VERSION 5.8 ;
BUSBITCHARS "[]" ;
DIVIDERCHAR "/" ;
UNITS
    DATABASE MICRONS 1000 ;
END UNITS

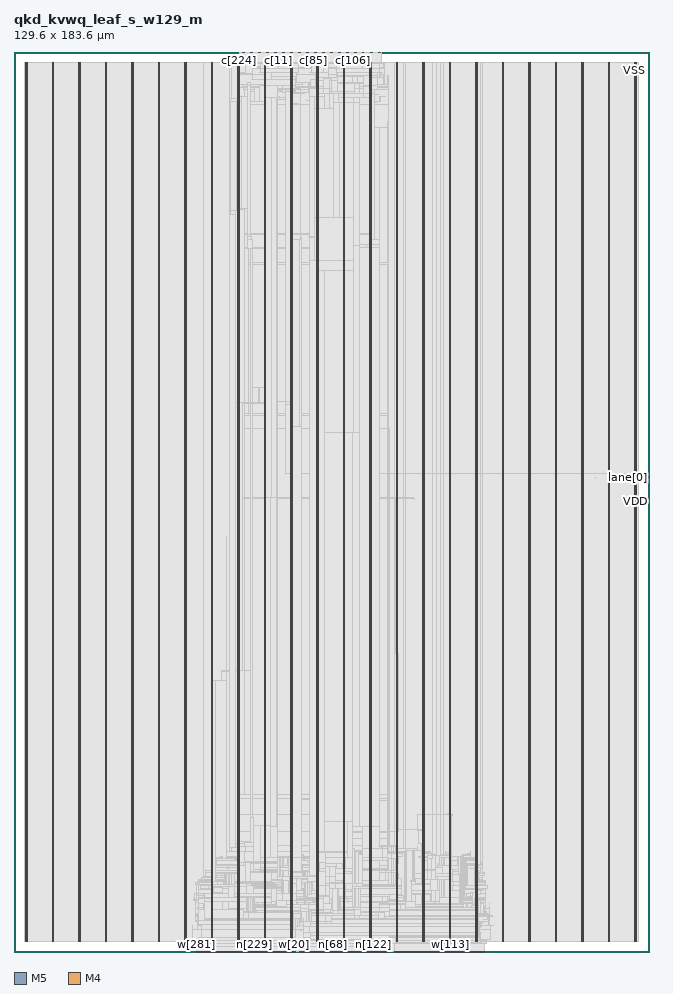
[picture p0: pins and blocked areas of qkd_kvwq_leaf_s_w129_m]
MACRO qkd_kvwq_leaf_s_w129_m
  FOREIGN qkd_kvwq_leaf_s_w129_m 0 0 ;
  CLASS BLOCK ;
  SIZE 129.6 BY 183.6 ;
  PIN c[0]
    DIRECTION INPUT ;
    USE SIGNAL ;
    PORT
      LAYER M5 ;
        RECT  52.848 183.516 52.872 183.6 ;
    END
  END c[0]
  PIN c[100]
    DIRECTION INPUT ;
    USE SIGNAL ;
    PORT
      LAYER M5 ;
        RECT  68.592 183.516 68.616 183.6 ;
    END
  END c[100]
  PIN c[101]
    DIRECTION INPUT ;
    USE SIGNAL ;
    PORT
      LAYER M5 ;
        RECT  68.688 183.516 68.712 183.6 ;
    END
  END c[101]
  PIN c[102]
    DIRECTION INPUT ;
    USE SIGNAL ;
    PORT
      LAYER M5 ;
        RECT  68.784 183.516 68.808 183.6 ;
    END
  END c[102]
  PIN c[103]
    DIRECTION INPUT ;
    USE SIGNAL ;
    PORT
      LAYER M5 ;
        RECT  68.88 183.516 68.904 183.6 ;
    END
  END c[103]
  PIN c[104]
    DIRECTION INPUT ;
    USE SIGNAL ;
    PORT
      LAYER M5 ;
        RECT  68.976 183.516 69 183.6 ;
    END
  END c[104]
  PIN c[105]
    DIRECTION INPUT ;
    USE SIGNAL ;
    PORT
      LAYER M5 ;
        RECT  69.072 183.516 69.096 183.6 ;
    END
  END c[105]
  PIN c[106]
    DIRECTION INPUT ;
    USE SIGNAL ;
    PORT
      LAYER M5 ;
        RECT  69.168 183.516 69.192 183.6 ;
    END
  END c[106]
  PIN c[107]
    DIRECTION INPUT ;
    USE SIGNAL ;
    PORT
      LAYER M5 ;
        RECT  69.264 183.516 69.288 183.6 ;
    END
  END c[107]
  PIN c[108]
    DIRECTION INPUT ;
    USE SIGNAL ;
    PORT
      LAYER M5 ;
        RECT  69.36 183.516 69.384 183.6 ;
    END
  END c[108]
  PIN c[109]
    DIRECTION INPUT ;
    USE SIGNAL ;
    PORT
      LAYER M5 ;
        RECT  69.456 183.516 69.48 183.6 ;
    END
  END c[109]
  PIN c[10]
    DIRECTION INPUT ;
    USE SIGNAL ;
    PORT
      LAYER M5 ;
        RECT  53.808 183.516 53.832 183.6 ;
    END
  END c[10]
  PIN c[110]
    DIRECTION INPUT ;
    USE SIGNAL ;
    PORT
      LAYER M5 ;
        RECT  69.552 183.516 69.576 183.6 ;
    END
  END c[110]
  PIN c[111]
    DIRECTION INPUT ;
    USE SIGNAL ;
    PORT
      LAYER M5 ;
        RECT  69.648 183.516 69.672 183.6 ;
    END
  END c[111]
  PIN c[112]
    DIRECTION INPUT ;
    USE SIGNAL ;
    PORT
      LAYER M5 ;
        RECT  69.744 183.516 69.768 183.6 ;
    END
  END c[112]
  PIN c[113]
    DIRECTION INPUT ;
    USE SIGNAL ;
    PORT
      LAYER M5 ;
        RECT  69.84 183.516 69.864 183.6 ;
    END
  END c[113]
  PIN c[114]
    DIRECTION INPUT ;
    USE SIGNAL ;
    PORT
      LAYER M5 ;
        RECT  69.936 183.516 69.96 183.6 ;
    END
  END c[114]
  PIN c[115]
    DIRECTION INPUT ;
    USE SIGNAL ;
    PORT
      LAYER M5 ;
        RECT  70.032 183.516 70.056 183.6 ;
    END
  END c[115]
  PIN c[116]
    DIRECTION INPUT ;
    USE SIGNAL ;
    PORT
      LAYER M5 ;
        RECT  70.128 183.516 70.152 183.6 ;
    END
  END c[116]
  PIN c[117]
    DIRECTION INPUT ;
    USE SIGNAL ;
    PORT
      LAYER M5 ;
        RECT  70.224 183.516 70.248 183.6 ;
    END
  END c[117]
  PIN c[118]
    DIRECTION INPUT ;
    USE SIGNAL ;
    PORT
      LAYER M5 ;
        RECT  70.32 183.516 70.344 183.6 ;
    END
  END c[118]
  PIN c[119]
    DIRECTION INPUT ;
    USE SIGNAL ;
    PORT
      LAYER M5 ;
        RECT  70.416 183.516 70.44 183.6 ;
    END
  END c[119]
  PIN c[11]
    DIRECTION INPUT ;
    USE SIGNAL ;
    PORT
      LAYER M5 ;
        RECT  53.904 183.516 53.928 183.6 ;
    END
  END c[11]
  PIN c[120]
    DIRECTION INPUT ;
    USE SIGNAL ;
    PORT
      LAYER M5 ;
        RECT  70.512 183.516 70.536 183.6 ;
    END
  END c[120]
  PIN c[121]
    DIRECTION INPUT ;
    USE SIGNAL ;
    PORT
      LAYER M5 ;
        RECT  70.608 183.516 70.632 183.6 ;
    END
  END c[121]
  PIN c[122]
    DIRECTION INPUT ;
    USE SIGNAL ;
    PORT
      LAYER M5 ;
        RECT  70.704 183.516 70.728 183.6 ;
    END
  END c[122]
  PIN c[123]
    DIRECTION INPUT ;
    USE SIGNAL ;
    PORT
      LAYER M5 ;
        RECT  70.8 183.516 70.824 183.6 ;
    END
  END c[123]
  PIN c[124]
    DIRECTION INPUT ;
    USE SIGNAL ;
    PORT
      LAYER M5 ;
        RECT  70.896 183.516 70.92 183.6 ;
    END
  END c[124]
  PIN c[125]
    DIRECTION INPUT ;
    USE SIGNAL ;
    PORT
      LAYER M5 ;
        RECT  70.992 183.516 71.016 183.6 ;
    END
  END c[125]
  PIN c[126]
    DIRECTION INPUT ;
    USE SIGNAL ;
    PORT
      LAYER M5 ;
        RECT  71.088 183.516 71.112 183.6 ;
    END
  END c[126]
  PIN c[127]
    DIRECTION INPUT ;
    USE SIGNAL ;
    PORT
      LAYER M5 ;
        RECT  71.184 183.516 71.208 183.6 ;
    END
  END c[127]
  PIN c[128]
    DIRECTION INPUT ;
    USE SIGNAL ;
    PORT
      LAYER M5 ;
        RECT  65.136 183.516 65.16 183.6 ;
    END
  END c[128]
  PIN c[129]
    DIRECTION INPUT ;
    USE SIGNAL ;
    PORT
      LAYER M5 ;
        RECT  65.232 183.516 65.256 183.6 ;
    END
  END c[129]
  PIN c[12]
    DIRECTION INPUT ;
    USE SIGNAL ;
    PORT
      LAYER M5 ;
        RECT  54 183.516 54.024 183.6 ;
    END
  END c[12]
  PIN c[130]
    DIRECTION INPUT ;
    USE SIGNAL ;
    PORT
      LAYER M5 ;
        RECT  65.328 183.516 65.352 183.6 ;
    END
  END c[130]
  PIN c[131]
    DIRECTION INPUT ;
    USE SIGNAL ;
    PORT
      LAYER M5 ;
        RECT  65.424 183.516 65.448 183.6 ;
    END
  END c[131]
  PIN c[132]
    DIRECTION INPUT ;
    USE SIGNAL ;
    PORT
      LAYER M5 ;
        RECT  65.52 183.516 65.544 183.6 ;
    END
  END c[132]
  PIN c[133]
    DIRECTION INPUT ;
    USE SIGNAL ;
    PORT
      LAYER M5 ;
        RECT  65.616 183.516 65.64 183.6 ;
    END
  END c[133]
  PIN c[134]
    DIRECTION INPUT ;
    USE SIGNAL ;
    PORT
      LAYER M5 ;
        RECT  65.712 183.516 65.736 183.6 ;
    END
  END c[134]
  PIN c[135]
    DIRECTION INPUT ;
    USE SIGNAL ;
    PORT
      LAYER M5 ;
        RECT  65.808 183.516 65.832 183.6 ;
    END
  END c[135]
  PIN c[136]
    DIRECTION INPUT ;
    USE SIGNAL ;
    PORT
      LAYER M5 ;
        RECT  65.904 183.516 65.928 183.6 ;
    END
  END c[136]
  PIN c[137]
    DIRECTION INPUT ;
    USE SIGNAL ;
    PORT
      LAYER M5 ;
        RECT  66 183.516 66.024 183.6 ;
    END
  END c[137]
  PIN c[138]
    DIRECTION INPUT ;
    USE SIGNAL ;
    PORT
      LAYER M5 ;
        RECT  66.096 183.516 66.12 183.6 ;
    END
  END c[138]
  PIN c[139]
    DIRECTION INPUT ;
    USE SIGNAL ;
    PORT
      LAYER M5 ;
        RECT  66.192 183.516 66.216 183.6 ;
    END
  END c[139]
  PIN c[13]
    DIRECTION INPUT ;
    USE SIGNAL ;
    PORT
      LAYER M5 ;
        RECT  54.096 183.516 54.12 183.6 ;
    END
  END c[13]
  PIN c[140]
    DIRECTION INPUT ;
    USE SIGNAL ;
    PORT
      LAYER M5 ;
        RECT  66.288 183.516 66.312 183.6 ;
    END
  END c[140]
  PIN c[141]
    DIRECTION INPUT ;
    USE SIGNAL ;
    PORT
      LAYER M5 ;
        RECT  66.384 183.516 66.408 183.6 ;
    END
  END c[141]
  PIN c[142]
    DIRECTION INPUT ;
    USE SIGNAL ;
    PORT
      LAYER M5 ;
        RECT  66.48 183.516 66.504 183.6 ;
    END
  END c[142]
  PIN c[143]
    DIRECTION INPUT ;
    USE SIGNAL ;
    PORT
      LAYER M5 ;
        RECT  66.576 183.516 66.6 183.6 ;
    END
  END c[143]
  PIN c[144]
    DIRECTION INPUT ;
    USE SIGNAL ;
    PORT
      LAYER M5 ;
        RECT  66.672 183.516 66.696 183.6 ;
    END
  END c[144]
  PIN c[145]
    DIRECTION INPUT ;
    USE SIGNAL ;
    PORT
      LAYER M5 ;
        RECT  66.768 183.516 66.792 183.6 ;
    END
  END c[145]
  PIN c[146]
    DIRECTION INPUT ;
    USE SIGNAL ;
    PORT
      LAYER M5 ;
        RECT  66.864 183.516 66.888 183.6 ;
    END
  END c[146]
  PIN c[147]
    DIRECTION INPUT ;
    USE SIGNAL ;
    PORT
      LAYER M5 ;
        RECT  66.96 183.516 66.984 183.6 ;
    END
  END c[147]
  PIN c[148]
    DIRECTION INPUT ;
    USE SIGNAL ;
    PORT
      LAYER M5 ;
        RECT  67.056 183.516 67.08 183.6 ;
    END
  END c[148]
  PIN c[149]
    DIRECTION INPUT ;
    USE SIGNAL ;
    PORT
      LAYER M5 ;
        RECT  67.152 183.516 67.176 183.6 ;
    END
  END c[149]
  PIN c[14]
    DIRECTION INPUT ;
    USE SIGNAL ;
    PORT
      LAYER M5 ;
        RECT  54.192 183.516 54.216 183.6 ;
    END
  END c[14]
  PIN c[150]
    DIRECTION INPUT ;
    USE SIGNAL ;
    PORT
      LAYER M5 ;
        RECT  67.248 183.516 67.272 183.6 ;
    END
  END c[150]
  PIN c[151]
    DIRECTION INPUT ;
    USE SIGNAL ;
    PORT
      LAYER M5 ;
        RECT  67.344 183.516 67.368 183.6 ;
    END
  END c[151]
  PIN c[152]
    DIRECTION INPUT ;
    USE SIGNAL ;
    PORT
      LAYER M5 ;
        RECT  67.44 183.516 67.464 183.6 ;
    END
  END c[152]
  PIN c[153]
    DIRECTION INPUT ;
    USE SIGNAL ;
    PORT
      LAYER M5 ;
        RECT  67.536 183.516 67.56 183.6 ;
    END
  END c[153]
  PIN c[154]
    DIRECTION INPUT ;
    USE SIGNAL ;
    PORT
      LAYER M5 ;
        RECT  67.632 183.516 67.656 183.6 ;
    END
  END c[154]
  PIN c[155]
    DIRECTION INPUT ;
    USE SIGNAL ;
    PORT
      LAYER M5 ;
        RECT  67.728 183.516 67.752 183.6 ;
    END
  END c[155]
  PIN c[156]
    DIRECTION INPUT ;
    USE SIGNAL ;
    PORT
      LAYER M5 ;
        RECT  67.824 183.516 67.848 183.6 ;
    END
  END c[156]
  PIN c[157]
    DIRECTION INPUT ;
    USE SIGNAL ;
    PORT
      LAYER M5 ;
        RECT  67.92 183.516 67.944 183.6 ;
    END
  END c[157]
  PIN c[158]
    DIRECTION INPUT ;
    USE SIGNAL ;
    PORT
      LAYER M5 ;
        RECT  68.016 183.516 68.04 183.6 ;
    END
  END c[158]
  PIN c[159]
    DIRECTION INPUT ;
    USE SIGNAL ;
    PORT
      LAYER M5 ;
        RECT  68.112 183.516 68.136 183.6 ;
    END
  END c[159]
  PIN c[15]
    DIRECTION INPUT ;
    USE SIGNAL ;
    PORT
      LAYER M5 ;
        RECT  54.288 183.516 54.312 183.6 ;
    END
  END c[15]
  PIN c[160]
    DIRECTION INPUT ;
    USE SIGNAL ;
    PORT
      LAYER M5 ;
        RECT  62.064 183.516 62.088 183.6 ;
    END
  END c[160]
  PIN c[161]
    DIRECTION INPUT ;
    USE SIGNAL ;
    PORT
      LAYER M5 ;
        RECT  62.16 183.516 62.184 183.6 ;
    END
  END c[161]
  PIN c[162]
    DIRECTION INPUT ;
    USE SIGNAL ;
    PORT
      LAYER M5 ;
        RECT  62.256 183.516 62.28 183.6 ;
    END
  END c[162]
  PIN c[163]
    DIRECTION INPUT ;
    USE SIGNAL ;
    PORT
      LAYER M5 ;
        RECT  62.352 183.516 62.376 183.6 ;
    END
  END c[163]
  PIN c[164]
    DIRECTION INPUT ;
    USE SIGNAL ;
    PORT
      LAYER M5 ;
        RECT  62.448 183.516 62.472 183.6 ;
    END
  END c[164]
  PIN c[165]
    DIRECTION INPUT ;
    USE SIGNAL ;
    PORT
      LAYER M5 ;
        RECT  62.544 183.516 62.568 183.6 ;
    END
  END c[165]
  PIN c[166]
    DIRECTION INPUT ;
    USE SIGNAL ;
    PORT
      LAYER M5 ;
        RECT  62.64 183.516 62.664 183.6 ;
    END
  END c[166]
  PIN c[167]
    DIRECTION INPUT ;
    USE SIGNAL ;
    PORT
      LAYER M5 ;
        RECT  62.736 183.516 62.76 183.6 ;
    END
  END c[167]
  PIN c[168]
    DIRECTION INPUT ;
    USE SIGNAL ;
    PORT
      LAYER M5 ;
        RECT  62.832 183.516 62.856 183.6 ;
    END
  END c[168]
  PIN c[169]
    DIRECTION INPUT ;
    USE SIGNAL ;
    PORT
      LAYER M5 ;
        RECT  62.928 183.516 62.952 183.6 ;
    END
  END c[169]
  PIN c[16]
    DIRECTION INPUT ;
    USE SIGNAL ;
    PORT
      LAYER M5 ;
        RECT  54.384 183.516 54.408 183.6 ;
    END
  END c[16]
  PIN c[170]
    DIRECTION INPUT ;
    USE SIGNAL ;
    PORT
      LAYER M5 ;
        RECT  63.024 183.516 63.048 183.6 ;
    END
  END c[170]
  PIN c[171]
    DIRECTION INPUT ;
    USE SIGNAL ;
    PORT
      LAYER M5 ;
        RECT  63.12 183.516 63.144 183.6 ;
    END
  END c[171]
  PIN c[172]
    DIRECTION INPUT ;
    USE SIGNAL ;
    PORT
      LAYER M5 ;
        RECT  63.216 183.516 63.24 183.6 ;
    END
  END c[172]
  PIN c[173]
    DIRECTION INPUT ;
    USE SIGNAL ;
    PORT
      LAYER M5 ;
        RECT  63.312 183.516 63.336 183.6 ;
    END
  END c[173]
  PIN c[174]
    DIRECTION INPUT ;
    USE SIGNAL ;
    PORT
      LAYER M5 ;
        RECT  63.408 183.516 63.432 183.6 ;
    END
  END c[174]
  PIN c[175]
    DIRECTION INPUT ;
    USE SIGNAL ;
    PORT
      LAYER M5 ;
        RECT  63.504 183.516 63.528 183.6 ;
    END
  END c[175]
  PIN c[176]
    DIRECTION INPUT ;
    USE SIGNAL ;
    PORT
      LAYER M5 ;
        RECT  63.6 183.516 63.624 183.6 ;
    END
  END c[176]
  PIN c[177]
    DIRECTION INPUT ;
    USE SIGNAL ;
    PORT
      LAYER M5 ;
        RECT  63.696 183.516 63.72 183.6 ;
    END
  END c[177]
  PIN c[178]
    DIRECTION INPUT ;
    USE SIGNAL ;
    PORT
      LAYER M5 ;
        RECT  63.792 183.516 63.816 183.6 ;
    END
  END c[178]
  PIN c[179]
    DIRECTION INPUT ;
    USE SIGNAL ;
    PORT
      LAYER M5 ;
        RECT  63.888 183.516 63.912 183.6 ;
    END
  END c[179]
  PIN c[17]
    DIRECTION INPUT ;
    USE SIGNAL ;
    PORT
      LAYER M5 ;
        RECT  54.48 183.516 54.504 183.6 ;
    END
  END c[17]
  PIN c[180]
    DIRECTION INPUT ;
    USE SIGNAL ;
    PORT
      LAYER M5 ;
        RECT  63.984 183.516 64.008 183.6 ;
    END
  END c[180]
  PIN c[181]
    DIRECTION INPUT ;
    USE SIGNAL ;
    PORT
      LAYER M5 ;
        RECT  64.08 183.516 64.104 183.6 ;
    END
  END c[181]
  PIN c[182]
    DIRECTION INPUT ;
    USE SIGNAL ;
    PORT
      LAYER M5 ;
        RECT  64.176 183.516 64.2 183.6 ;
    END
  END c[182]
  PIN c[183]
    DIRECTION INPUT ;
    USE SIGNAL ;
    PORT
      LAYER M5 ;
        RECT  64.272 183.516 64.296 183.6 ;
    END
  END c[183]
  PIN c[184]
    DIRECTION INPUT ;
    USE SIGNAL ;
    PORT
      LAYER M5 ;
        RECT  64.368 183.516 64.392 183.6 ;
    END
  END c[184]
  PIN c[185]
    DIRECTION INPUT ;
    USE SIGNAL ;
    PORT
      LAYER M5 ;
        RECT  64.464 183.516 64.488 183.6 ;
    END
  END c[185]
  PIN c[186]
    DIRECTION INPUT ;
    USE SIGNAL ;
    PORT
      LAYER M5 ;
        RECT  64.56 183.516 64.584 183.6 ;
    END
  END c[186]
  PIN c[187]
    DIRECTION INPUT ;
    USE SIGNAL ;
    PORT
      LAYER M5 ;
        RECT  64.656 183.516 64.68 183.6 ;
    END
  END c[187]
  PIN c[188]
    DIRECTION INPUT ;
    USE SIGNAL ;
    PORT
      LAYER M5 ;
        RECT  64.752 183.516 64.776 183.6 ;
    END
  END c[188]
  PIN c[189]
    DIRECTION INPUT ;
    USE SIGNAL ;
    PORT
      LAYER M5 ;
        RECT  64.848 183.516 64.872 183.6 ;
    END
  END c[189]
  PIN c[18]
    DIRECTION INPUT ;
    USE SIGNAL ;
    PORT
      LAYER M5 ;
        RECT  54.576 183.516 54.6 183.6 ;
    END
  END c[18]
  PIN c[190]
    DIRECTION INPUT ;
    USE SIGNAL ;
    PORT
      LAYER M5 ;
        RECT  64.944 183.516 64.968 183.6 ;
    END
  END c[190]
  PIN c[191]
    DIRECTION INPUT ;
    USE SIGNAL ;
    PORT
      LAYER M5 ;
        RECT  65.04 183.516 65.064 183.6 ;
    END
  END c[191]
  PIN c[192]
    DIRECTION INPUT ;
    USE SIGNAL ;
    PORT
      LAYER M5 ;
        RECT  72.048 183.516 72.072 183.6 ;
    END
  END c[192]
  PIN c[193]
    DIRECTION INPUT ;
    USE SIGNAL ;
    PORT
      LAYER M5 ;
        RECT  72.144 183.516 72.168 183.6 ;
    END
  END c[193]
  PIN c[194]
    DIRECTION INPUT ;
    USE SIGNAL ;
    PORT
      LAYER M5 ;
        RECT  72.24 183.516 72.264 183.6 ;
    END
  END c[194]
  PIN c[195]
    DIRECTION INPUT ;
    USE SIGNAL ;
    PORT
      LAYER M5 ;
        RECT  72.336 183.516 72.36 183.6 ;
    END
  END c[195]
  PIN c[196]
    DIRECTION INPUT ;
    USE SIGNAL ;
    PORT
      LAYER M5 ;
        RECT  72.432 183.516 72.456 183.6 ;
    END
  END c[196]
  PIN c[197]
    DIRECTION INPUT ;
    USE SIGNAL ;
    PORT
      LAYER M5 ;
        RECT  72.528 183.516 72.552 183.6 ;
    END
  END c[197]
  PIN c[198]
    DIRECTION INPUT ;
    USE SIGNAL ;
    PORT
      LAYER M5 ;
        RECT  72.624 183.516 72.648 183.6 ;
    END
  END c[198]
  PIN c[199]
    DIRECTION INPUT ;
    USE SIGNAL ;
    PORT
      LAYER M5 ;
        RECT  72.72 183.516 72.744 183.6 ;
    END
  END c[199]
  PIN c[19]
    DIRECTION INPUT ;
    USE SIGNAL ;
    PORT
      LAYER M5 ;
        RECT  54.672 183.516 54.696 183.6 ;
    END
  END c[19]
  PIN c[1]
    DIRECTION INPUT ;
    USE SIGNAL ;
    PORT
      LAYER M5 ;
        RECT  52.944 183.516 52.968 183.6 ;
    END
  END c[1]
  PIN c[200]
    DIRECTION INPUT ;
    USE SIGNAL ;
    PORT
      LAYER M5 ;
        RECT  72.816 183.516 72.84 183.6 ;
    END
  END c[200]
  PIN c[201]
    DIRECTION INPUT ;
    USE SIGNAL ;
    PORT
      LAYER M5 ;
        RECT  72.912 183.516 72.936 183.6 ;
    END
  END c[201]
  PIN c[202]
    DIRECTION INPUT ;
    USE SIGNAL ;
    PORT
      LAYER M5 ;
        RECT  73.008 183.516 73.032 183.6 ;
    END
  END c[202]
  PIN c[203]
    DIRECTION INPUT ;
    USE SIGNAL ;
    PORT
      LAYER M5 ;
        RECT  73.104 183.516 73.128 183.6 ;
    END
  END c[203]
  PIN c[204]
    DIRECTION INPUT ;
    USE SIGNAL ;
    PORT
      LAYER M5 ;
        RECT  73.2 183.516 73.224 183.6 ;
    END
  END c[204]
  PIN c[205]
    DIRECTION INPUT ;
    USE SIGNAL ;
    PORT
      LAYER M5 ;
        RECT  73.296 183.516 73.32 183.6 ;
    END
  END c[205]
  PIN c[206]
    DIRECTION INPUT ;
    USE SIGNAL ;
    PORT
      LAYER M5 ;
        RECT  73.392 183.516 73.416 183.6 ;
    END
  END c[206]
  PIN c[207]
    DIRECTION INPUT ;
    USE SIGNAL ;
    PORT
      LAYER M5 ;
        RECT  73.488 183.516 73.512 183.6 ;
    END
  END c[207]
  PIN c[208]
    DIRECTION INPUT ;
    USE SIGNAL ;
    PORT
      LAYER M5 ;
        RECT  73.584 183.516 73.608 183.6 ;
    END
  END c[208]
  PIN c[209]
    DIRECTION INPUT ;
    USE SIGNAL ;
    PORT
      LAYER M5 ;
        RECT  73.68 183.516 73.704 183.6 ;
    END
  END c[209]
  PIN c[20]
    DIRECTION INPUT ;
    USE SIGNAL ;
    PORT
      LAYER M5 ;
        RECT  54.768 183.516 54.792 183.6 ;
    END
  END c[20]
  PIN c[210]
    DIRECTION INPUT ;
    USE SIGNAL ;
    PORT
      LAYER M5 ;
        RECT  73.776 183.516 73.8 183.6 ;
    END
  END c[210]
  PIN c[211]
    DIRECTION INPUT ;
    USE SIGNAL ;
    PORT
      LAYER M5 ;
        RECT  73.872 183.516 73.896 183.6 ;
    END
  END c[211]
  PIN c[212]
    DIRECTION INPUT ;
    USE SIGNAL ;
    PORT
      LAYER M5 ;
        RECT  73.968 183.516 73.992 183.6 ;
    END
  END c[212]
  PIN c[213]
    DIRECTION INPUT ;
    USE SIGNAL ;
    PORT
      LAYER M5 ;
        RECT  74.064 183.516 74.088 183.6 ;
    END
  END c[213]
  PIN c[214]
    DIRECTION INPUT ;
    USE SIGNAL ;
    PORT
      LAYER M5 ;
        RECT  74.16 183.516 74.184 183.6 ;
    END
  END c[214]
  PIN c[215]
    DIRECTION INPUT ;
    USE SIGNAL ;
    PORT
      LAYER M5 ;
        RECT  74.256 183.516 74.28 183.6 ;
    END
  END c[215]
  PIN c[216]
    DIRECTION INPUT ;
    USE SIGNAL ;
    PORT
      LAYER M5 ;
        RECT  74.352 183.516 74.376 183.6 ;
    END
  END c[216]
  PIN c[217]
    DIRECTION INPUT ;
    USE SIGNAL ;
    PORT
      LAYER M5 ;
        RECT  74.448 183.516 74.472 183.6 ;
    END
  END c[217]
  PIN c[218]
    DIRECTION INPUT ;
    USE SIGNAL ;
    PORT
      LAYER M5 ;
        RECT  74.544 183.516 74.568 183.6 ;
    END
  END c[218]
  PIN c[219]
    DIRECTION INPUT ;
    USE SIGNAL ;
    PORT
      LAYER M5 ;
        RECT  74.64 183.516 74.664 183.6 ;
    END
  END c[219]
  PIN c[21]
    DIRECTION INPUT ;
    USE SIGNAL ;
    PORT
      LAYER M5 ;
        RECT  54.864 183.516 54.888 183.6 ;
    END
  END c[21]
  PIN c[220]
    DIRECTION INPUT ;
    USE SIGNAL ;
    PORT
      LAYER M5 ;
        RECT  74.736 183.516 74.76 183.6 ;
    END
  END c[220]
  PIN c[221]
    DIRECTION INPUT ;
    USE SIGNAL ;
    PORT
      LAYER M5 ;
        RECT  74.832 183.516 74.856 183.6 ;
    END
  END c[221]
  PIN c[222]
    DIRECTION INPUT ;
    USE SIGNAL ;
    PORT
      LAYER M5 ;
        RECT  74.928 183.516 74.952 183.6 ;
    END
  END c[222]
  PIN c[223]
    DIRECTION INPUT ;
    USE SIGNAL ;
    PORT
      LAYER M5 ;
        RECT  75.024 183.516 75.048 183.6 ;
    END
  END c[223]
  PIN c[224]
    DIRECTION INPUT ;
    USE SIGNAL ;
    PORT
      LAYER M5 ;
        RECT  45.936 183.516 45.96 183.6 ;
    END
  END c[224]
  PIN c[225]
    DIRECTION INPUT ;
    USE SIGNAL ;
    PORT
      LAYER M5 ;
        RECT  46.032 183.516 46.056 183.6 ;
    END
  END c[225]
  PIN c[226]
    DIRECTION INPUT ;
    USE SIGNAL ;
    PORT
      LAYER M5 ;
        RECT  46.128 183.516 46.152 183.6 ;
    END
  END c[226]
  PIN c[227]
    DIRECTION INPUT ;
    USE SIGNAL ;
    PORT
      LAYER M5 ;
        RECT  46.224 183.516 46.248 183.6 ;
    END
  END c[227]
  PIN c[228]
    DIRECTION INPUT ;
    USE SIGNAL ;
    PORT
      LAYER M5 ;
        RECT  46.32 183.516 46.344 183.6 ;
    END
  END c[228]
  PIN c[229]
    DIRECTION INPUT ;
    USE SIGNAL ;
    PORT
      LAYER M5 ;
        RECT  46.416 183.516 46.44 183.6 ;
    END
  END c[229]
  PIN c[22]
    DIRECTION INPUT ;
    USE SIGNAL ;
    PORT
      LAYER M5 ;
        RECT  54.96 183.516 54.984 183.6 ;
    END
  END c[22]
  PIN c[230]
    DIRECTION INPUT ;
    USE SIGNAL ;
    PORT
      LAYER M5 ;
        RECT  46.512 183.516 46.536 183.6 ;
    END
  END c[230]
  PIN c[231]
    DIRECTION INPUT ;
    USE SIGNAL ;
    PORT
      LAYER M5 ;
        RECT  46.608 183.516 46.632 183.6 ;
    END
  END c[231]
  PIN c[232]
    DIRECTION INPUT ;
    USE SIGNAL ;
    PORT
      LAYER M5 ;
        RECT  46.704 183.516 46.728 183.6 ;
    END
  END c[232]
  PIN c[233]
    DIRECTION INPUT ;
    USE SIGNAL ;
    PORT
      LAYER M5 ;
        RECT  46.8 183.516 46.824 183.6 ;
    END
  END c[233]
  PIN c[234]
    DIRECTION INPUT ;
    USE SIGNAL ;
    PORT
      LAYER M5 ;
        RECT  46.896 183.516 46.92 183.6 ;
    END
  END c[234]
  PIN c[235]
    DIRECTION INPUT ;
    USE SIGNAL ;
    PORT
      LAYER M5 ;
        RECT  46.992 183.516 47.016 183.6 ;
    END
  END c[235]
  PIN c[236]
    DIRECTION INPUT ;
    USE SIGNAL ;
    PORT
      LAYER M5 ;
        RECT  47.088 183.516 47.112 183.6 ;
    END
  END c[236]
  PIN c[237]
    DIRECTION INPUT ;
    USE SIGNAL ;
    PORT
      LAYER M5 ;
        RECT  47.184 183.516 47.208 183.6 ;
    END
  END c[237]
  PIN c[238]
    DIRECTION INPUT ;
    USE SIGNAL ;
    PORT
      LAYER M5 ;
        RECT  47.28 183.516 47.304 183.6 ;
    END
  END c[238]
  PIN c[239]
    DIRECTION INPUT ;
    USE SIGNAL ;
    PORT
      LAYER M5 ;
        RECT  47.376 183.516 47.4 183.6 ;
    END
  END c[239]
  PIN c[23]
    DIRECTION INPUT ;
    USE SIGNAL ;
    PORT
      LAYER M5 ;
        RECT  55.056 183.516 55.08 183.6 ;
    END
  END c[23]
  PIN c[240]
    DIRECTION INPUT ;
    USE SIGNAL ;
    PORT
      LAYER M5 ;
        RECT  47.472 183.516 47.496 183.6 ;
    END
  END c[240]
  PIN c[241]
    DIRECTION INPUT ;
    USE SIGNAL ;
    PORT
      LAYER M5 ;
        RECT  47.568 183.516 47.592 183.6 ;
    END
  END c[241]
  PIN c[242]
    DIRECTION INPUT ;
    USE SIGNAL ;
    PORT
      LAYER M5 ;
        RECT  47.664 183.516 47.688 183.6 ;
    END
  END c[242]
  PIN c[243]
    DIRECTION INPUT ;
    USE SIGNAL ;
    PORT
      LAYER M5 ;
        RECT  47.76 183.516 47.784 183.6 ;
    END
  END c[243]
  PIN c[244]
    DIRECTION INPUT ;
    USE SIGNAL ;
    PORT
      LAYER M5 ;
        RECT  47.856 183.516 47.88 183.6 ;
    END
  END c[244]
  PIN c[245]
    DIRECTION INPUT ;
    USE SIGNAL ;
    PORT
      LAYER M5 ;
        RECT  47.952 183.516 47.976 183.6 ;
    END
  END c[245]
  PIN c[246]
    DIRECTION INPUT ;
    USE SIGNAL ;
    PORT
      LAYER M5 ;
        RECT  48.048 183.516 48.072 183.6 ;
    END
  END c[246]
  PIN c[247]
    DIRECTION INPUT ;
    USE SIGNAL ;
    PORT
      LAYER M5 ;
        RECT  48.144 183.516 48.168 183.6 ;
    END
  END c[247]
  PIN c[248]
    DIRECTION INPUT ;
    USE SIGNAL ;
    PORT
      LAYER M5 ;
        RECT  48.24 183.516 48.264 183.6 ;
    END
  END c[248]
  PIN c[249]
    DIRECTION INPUT ;
    USE SIGNAL ;
    PORT
      LAYER M5 ;
        RECT  48.336 183.516 48.36 183.6 ;
    END
  END c[249]
  PIN c[24]
    DIRECTION INPUT ;
    USE SIGNAL ;
    PORT
      LAYER M5 ;
        RECT  55.152 183.516 55.176 183.6 ;
    END
  END c[24]
  PIN c[250]
    DIRECTION INPUT ;
    USE SIGNAL ;
    PORT
      LAYER M5 ;
        RECT  48.432 183.516 48.456 183.6 ;
    END
  END c[250]
  PIN c[251]
    DIRECTION INPUT ;
    USE SIGNAL ;
    PORT
      LAYER M5 ;
        RECT  48.528 183.516 48.552 183.6 ;
    END
  END c[251]
  PIN c[252]
    DIRECTION INPUT ;
    USE SIGNAL ;
    PORT
      LAYER M5 ;
        RECT  48.624 183.516 48.648 183.6 ;
    END
  END c[252]
  PIN c[253]
    DIRECTION INPUT ;
    USE SIGNAL ;
    PORT
      LAYER M5 ;
        RECT  48.72 183.516 48.744 183.6 ;
    END
  END c[253]
  PIN c[254]
    DIRECTION INPUT ;
    USE SIGNAL ;
    PORT
      LAYER M5 ;
        RECT  48.816 183.516 48.84 183.6 ;
    END
  END c[254]
  PIN c[255]
    DIRECTION INPUT ;
    USE SIGNAL ;
    PORT
      LAYER M5 ;
        RECT  48.912 183.516 48.936 183.6 ;
    END
  END c[255]
  PIN c[256]
    DIRECTION INPUT ;
    USE SIGNAL ;
    PORT
      LAYER M5 ;
        RECT  49.008 183.516 49.032 183.6 ;
    END
  END c[256]
  PIN c[257]
    DIRECTION INPUT ;
    USE SIGNAL ;
    PORT
      LAYER M5 ;
        RECT  49.104 183.516 49.128 183.6 ;
    END
  END c[257]
  PIN c[258]
    DIRECTION INPUT ;
    USE SIGNAL ;
    PORT
      LAYER M5 ;
        RECT  49.2 183.516 49.224 183.6 ;
    END
  END c[258]
  PIN c[259]
    DIRECTION INPUT ;
    USE SIGNAL ;
    PORT
      LAYER M5 ;
        RECT  49.296 183.516 49.32 183.6 ;
    END
  END c[259]
  PIN c[25]
    DIRECTION INPUT ;
    USE SIGNAL ;
    PORT
      LAYER M5 ;
        RECT  55.248 183.516 55.272 183.6 ;
    END
  END c[25]
  PIN c[260]
    DIRECTION INPUT ;
    USE SIGNAL ;
    PORT
      LAYER M5 ;
        RECT  49.392 183.516 49.416 183.6 ;
    END
  END c[260]
  PIN c[261]
    DIRECTION INPUT ;
    USE SIGNAL ;
    PORT
      LAYER M5 ;
        RECT  49.488 183.516 49.512 183.6 ;
    END
  END c[261]
  PIN c[262]
    DIRECTION INPUT ;
    USE SIGNAL ;
    PORT
      LAYER M5 ;
        RECT  49.584 183.516 49.608 183.6 ;
    END
  END c[262]
  PIN c[263]
    DIRECTION INPUT ;
    USE SIGNAL ;
    PORT
      LAYER M5 ;
        RECT  49.68 183.516 49.704 183.6 ;
    END
  END c[263]
  PIN c[264]
    DIRECTION INPUT ;
    USE SIGNAL ;
    PORT
      LAYER M5 ;
        RECT  49.776 183.516 49.8 183.6 ;
    END
  END c[264]
  PIN c[265]
    DIRECTION INPUT ;
    USE SIGNAL ;
    PORT
      LAYER M5 ;
        RECT  49.872 183.516 49.896 183.6 ;
    END
  END c[265]
  PIN c[266]
    DIRECTION INPUT ;
    USE SIGNAL ;
    PORT
      LAYER M5 ;
        RECT  49.968 183.516 49.992 183.6 ;
    END
  END c[266]
  PIN c[267]
    DIRECTION INPUT ;
    USE SIGNAL ;
    PORT
      LAYER M5 ;
        RECT  50.064 183.516 50.088 183.6 ;
    END
  END c[267]
  PIN c[268]
    DIRECTION INPUT ;
    USE SIGNAL ;
    PORT
      LAYER M5 ;
        RECT  50.16 183.516 50.184 183.6 ;
    END
  END c[268]
  PIN c[269]
    DIRECTION INPUT ;
    USE SIGNAL ;
    PORT
      LAYER M5 ;
        RECT  50.256 183.516 50.28 183.6 ;
    END
  END c[269]
  PIN c[26]
    DIRECTION INPUT ;
    USE SIGNAL ;
    PORT
      LAYER M5 ;
        RECT  55.344 183.516 55.368 183.6 ;
    END
  END c[26]
  PIN c[270]
    DIRECTION INPUT ;
    USE SIGNAL ;
    PORT
      LAYER M5 ;
        RECT  50.352 183.516 50.376 183.6 ;
    END
  END c[270]
  PIN c[271]
    DIRECTION INPUT ;
    USE SIGNAL ;
    PORT
      LAYER M5 ;
        RECT  50.448 183.516 50.472 183.6 ;
    END
  END c[271]
  PIN c[272]
    DIRECTION INPUT ;
    USE SIGNAL ;
    PORT
      LAYER M5 ;
        RECT  50.544 183.516 50.568 183.6 ;
    END
  END c[272]
  PIN c[273]
    DIRECTION INPUT ;
    USE SIGNAL ;
    PORT
      LAYER M5 ;
        RECT  50.64 183.516 50.664 183.6 ;
    END
  END c[273]
  PIN c[274]
    DIRECTION INPUT ;
    USE SIGNAL ;
    PORT
      LAYER M5 ;
        RECT  50.736 183.516 50.76 183.6 ;
    END
  END c[274]
  PIN c[275]
    DIRECTION INPUT ;
    USE SIGNAL ;
    PORT
      LAYER M5 ;
        RECT  50.832 183.516 50.856 183.6 ;
    END
  END c[275]
  PIN c[276]
    DIRECTION INPUT ;
    USE SIGNAL ;
    PORT
      LAYER M5 ;
        RECT  50.928 183.516 50.952 183.6 ;
    END
  END c[276]
  PIN c[277]
    DIRECTION INPUT ;
    USE SIGNAL ;
    PORT
      LAYER M5 ;
        RECT  51.024 183.516 51.048 183.6 ;
    END
  END c[277]
  PIN c[278]
    DIRECTION INPUT ;
    USE SIGNAL ;
    PORT
      LAYER M5 ;
        RECT  51.12 183.516 51.144 183.6 ;
    END
  END c[278]
  PIN c[279]
    DIRECTION INPUT ;
    USE SIGNAL ;
    PORT
      LAYER M5 ;
        RECT  51.216 183.516 51.24 183.6 ;
    END
  END c[279]
  PIN c[27]
    DIRECTION INPUT ;
    USE SIGNAL ;
    PORT
      LAYER M5 ;
        RECT  55.44 183.516 55.464 183.6 ;
    END
  END c[27]
  PIN c[280]
    DIRECTION INPUT ;
    USE SIGNAL ;
    PORT
      LAYER M5 ;
        RECT  51.312 183.516 51.336 183.6 ;
    END
  END c[280]
  PIN c[281]
    DIRECTION INPUT ;
    USE SIGNAL ;
    PORT
      LAYER M5 ;
        RECT  51.408 183.516 51.432 183.6 ;
    END
  END c[281]
  PIN c[282]
    DIRECTION INPUT ;
    USE SIGNAL ;
    PORT
      LAYER M5 ;
        RECT  51.504 183.516 51.528 183.6 ;
    END
  END c[282]
  PIN c[283]
    DIRECTION INPUT ;
    USE SIGNAL ;
    PORT
      LAYER M5 ;
        RECT  51.6 183.516 51.624 183.6 ;
    END
  END c[283]
  PIN c[284]
    DIRECTION INPUT ;
    USE SIGNAL ;
    PORT
      LAYER M5 ;
        RECT  51.696 183.516 51.72 183.6 ;
    END
  END c[284]
  PIN c[285]
    DIRECTION INPUT ;
    USE SIGNAL ;
    PORT
      LAYER M5 ;
        RECT  51.792 183.516 51.816 183.6 ;
    END
  END c[285]
  PIN c[286]
    DIRECTION INPUT ;
    USE SIGNAL ;
    PORT
      LAYER M5 ;
        RECT  51.888 183.516 51.912 183.6 ;
    END
  END c[286]
  PIN c[287]
    DIRECTION INPUT ;
    USE SIGNAL ;
    PORT
      LAYER M5 ;
        RECT  51.984 183.516 52.008 183.6 ;
    END
  END c[287]
  PIN c[288]
    DIRECTION INPUT ;
    USE SIGNAL ;
    PORT
      LAYER M5 ;
        RECT  52.08 183.516 52.104 183.6 ;
    END
  END c[288]
  PIN c[289]
    DIRECTION INPUT ;
    USE SIGNAL ;
    PORT
      LAYER M5 ;
        RECT  52.176 183.516 52.2 183.6 ;
    END
  END c[289]
  PIN c[28]
    DIRECTION INPUT ;
    USE SIGNAL ;
    PORT
      LAYER M5 ;
        RECT  55.536 183.516 55.56 183.6 ;
    END
  END c[28]
  PIN c[290]
    DIRECTION INPUT ;
    USE SIGNAL ;
    PORT
      LAYER M5 ;
        RECT  52.272 183.516 52.296 183.6 ;
    END
  END c[290]
  PIN c[291]
    DIRECTION INPUT ;
    USE SIGNAL ;
    PORT
      LAYER M5 ;
        RECT  52.368 183.516 52.392 183.6 ;
    END
  END c[291]
  PIN c[292]
    DIRECTION INPUT ;
    USE SIGNAL ;
    PORT
      LAYER M5 ;
        RECT  52.464 183.516 52.488 183.6 ;
    END
  END c[292]
  PIN c[29]
    DIRECTION INPUT ;
    USE SIGNAL ;
    PORT
      LAYER M5 ;
        RECT  55.632 183.516 55.656 183.6 ;
    END
  END c[29]
  PIN c[2]
    DIRECTION INPUT ;
    USE SIGNAL ;
    PORT
      LAYER M5 ;
        RECT  53.04 183.516 53.064 183.6 ;
    END
  END c[2]
  PIN c[30]
    DIRECTION INPUT ;
    USE SIGNAL ;
    PORT
      LAYER M5 ;
        RECT  55.728 183.516 55.752 183.6 ;
    END
  END c[30]
  PIN c[31]
    DIRECTION INPUT ;
    USE SIGNAL ;
    PORT
      LAYER M5 ;
        RECT  55.824 183.516 55.848 183.6 ;
    END
  END c[31]
  PIN c[32]
    DIRECTION INPUT ;
    USE SIGNAL ;
    PORT
      LAYER M5 ;
        RECT  55.92 183.516 55.944 183.6 ;
    END
  END c[32]
  PIN c[33]
    DIRECTION INPUT ;
    USE SIGNAL ;
    PORT
      LAYER M5 ;
        RECT  56.016 183.516 56.04 183.6 ;
    END
  END c[33]
  PIN c[34]
    DIRECTION INPUT ;
    USE SIGNAL ;
    PORT
      LAYER M5 ;
        RECT  56.112 183.516 56.136 183.6 ;
    END
  END c[34]
  PIN c[35]
    DIRECTION INPUT ;
    USE SIGNAL ;
    PORT
      LAYER M5 ;
        RECT  56.208 183.516 56.232 183.6 ;
    END
  END c[35]
  PIN c[36]
    DIRECTION INPUT ;
    USE SIGNAL ;
    PORT
      LAYER M5 ;
        RECT  56.304 183.516 56.328 183.6 ;
    END
  END c[36]
  PIN c[37]
    DIRECTION INPUT ;
    USE SIGNAL ;
    PORT
      LAYER M5 ;
        RECT  56.4 183.516 56.424 183.6 ;
    END
  END c[37]
  PIN c[38]
    DIRECTION INPUT ;
    USE SIGNAL ;
    PORT
      LAYER M5 ;
        RECT  56.496 183.516 56.52 183.6 ;
    END
  END c[38]
  PIN c[39]
    DIRECTION INPUT ;
    USE SIGNAL ;
    PORT
      LAYER M5 ;
        RECT  56.592 183.516 56.616 183.6 ;
    END
  END c[39]
  PIN c[3]
    DIRECTION INPUT ;
    USE SIGNAL ;
    PORT
      LAYER M5 ;
        RECT  53.136 183.516 53.16 183.6 ;
    END
  END c[3]
  PIN c[40]
    DIRECTION INPUT ;
    USE SIGNAL ;
    PORT
      LAYER M5 ;
        RECT  56.688 183.516 56.712 183.6 ;
    END
  END c[40]
  PIN c[41]
    DIRECTION INPUT ;
    USE SIGNAL ;
    PORT
      LAYER M5 ;
        RECT  56.784 183.516 56.808 183.6 ;
    END
  END c[41]
  PIN c[42]
    DIRECTION INPUT ;
    USE SIGNAL ;
    PORT
      LAYER M5 ;
        RECT  56.88 183.516 56.904 183.6 ;
    END
  END c[42]
  PIN c[43]
    DIRECTION INPUT ;
    USE SIGNAL ;
    PORT
      LAYER M5 ;
        RECT  56.976 183.516 57 183.6 ;
    END
  END c[43]
  PIN c[44]
    DIRECTION INPUT ;
    USE SIGNAL ;
    PORT
      LAYER M5 ;
        RECT  57.072 183.516 57.096 183.6 ;
    END
  END c[44]
  PIN c[45]
    DIRECTION INPUT ;
    USE SIGNAL ;
    PORT
      LAYER M5 ;
        RECT  57.168 183.516 57.192 183.6 ;
    END
  END c[45]
  PIN c[46]
    DIRECTION INPUT ;
    USE SIGNAL ;
    PORT
      LAYER M5 ;
        RECT  57.264 183.516 57.288 183.6 ;
    END
  END c[46]
  PIN c[47]
    DIRECTION INPUT ;
    USE SIGNAL ;
    PORT
      LAYER M5 ;
        RECT  57.36 183.516 57.384 183.6 ;
    END
  END c[47]
  PIN c[48]
    DIRECTION INPUT ;
    USE SIGNAL ;
    PORT
      LAYER M5 ;
        RECT  57.456 183.516 57.48 183.6 ;
    END
  END c[48]
  PIN c[49]
    DIRECTION INPUT ;
    USE SIGNAL ;
    PORT
      LAYER M5 ;
        RECT  57.552 183.516 57.576 183.6 ;
    END
  END c[49]
  PIN c[4]
    DIRECTION INPUT ;
    USE SIGNAL ;
    PORT
      LAYER M5 ;
        RECT  53.232 183.516 53.256 183.6 ;
    END
  END c[4]
  PIN c[50]
    DIRECTION INPUT ;
    USE SIGNAL ;
    PORT
      LAYER M5 ;
        RECT  57.648 183.516 57.672 183.6 ;
    END
  END c[50]
  PIN c[51]
    DIRECTION INPUT ;
    USE SIGNAL ;
    PORT
      LAYER M5 ;
        RECT  57.744 183.516 57.768 183.6 ;
    END
  END c[51]
  PIN c[52]
    DIRECTION INPUT ;
    USE SIGNAL ;
    PORT
      LAYER M5 ;
        RECT  57.84 183.516 57.864 183.6 ;
    END
  END c[52]
  PIN c[53]
    DIRECTION INPUT ;
    USE SIGNAL ;
    PORT
      LAYER M5 ;
        RECT  57.936 183.516 57.96 183.6 ;
    END
  END c[53]
  PIN c[54]
    DIRECTION INPUT ;
    USE SIGNAL ;
    PORT
      LAYER M5 ;
        RECT  58.032 183.516 58.056 183.6 ;
    END
  END c[54]
  PIN c[55]
    DIRECTION INPUT ;
    USE SIGNAL ;
    PORT
      LAYER M5 ;
        RECT  58.128 183.516 58.152 183.6 ;
    END
  END c[55]
  PIN c[56]
    DIRECTION INPUT ;
    USE SIGNAL ;
    PORT
      LAYER M5 ;
        RECT  58.224 183.516 58.248 183.6 ;
    END
  END c[56]
  PIN c[57]
    DIRECTION INPUT ;
    USE SIGNAL ;
    PORT
      LAYER M5 ;
        RECT  58.32 183.516 58.344 183.6 ;
    END
  END c[57]
  PIN c[58]
    DIRECTION INPUT ;
    USE SIGNAL ;
    PORT
      LAYER M5 ;
        RECT  58.416 183.516 58.44 183.6 ;
    END
  END c[58]
  PIN c[59]
    DIRECTION INPUT ;
    USE SIGNAL ;
    PORT
      LAYER M5 ;
        RECT  58.512 183.516 58.536 183.6 ;
    END
  END c[59]
  PIN c[5]
    DIRECTION INPUT ;
    USE SIGNAL ;
    PORT
      LAYER M5 ;
        RECT  53.328 183.516 53.352 183.6 ;
    END
  END c[5]
  PIN c[60]
    DIRECTION INPUT ;
    USE SIGNAL ;
    PORT
      LAYER M5 ;
        RECT  58.608 183.516 58.632 183.6 ;
    END
  END c[60]
  PIN c[61]
    DIRECTION INPUT ;
    USE SIGNAL ;
    PORT
      LAYER M5 ;
        RECT  58.704 183.516 58.728 183.6 ;
    END
  END c[61]
  PIN c[62]
    DIRECTION INPUT ;
    USE SIGNAL ;
    PORT
      LAYER M5 ;
        RECT  58.8 183.516 58.824 183.6 ;
    END
  END c[62]
  PIN c[63]
    DIRECTION INPUT ;
    USE SIGNAL ;
    PORT
      LAYER M5 ;
        RECT  58.896 183.516 58.92 183.6 ;
    END
  END c[63]
  PIN c[64]
    DIRECTION INPUT ;
    USE SIGNAL ;
    PORT
      LAYER M5 ;
        RECT  58.992 183.516 59.016 183.6 ;
    END
  END c[64]
  PIN c[65]
    DIRECTION INPUT ;
    USE SIGNAL ;
    PORT
      LAYER M5 ;
        RECT  59.088 183.516 59.112 183.6 ;
    END
  END c[65]
  PIN c[66]
    DIRECTION INPUT ;
    USE SIGNAL ;
    PORT
      LAYER M5 ;
        RECT  59.184 183.516 59.208 183.6 ;
    END
  END c[66]
  PIN c[67]
    DIRECTION INPUT ;
    USE SIGNAL ;
    PORT
      LAYER M5 ;
        RECT  59.28 183.516 59.304 183.6 ;
    END
  END c[67]
  PIN c[68]
    DIRECTION INPUT ;
    USE SIGNAL ;
    PORT
      LAYER M5 ;
        RECT  59.376 183.516 59.4 183.6 ;
    END
  END c[68]
  PIN c[69]
    DIRECTION INPUT ;
    USE SIGNAL ;
    PORT
      LAYER M5 ;
        RECT  59.472 183.516 59.496 183.6 ;
    END
  END c[69]
  PIN c[6]
    DIRECTION INPUT ;
    USE SIGNAL ;
    PORT
      LAYER M5 ;
        RECT  53.424 183.516 53.448 183.6 ;
    END
  END c[6]
  PIN c[70]
    DIRECTION INPUT ;
    USE SIGNAL ;
    PORT
      LAYER M5 ;
        RECT  59.568 183.516 59.592 183.6 ;
    END
  END c[70]
  PIN c[71]
    DIRECTION INPUT ;
    USE SIGNAL ;
    PORT
      LAYER M5 ;
        RECT  59.664 183.516 59.688 183.6 ;
    END
  END c[71]
  PIN c[72]
    DIRECTION INPUT ;
    USE SIGNAL ;
    PORT
      LAYER M5 ;
        RECT  59.76 183.516 59.784 183.6 ;
    END
  END c[72]
  PIN c[73]
    DIRECTION INPUT ;
    USE SIGNAL ;
    PORT
      LAYER M5 ;
        RECT  59.856 183.516 59.88 183.6 ;
    END
  END c[73]
  PIN c[74]
    DIRECTION INPUT ;
    USE SIGNAL ;
    PORT
      LAYER M5 ;
        RECT  59.952 183.516 59.976 183.6 ;
    END
  END c[74]
  PIN c[75]
    DIRECTION INPUT ;
    USE SIGNAL ;
    PORT
      LAYER M5 ;
        RECT  60.048 183.516 60.072 183.6 ;
    END
  END c[75]
  PIN c[76]
    DIRECTION INPUT ;
    USE SIGNAL ;
    PORT
      LAYER M5 ;
        RECT  60.144 183.516 60.168 183.6 ;
    END
  END c[76]
  PIN c[77]
    DIRECTION INPUT ;
    USE SIGNAL ;
    PORT
      LAYER M5 ;
        RECT  60.24 183.516 60.264 183.6 ;
    END
  END c[77]
  PIN c[78]
    DIRECTION INPUT ;
    USE SIGNAL ;
    PORT
      LAYER M5 ;
        RECT  60.336 183.516 60.36 183.6 ;
    END
  END c[78]
  PIN c[79]
    DIRECTION INPUT ;
    USE SIGNAL ;
    PORT
      LAYER M5 ;
        RECT  60.432 183.516 60.456 183.6 ;
    END
  END c[79]
  PIN c[7]
    DIRECTION INPUT ;
    USE SIGNAL ;
    PORT
      LAYER M5 ;
        RECT  53.52 183.516 53.544 183.6 ;
    END
  END c[7]
  PIN c[80]
    DIRECTION INPUT ;
    USE SIGNAL ;
    PORT
      LAYER M5 ;
        RECT  60.528 183.516 60.552 183.6 ;
    END
  END c[80]
  PIN c[81]
    DIRECTION INPUT ;
    USE SIGNAL ;
    PORT
      LAYER M5 ;
        RECT  60.624 183.516 60.648 183.6 ;
    END
  END c[81]
  PIN c[82]
    DIRECTION INPUT ;
    USE SIGNAL ;
    PORT
      LAYER M5 ;
        RECT  60.72 183.516 60.744 183.6 ;
    END
  END c[82]
  PIN c[83]
    DIRECTION INPUT ;
    USE SIGNAL ;
    PORT
      LAYER M5 ;
        RECT  60.816 183.516 60.84 183.6 ;
    END
  END c[83]
  PIN c[84]
    DIRECTION INPUT ;
    USE SIGNAL ;
    PORT
      LAYER M5 ;
        RECT  60.912 183.516 60.936 183.6 ;
    END
  END c[84]
  PIN c[85]
    DIRECTION INPUT ;
    USE SIGNAL ;
    PORT
      LAYER M5 ;
        RECT  61.008 183.516 61.032 183.6 ;
    END
  END c[85]
  PIN c[86]
    DIRECTION INPUT ;
    USE SIGNAL ;
    PORT
      LAYER M5 ;
        RECT  61.104 183.516 61.128 183.6 ;
    END
  END c[86]
  PIN c[87]
    DIRECTION INPUT ;
    USE SIGNAL ;
    PORT
      LAYER M5 ;
        RECT  61.2 183.516 61.224 183.6 ;
    END
  END c[87]
  PIN c[88]
    DIRECTION INPUT ;
    USE SIGNAL ;
    PORT
      LAYER M5 ;
        RECT  61.296 183.516 61.32 183.6 ;
    END
  END c[88]
  PIN c[89]
    DIRECTION INPUT ;
    USE SIGNAL ;
    PORT
      LAYER M5 ;
        RECT  61.392 183.516 61.416 183.6 ;
    END
  END c[89]
  PIN c[8]
    DIRECTION INPUT ;
    USE SIGNAL ;
    PORT
      LAYER M5 ;
        RECT  53.616 183.516 53.64 183.6 ;
    END
  END c[8]
  PIN c[90]
    DIRECTION INPUT ;
    USE SIGNAL ;
    PORT
      LAYER M5 ;
        RECT  61.488 183.516 61.512 183.6 ;
    END
  END c[90]
  PIN c[91]
    DIRECTION INPUT ;
    USE SIGNAL ;
    PORT
      LAYER M5 ;
        RECT  61.584 183.516 61.608 183.6 ;
    END
  END c[91]
  PIN c[92]
    DIRECTION INPUT ;
    USE SIGNAL ;
    PORT
      LAYER M5 ;
        RECT  61.68 183.516 61.704 183.6 ;
    END
  END c[92]
  PIN c[93]
    DIRECTION INPUT ;
    USE SIGNAL ;
    PORT
      LAYER M5 ;
        RECT  61.776 183.516 61.8 183.6 ;
    END
  END c[93]
  PIN c[94]
    DIRECTION INPUT ;
    USE SIGNAL ;
    PORT
      LAYER M5 ;
        RECT  61.872 183.516 61.896 183.6 ;
    END
  END c[94]
  PIN c[95]
    DIRECTION INPUT ;
    USE SIGNAL ;
    PORT
      LAYER M5 ;
        RECT  61.968 183.516 61.992 183.6 ;
    END
  END c[95]
  PIN c[96]
    DIRECTION INPUT ;
    USE SIGNAL ;
    PORT
      LAYER M5 ;
        RECT  68.208 183.516 68.232 183.6 ;
    END
  END c[96]
  PIN c[97]
    DIRECTION INPUT ;
    USE SIGNAL ;
    PORT
      LAYER M5 ;
        RECT  68.304 183.516 68.328 183.6 ;
    END
  END c[97]
  PIN c[98]
    DIRECTION INPUT ;
    USE SIGNAL ;
    PORT
      LAYER M5 ;
        RECT  68.4 183.516 68.424 183.6 ;
    END
  END c[98]
  PIN c[99]
    DIRECTION INPUT ;
    USE SIGNAL ;
    PORT
      LAYER M5 ;
        RECT  68.496 183.516 68.52 183.6 ;
    END
  END c[99]
  PIN c[9]
    DIRECTION INPUT ;
    USE SIGNAL ;
    PORT
      LAYER M5 ;
        RECT  53.712 183.516 53.736 183.6 ;
    END
  END c[9]
  PIN ck
    DIRECTION INPUT ;
    USE SIGNAL ;
    PORT
      LAYER M5 ;
        RECT  52.56 183.516 52.584 183.6 ;
    END
  END ck
  PIN dn[0]
    DIRECTION INPUT ;
    USE SIGNAL ;
    PORT
      LAYER M5 ;
        RECT  42.192 0 42.216 0.084 ;
    END
  END dn[0]
  PIN dn[1]
    DIRECTION INPUT ;
    USE SIGNAL ;
    PORT
      LAYER M5 ;
        RECT  42.288 0 42.312 0.084 ;
    END
  END dn[1]
  PIN dp[0]
    DIRECTION OUTPUT ;
    USE SIGNAL ;
    PORT
      LAYER M5 ;
        RECT  52.656 183.516 52.68 183.6 ;
    END
  END dp[0]
  PIN dp[1]
    DIRECTION OUTPUT ;
    USE SIGNAL ;
    PORT
      LAYER M5 ;
        RECT  52.752 183.516 52.776 183.6 ;
    END
  END dp[1]
  PIN lane[0]
    DIRECTION INPUT ;
    USE SIGNAL ;
    PORT
      LAYER M4 ;
        RECT  129.516 96.72 129.6 96.744 ;
    END
  END lane[0]
  PIN lane[1]
    DIRECTION INPUT ;
    USE SIGNAL ;
    PORT
      LAYER M4 ;
        RECT  129.516 96.816 129.6 96.84 ;
    END
  END lane[1]
  PIN lane[2]
    DIRECTION INPUT ;
    USE SIGNAL ;
    PORT
      LAYER M4 ;
        RECT  129.516 96.912 129.6 96.936 ;
    END
  END lane[2]
  PIN n[0]
    DIRECTION OUTPUT ;
    USE SIGNAL ;
    PORT
      LAYER M5 ;
        RECT  42.384 0 42.408 0.084 ;
    END
  END n[0]
  PIN n[100]
    DIRECTION OUTPUT ;
    USE SIGNAL ;
    PORT
      LAYER M5 ;
        RECT  71.184 0 71.208 0.084 ;
    END
  END n[100]
  PIN n[101]
    DIRECTION OUTPUT ;
    USE SIGNAL ;
    PORT
      LAYER M5 ;
        RECT  71.28 0 71.304 0.084 ;
    END
  END n[101]
  PIN n[102]
    DIRECTION OUTPUT ;
    USE SIGNAL ;
    PORT
      LAYER M5 ;
        RECT  71.376 0 71.4 0.084 ;
    END
  END n[102]
  PIN n[103]
    DIRECTION OUTPUT ;
    USE SIGNAL ;
    PORT
      LAYER M5 ;
        RECT  71.472 0 71.496 0.084 ;
    END
  END n[103]
  PIN n[104]
    DIRECTION OUTPUT ;
    USE SIGNAL ;
    PORT
      LAYER M5 ;
        RECT  71.568 0 71.592 0.084 ;
    END
  END n[104]
  PIN n[105]
    DIRECTION OUTPUT ;
    USE SIGNAL ;
    PORT
      LAYER M5 ;
        RECT  71.664 0 71.688 0.084 ;
    END
  END n[105]
  PIN n[106]
    DIRECTION OUTPUT ;
    USE SIGNAL ;
    PORT
      LAYER M5 ;
        RECT  71.76 0 71.784 0.084 ;
    END
  END n[106]
  PIN n[107]
    DIRECTION OUTPUT ;
    USE SIGNAL ;
    PORT
      LAYER M5 ;
        RECT  71.856 0 71.88 0.084 ;
    END
  END n[107]
  PIN n[108]
    DIRECTION OUTPUT ;
    USE SIGNAL ;
    PORT
      LAYER M5 ;
        RECT  71.952 0 71.976 0.084 ;
    END
  END n[108]
  PIN n[109]
    DIRECTION OUTPUT ;
    USE SIGNAL ;
    PORT
      LAYER M5 ;
        RECT  72.048 0 72.072 0.084 ;
    END
  END n[109]
  PIN n[10]
    DIRECTION OUTPUT ;
    USE SIGNAL ;
    PORT
      LAYER M5 ;
        RECT  43.344 0 43.368 0.084 ;
    END
  END n[10]
  PIN n[110]
    DIRECTION OUTPUT ;
    USE SIGNAL ;
    PORT
      LAYER M5 ;
        RECT  72.144 0 72.168 0.084 ;
    END
  END n[110]
  PIN n[111]
    DIRECTION OUTPUT ;
    USE SIGNAL ;
    PORT
      LAYER M5 ;
        RECT  72.24 0 72.264 0.084 ;
    END
  END n[111]
  PIN n[112]
    DIRECTION OUTPUT ;
    USE SIGNAL ;
    PORT
      LAYER M5 ;
        RECT  72.336 0 72.36 0.084 ;
    END
  END n[112]
  PIN n[113]
    DIRECTION OUTPUT ;
    USE SIGNAL ;
    PORT
      LAYER M5 ;
        RECT  72.432 0 72.456 0.084 ;
    END
  END n[113]
  PIN n[114]
    DIRECTION OUTPUT ;
    USE SIGNAL ;
    PORT
      LAYER M5 ;
        RECT  72.528 0 72.552 0.084 ;
    END
  END n[114]
  PIN n[115]
    DIRECTION OUTPUT ;
    USE SIGNAL ;
    PORT
      LAYER M5 ;
        RECT  72.624 0 72.648 0.084 ;
    END
  END n[115]
  PIN n[116]
    DIRECTION OUTPUT ;
    USE SIGNAL ;
    PORT
      LAYER M5 ;
        RECT  72.72 0 72.744 0.084 ;
    END
  END n[116]
  PIN n[117]
    DIRECTION OUTPUT ;
    USE SIGNAL ;
    PORT
      LAYER M5 ;
        RECT  72.816 0 72.84 0.084 ;
    END
  END n[117]
  PIN n[118]
    DIRECTION OUTPUT ;
    USE SIGNAL ;
    PORT
      LAYER M5 ;
        RECT  72.912 0 72.936 0.084 ;
    END
  END n[118]
  PIN n[119]
    DIRECTION OUTPUT ;
    USE SIGNAL ;
    PORT
      LAYER M5 ;
        RECT  73.008 0 73.032 0.084 ;
    END
  END n[119]
  PIN n[11]
    DIRECTION OUTPUT ;
    USE SIGNAL ;
    PORT
      LAYER M5 ;
        RECT  43.44 0 43.464 0.084 ;
    END
  END n[11]
  PIN n[120]
    DIRECTION OUTPUT ;
    USE SIGNAL ;
    PORT
      LAYER M5 ;
        RECT  73.104 0 73.128 0.084 ;
    END
  END n[120]
  PIN n[121]
    DIRECTION OUTPUT ;
    USE SIGNAL ;
    PORT
      LAYER M5 ;
        RECT  73.2 0 73.224 0.084 ;
    END
  END n[121]
  PIN n[122]
    DIRECTION OUTPUT ;
    USE SIGNAL ;
    PORT
      LAYER M5 ;
        RECT  73.296 0 73.32 0.084 ;
    END
  END n[122]
  PIN n[123]
    DIRECTION OUTPUT ;
    USE SIGNAL ;
    PORT
      LAYER M5 ;
        RECT  73.392 0 73.416 0.084 ;
    END
  END n[123]
  PIN n[124]
    DIRECTION OUTPUT ;
    USE SIGNAL ;
    PORT
      LAYER M5 ;
        RECT  73.488 0 73.512 0.084 ;
    END
  END n[124]
  PIN n[125]
    DIRECTION OUTPUT ;
    USE SIGNAL ;
    PORT
      LAYER M5 ;
        RECT  73.584 0 73.608 0.084 ;
    END
  END n[125]
  PIN n[126]
    DIRECTION OUTPUT ;
    USE SIGNAL ;
    PORT
      LAYER M5 ;
        RECT  73.68 0 73.704 0.084 ;
    END
  END n[126]
  PIN n[127]
    DIRECTION OUTPUT ;
    USE SIGNAL ;
    PORT
      LAYER M5 ;
        RECT  73.776 0 73.8 0.084 ;
    END
  END n[127]
  PIN n[128]
    DIRECTION OUTPUT ;
    USE SIGNAL ;
    PORT
      LAYER M5 ;
        RECT  73.872 0 73.896 0.084 ;
    END
  END n[128]
  PIN n[129]
    DIRECTION OUTPUT ;
    USE SIGNAL ;
    PORT
      LAYER M5 ;
        RECT  73.968 0 73.992 0.084 ;
    END
  END n[129]
  PIN n[12]
    DIRECTION OUTPUT ;
    USE SIGNAL ;
    PORT
      LAYER M5 ;
        RECT  43.536 0 43.56 0.084 ;
    END
  END n[12]
  PIN n[130]
    DIRECTION OUTPUT ;
    USE SIGNAL ;
    PORT
      LAYER M5 ;
        RECT  74.064 0 74.088 0.084 ;
    END
  END n[130]
  PIN n[131]
    DIRECTION OUTPUT ;
    USE SIGNAL ;
    PORT
      LAYER M5 ;
        RECT  74.16 0 74.184 0.084 ;
    END
  END n[131]
  PIN n[132]
    DIRECTION OUTPUT ;
    USE SIGNAL ;
    PORT
      LAYER M5 ;
        RECT  74.256 0 74.28 0.084 ;
    END
  END n[132]
  PIN n[133]
    DIRECTION OUTPUT ;
    USE SIGNAL ;
    PORT
      LAYER M5 ;
        RECT  74.352 0 74.376 0.084 ;
    END
  END n[133]
  PIN n[134]
    DIRECTION OUTPUT ;
    USE SIGNAL ;
    PORT
      LAYER M5 ;
        RECT  74.448 0 74.472 0.084 ;
    END
  END n[134]
  PIN n[135]
    DIRECTION OUTPUT ;
    USE SIGNAL ;
    PORT
      LAYER M5 ;
        RECT  74.544 0 74.568 0.084 ;
    END
  END n[135]
  PIN n[136]
    DIRECTION OUTPUT ;
    USE SIGNAL ;
    PORT
      LAYER M5 ;
        RECT  74.64 0 74.664 0.084 ;
    END
  END n[136]
  PIN n[137]
    DIRECTION OUTPUT ;
    USE SIGNAL ;
    PORT
      LAYER M5 ;
        RECT  74.736 0 74.76 0.084 ;
    END
  END n[137]
  PIN n[138]
    DIRECTION OUTPUT ;
    USE SIGNAL ;
    PORT
      LAYER M5 ;
        RECT  74.832 0 74.856 0.084 ;
    END
  END n[138]
  PIN n[139]
    DIRECTION OUTPUT ;
    USE SIGNAL ;
    PORT
      LAYER M5 ;
        RECT  74.928 0 74.952 0.084 ;
    END
  END n[139]
  PIN n[13]
    DIRECTION OUTPUT ;
    USE SIGNAL ;
    PORT
      LAYER M5 ;
        RECT  43.632 0 43.656 0.084 ;
    END
  END n[13]
  PIN n[140]
    DIRECTION OUTPUT ;
    USE SIGNAL ;
    PORT
      LAYER M5 ;
        RECT  75.024 0 75.048 0.084 ;
    END
  END n[140]
  PIN n[141]
    DIRECTION OUTPUT ;
    USE SIGNAL ;
    PORT
      LAYER M5 ;
        RECT  75.12 0 75.144 0.084 ;
    END
  END n[141]
  PIN n[142]
    DIRECTION OUTPUT ;
    USE SIGNAL ;
    PORT
      LAYER M5 ;
        RECT  75.216 0 75.24 0.084 ;
    END
  END n[142]
  PIN n[143]
    DIRECTION OUTPUT ;
    USE SIGNAL ;
    PORT
      LAYER M5 ;
        RECT  75.312 0 75.336 0.084 ;
    END
  END n[143]
  PIN n[144]
    DIRECTION OUTPUT ;
    USE SIGNAL ;
    PORT
      LAYER M5 ;
        RECT  75.408 0 75.432 0.084 ;
    END
  END n[144]
  PIN n[145]
    DIRECTION OUTPUT ;
    USE SIGNAL ;
    PORT
      LAYER M5 ;
        RECT  75.504 0 75.528 0.084 ;
    END
  END n[145]
  PIN n[146]
    DIRECTION OUTPUT ;
    USE SIGNAL ;
    PORT
      LAYER M5 ;
        RECT  75.6 0 75.624 0.084 ;
    END
  END n[146]
  PIN n[147]
    DIRECTION OUTPUT ;
    USE SIGNAL ;
    PORT
      LAYER M5 ;
        RECT  75.696 0 75.72 0.084 ;
    END
  END n[147]
  PIN n[148]
    DIRECTION OUTPUT ;
    USE SIGNAL ;
    PORT
      LAYER M5 ;
        RECT  75.792 0 75.816 0.084 ;
    END
  END n[148]
  PIN n[149]
    DIRECTION OUTPUT ;
    USE SIGNAL ;
    PORT
      LAYER M5 ;
        RECT  75.888 0 75.912 0.084 ;
    END
  END n[149]
  PIN n[14]
    DIRECTION OUTPUT ;
    USE SIGNAL ;
    PORT
      LAYER M5 ;
        RECT  43.728 0 43.752 0.084 ;
    END
  END n[14]
  PIN n[150]
    DIRECTION OUTPUT ;
    USE SIGNAL ;
    PORT
      LAYER M5 ;
        RECT  75.984 0 76.008 0.084 ;
    END
  END n[150]
  PIN n[151]
    DIRECTION OUTPUT ;
    USE SIGNAL ;
    PORT
      LAYER M5 ;
        RECT  76.08 0 76.104 0.084 ;
    END
  END n[151]
  PIN n[152]
    DIRECTION OUTPUT ;
    USE SIGNAL ;
    PORT
      LAYER M5 ;
        RECT  76.176 0 76.2 0.084 ;
    END
  END n[152]
  PIN n[153]
    DIRECTION OUTPUT ;
    USE SIGNAL ;
    PORT
      LAYER M5 ;
        RECT  76.272 0 76.296 0.084 ;
    END
  END n[153]
  PIN n[154]
    DIRECTION OUTPUT ;
    USE SIGNAL ;
    PORT
      LAYER M5 ;
        RECT  76.368 0 76.392 0.084 ;
    END
  END n[154]
  PIN n[155]
    DIRECTION OUTPUT ;
    USE SIGNAL ;
    PORT
      LAYER M5 ;
        RECT  76.464 0 76.488 0.084 ;
    END
  END n[155]
  PIN n[156]
    DIRECTION OUTPUT ;
    USE SIGNAL ;
    PORT
      LAYER M5 ;
        RECT  76.56 0 76.584 0.084 ;
    END
  END n[156]
  PIN n[157]
    DIRECTION OUTPUT ;
    USE SIGNAL ;
    PORT
      LAYER M5 ;
        RECT  76.656 0 76.68 0.084 ;
    END
  END n[157]
  PIN n[158]
    DIRECTION OUTPUT ;
    USE SIGNAL ;
    PORT
      LAYER M5 ;
        RECT  67.536 0 67.56 0.084 ;
    END
  END n[158]
  PIN n[159]
    DIRECTION OUTPUT ;
    USE SIGNAL ;
    PORT
      LAYER M5 ;
        RECT  67.632 0 67.656 0.084 ;
    END
  END n[159]
  PIN n[15]
    DIRECTION OUTPUT ;
    USE SIGNAL ;
    PORT
      LAYER M5 ;
        RECT  43.824 0 43.848 0.084 ;
    END
  END n[15]
  PIN n[160]
    DIRECTION OUTPUT ;
    USE SIGNAL ;
    PORT
      LAYER M5 ;
        RECT  67.728 0 67.752 0.084 ;
    END
  END n[160]
  PIN n[161]
    DIRECTION OUTPUT ;
    USE SIGNAL ;
    PORT
      LAYER M5 ;
        RECT  67.824 0 67.848 0.084 ;
    END
  END n[161]
  PIN n[162]
    DIRECTION OUTPUT ;
    USE SIGNAL ;
    PORT
      LAYER M5 ;
        RECT  67.92 0 67.944 0.084 ;
    END
  END n[162]
  PIN n[163]
    DIRECTION OUTPUT ;
    USE SIGNAL ;
    PORT
      LAYER M5 ;
        RECT  68.016 0 68.04 0.084 ;
    END
  END n[163]
  PIN n[164]
    DIRECTION OUTPUT ;
    USE SIGNAL ;
    PORT
      LAYER M5 ;
        RECT  68.112 0 68.136 0.084 ;
    END
  END n[164]
  PIN n[165]
    DIRECTION OUTPUT ;
    USE SIGNAL ;
    PORT
      LAYER M5 ;
        RECT  68.208 0 68.232 0.084 ;
    END
  END n[165]
  PIN n[166]
    DIRECTION OUTPUT ;
    USE SIGNAL ;
    PORT
      LAYER M5 ;
        RECT  68.304 0 68.328 0.084 ;
    END
  END n[166]
  PIN n[167]
    DIRECTION OUTPUT ;
    USE SIGNAL ;
    PORT
      LAYER M5 ;
        RECT  68.4 0 68.424 0.084 ;
    END
  END n[167]
  PIN n[168]
    DIRECTION OUTPUT ;
    USE SIGNAL ;
    PORT
      LAYER M5 ;
        RECT  68.496 0 68.52 0.084 ;
    END
  END n[168]
  PIN n[169]
    DIRECTION OUTPUT ;
    USE SIGNAL ;
    PORT
      LAYER M5 ;
        RECT  68.592 0 68.616 0.084 ;
    END
  END n[169]
  PIN n[16]
    DIRECTION OUTPUT ;
    USE SIGNAL ;
    PORT
      LAYER M5 ;
        RECT  43.92 0 43.944 0.084 ;
    END
  END n[16]
  PIN n[170]
    DIRECTION OUTPUT ;
    USE SIGNAL ;
    PORT
      LAYER M5 ;
        RECT  68.688 0 68.712 0.084 ;
    END
  END n[170]
  PIN n[171]
    DIRECTION OUTPUT ;
    USE SIGNAL ;
    PORT
      LAYER M5 ;
        RECT  68.784 0 68.808 0.084 ;
    END
  END n[171]
  PIN n[172]
    DIRECTION OUTPUT ;
    USE SIGNAL ;
    PORT
      LAYER M5 ;
        RECT  68.88 0 68.904 0.084 ;
    END
  END n[172]
  PIN n[173]
    DIRECTION OUTPUT ;
    USE SIGNAL ;
    PORT
      LAYER M5 ;
        RECT  68.976 0 69 0.084 ;
    END
  END n[173]
  PIN n[174]
    DIRECTION OUTPUT ;
    USE SIGNAL ;
    PORT
      LAYER M5 ;
        RECT  69.072 0 69.096 0.084 ;
    END
  END n[174]
  PIN n[175]
    DIRECTION OUTPUT ;
    USE SIGNAL ;
    PORT
      LAYER M5 ;
        RECT  69.168 0 69.192 0.084 ;
    END
  END n[175]
  PIN n[176]
    DIRECTION OUTPUT ;
    USE SIGNAL ;
    PORT
      LAYER M5 ;
        RECT  69.264 0 69.288 0.084 ;
    END
  END n[176]
  PIN n[177]
    DIRECTION OUTPUT ;
    USE SIGNAL ;
    PORT
      LAYER M5 ;
        RECT  69.36 0 69.384 0.084 ;
    END
  END n[177]
  PIN n[178]
    DIRECTION OUTPUT ;
    USE SIGNAL ;
    PORT
      LAYER M5 ;
        RECT  69.456 0 69.48 0.084 ;
    END
  END n[178]
  PIN n[179]
    DIRECTION OUTPUT ;
    USE SIGNAL ;
    PORT
      LAYER M5 ;
        RECT  69.552 0 69.576 0.084 ;
    END
  END n[179]
  PIN n[17]
    DIRECTION OUTPUT ;
    USE SIGNAL ;
    PORT
      LAYER M5 ;
        RECT  44.016 0 44.04 0.084 ;
    END
  END n[17]
  PIN n[180]
    DIRECTION OUTPUT ;
    USE SIGNAL ;
    PORT
      LAYER M5 ;
        RECT  69.648 0 69.672 0.084 ;
    END
  END n[180]
  PIN n[181]
    DIRECTION OUTPUT ;
    USE SIGNAL ;
    PORT
      LAYER M5 ;
        RECT  69.744 0 69.768 0.084 ;
    END
  END n[181]
  PIN n[182]
    DIRECTION OUTPUT ;
    USE SIGNAL ;
    PORT
      LAYER M5 ;
        RECT  69.84 0 69.864 0.084 ;
    END
  END n[182]
  PIN n[183]
    DIRECTION OUTPUT ;
    USE SIGNAL ;
    PORT
      LAYER M5 ;
        RECT  69.936 0 69.96 0.084 ;
    END
  END n[183]
  PIN n[184]
    DIRECTION OUTPUT ;
    USE SIGNAL ;
    PORT
      LAYER M5 ;
        RECT  70.032 0 70.056 0.084 ;
    END
  END n[184]
  PIN n[185]
    DIRECTION OUTPUT ;
    USE SIGNAL ;
    PORT
      LAYER M5 ;
        RECT  70.128 0 70.152 0.084 ;
    END
  END n[185]
  PIN n[186]
    DIRECTION OUTPUT ;
    USE SIGNAL ;
    PORT
      LAYER M5 ;
        RECT  70.224 0 70.248 0.084 ;
    END
  END n[186]
  PIN n[187]
    DIRECTION OUTPUT ;
    USE SIGNAL ;
    PORT
      LAYER M5 ;
        RECT  70.32 0 70.344 0.084 ;
    END
  END n[187]
  PIN n[188]
    DIRECTION OUTPUT ;
    USE SIGNAL ;
    PORT
      LAYER M5 ;
        RECT  70.416 0 70.44 0.084 ;
    END
  END n[188]
  PIN n[189]
    DIRECTION OUTPUT ;
    USE SIGNAL ;
    PORT
      LAYER M5 ;
        RECT  70.512 0 70.536 0.084 ;
    END
  END n[189]
  PIN n[18]
    DIRECTION OUTPUT ;
    USE SIGNAL ;
    PORT
      LAYER M5 ;
        RECT  44.112 0 44.136 0.084 ;
    END
  END n[18]
  PIN n[190]
    DIRECTION OUTPUT ;
    USE SIGNAL ;
    PORT
      LAYER M5 ;
        RECT  61.392 0 61.416 0.084 ;
    END
  END n[190]
  PIN n[191]
    DIRECTION OUTPUT ;
    USE SIGNAL ;
    PORT
      LAYER M5 ;
        RECT  61.488 0 61.512 0.084 ;
    END
  END n[191]
  PIN n[192]
    DIRECTION OUTPUT ;
    USE SIGNAL ;
    PORT
      LAYER M5 ;
        RECT  61.584 0 61.608 0.084 ;
    END
  END n[192]
  PIN n[193]
    DIRECTION OUTPUT ;
    USE SIGNAL ;
    PORT
      LAYER M5 ;
        RECT  61.68 0 61.704 0.084 ;
    END
  END n[193]
  PIN n[194]
    DIRECTION OUTPUT ;
    USE SIGNAL ;
    PORT
      LAYER M5 ;
        RECT  61.776 0 61.8 0.084 ;
    END
  END n[194]
  PIN n[195]
    DIRECTION OUTPUT ;
    USE SIGNAL ;
    PORT
      LAYER M5 ;
        RECT  61.872 0 61.896 0.084 ;
    END
  END n[195]
  PIN n[196]
    DIRECTION OUTPUT ;
    USE SIGNAL ;
    PORT
      LAYER M5 ;
        RECT  61.968 0 61.992 0.084 ;
    END
  END n[196]
  PIN n[197]
    DIRECTION OUTPUT ;
    USE SIGNAL ;
    PORT
      LAYER M5 ;
        RECT  62.064 0 62.088 0.084 ;
    END
  END n[197]
  PIN n[198]
    DIRECTION OUTPUT ;
    USE SIGNAL ;
    PORT
      LAYER M5 ;
        RECT  62.16 0 62.184 0.084 ;
    END
  END n[198]
  PIN n[199]
    DIRECTION OUTPUT ;
    USE SIGNAL ;
    PORT
      LAYER M5 ;
        RECT  62.256 0 62.28 0.084 ;
    END
  END n[199]
  PIN n[19]
    DIRECTION OUTPUT ;
    USE SIGNAL ;
    PORT
      LAYER M5 ;
        RECT  44.208 0 44.232 0.084 ;
    END
  END n[19]
  PIN n[1]
    DIRECTION OUTPUT ;
    USE SIGNAL ;
    PORT
      LAYER M5 ;
        RECT  42.48 0 42.504 0.084 ;
    END
  END n[1]
  PIN n[200]
    DIRECTION OUTPUT ;
    USE SIGNAL ;
    PORT
      LAYER M5 ;
        RECT  62.352 0 62.376 0.084 ;
    END
  END n[200]
  PIN n[201]
    DIRECTION OUTPUT ;
    USE SIGNAL ;
    PORT
      LAYER M5 ;
        RECT  62.448 0 62.472 0.084 ;
    END
  END n[201]
  PIN n[202]
    DIRECTION OUTPUT ;
    USE SIGNAL ;
    PORT
      LAYER M5 ;
        RECT  62.544 0 62.568 0.084 ;
    END
  END n[202]
  PIN n[203]
    DIRECTION OUTPUT ;
    USE SIGNAL ;
    PORT
      LAYER M5 ;
        RECT  62.64 0 62.664 0.084 ;
    END
  END n[203]
  PIN n[204]
    DIRECTION OUTPUT ;
    USE SIGNAL ;
    PORT
      LAYER M5 ;
        RECT  62.736 0 62.76 0.084 ;
    END
  END n[204]
  PIN n[205]
    DIRECTION OUTPUT ;
    USE SIGNAL ;
    PORT
      LAYER M5 ;
        RECT  62.832 0 62.856 0.084 ;
    END
  END n[205]
  PIN n[206]
    DIRECTION OUTPUT ;
    USE SIGNAL ;
    PORT
      LAYER M5 ;
        RECT  62.928 0 62.952 0.084 ;
    END
  END n[206]
  PIN n[207]
    DIRECTION OUTPUT ;
    USE SIGNAL ;
    PORT
      LAYER M5 ;
        RECT  63.024 0 63.048 0.084 ;
    END
  END n[207]
  PIN n[208]
    DIRECTION OUTPUT ;
    USE SIGNAL ;
    PORT
      LAYER M5 ;
        RECT  63.12 0 63.144 0.084 ;
    END
  END n[208]
  PIN n[209]
    DIRECTION OUTPUT ;
    USE SIGNAL ;
    PORT
      LAYER M5 ;
        RECT  63.216 0 63.24 0.084 ;
    END
  END n[209]
  PIN n[20]
    DIRECTION OUTPUT ;
    USE SIGNAL ;
    PORT
      LAYER M5 ;
        RECT  44.304 0 44.328 0.084 ;
    END
  END n[20]
  PIN n[210]
    DIRECTION OUTPUT ;
    USE SIGNAL ;
    PORT
      LAYER M5 ;
        RECT  63.312 0 63.336 0.084 ;
    END
  END n[210]
  PIN n[211]
    DIRECTION OUTPUT ;
    USE SIGNAL ;
    PORT
      LAYER M5 ;
        RECT  63.408 0 63.432 0.084 ;
    END
  END n[211]
  PIN n[212]
    DIRECTION OUTPUT ;
    USE SIGNAL ;
    PORT
      LAYER M5 ;
        RECT  63.504 0 63.528 0.084 ;
    END
  END n[212]
  PIN n[213]
    DIRECTION OUTPUT ;
    USE SIGNAL ;
    PORT
      LAYER M5 ;
        RECT  63.6 0 63.624 0.084 ;
    END
  END n[213]
  PIN n[214]
    DIRECTION OUTPUT ;
    USE SIGNAL ;
    PORT
      LAYER M5 ;
        RECT  63.696 0 63.72 0.084 ;
    END
  END n[214]
  PIN n[215]
    DIRECTION OUTPUT ;
    USE SIGNAL ;
    PORT
      LAYER M5 ;
        RECT  63.792 0 63.816 0.084 ;
    END
  END n[215]
  PIN n[216]
    DIRECTION OUTPUT ;
    USE SIGNAL ;
    PORT
      LAYER M5 ;
        RECT  63.888 0 63.912 0.084 ;
    END
  END n[216]
  PIN n[217]
    DIRECTION OUTPUT ;
    USE SIGNAL ;
    PORT
      LAYER M5 ;
        RECT  63.984 0 64.008 0.084 ;
    END
  END n[217]
  PIN n[218]
    DIRECTION OUTPUT ;
    USE SIGNAL ;
    PORT
      LAYER M5 ;
        RECT  64.08 0 64.104 0.084 ;
    END
  END n[218]
  PIN n[219]
    DIRECTION OUTPUT ;
    USE SIGNAL ;
    PORT
      LAYER M5 ;
        RECT  64.176 0 64.2 0.084 ;
    END
  END n[219]
  PIN n[21]
    DIRECTION OUTPUT ;
    USE SIGNAL ;
    PORT
      LAYER M5 ;
        RECT  44.4 0 44.424 0.084 ;
    END
  END n[21]
  PIN n[220]
    DIRECTION OUTPUT ;
    USE SIGNAL ;
    PORT
      LAYER M5 ;
        RECT  64.272 0 64.296 0.084 ;
    END
  END n[220]
  PIN n[221]
    DIRECTION OUTPUT ;
    USE SIGNAL ;
    PORT
      LAYER M5 ;
        RECT  64.368 0 64.392 0.084 ;
    END
  END n[221]
  PIN n[222]
    DIRECTION OUTPUT ;
    USE SIGNAL ;
    PORT
      LAYER M5 ;
        RECT  48.336 0 48.36 0.084 ;
    END
  END n[222]
  PIN n[223]
    DIRECTION OUTPUT ;
    USE SIGNAL ;
    PORT
      LAYER M5 ;
        RECT  48.432 0 48.456 0.084 ;
    END
  END n[223]
  PIN n[224]
    DIRECTION OUTPUT ;
    USE SIGNAL ;
    PORT
      LAYER M5 ;
        RECT  48.528 0 48.552 0.084 ;
    END
  END n[224]
  PIN n[225]
    DIRECTION OUTPUT ;
    USE SIGNAL ;
    PORT
      LAYER M5 ;
        RECT  48.624 0 48.648 0.084 ;
    END
  END n[225]
  PIN n[226]
    DIRECTION OUTPUT ;
    USE SIGNAL ;
    PORT
      LAYER M5 ;
        RECT  48.72 0 48.744 0.084 ;
    END
  END n[226]
  PIN n[227]
    DIRECTION OUTPUT ;
    USE SIGNAL ;
    PORT
      LAYER M5 ;
        RECT  48.816 0 48.84 0.084 ;
    END
  END n[227]
  PIN n[228]
    DIRECTION OUTPUT ;
    USE SIGNAL ;
    PORT
      LAYER M5 ;
        RECT  48.912 0 48.936 0.084 ;
    END
  END n[228]
  PIN n[229]
    DIRECTION OUTPUT ;
    USE SIGNAL ;
    PORT
      LAYER M5 ;
        RECT  49.008 0 49.032 0.084 ;
    END
  END n[229]
  PIN n[22]
    DIRECTION OUTPUT ;
    USE SIGNAL ;
    PORT
      LAYER M5 ;
        RECT  44.496 0 44.52 0.084 ;
    END
  END n[22]
  PIN n[230]
    DIRECTION OUTPUT ;
    USE SIGNAL ;
    PORT
      LAYER M5 ;
        RECT  49.104 0 49.128 0.084 ;
    END
  END n[230]
  PIN n[231]
    DIRECTION OUTPUT ;
    USE SIGNAL ;
    PORT
      LAYER M5 ;
        RECT  49.2 0 49.224 0.084 ;
    END
  END n[231]
  PIN n[232]
    DIRECTION OUTPUT ;
    USE SIGNAL ;
    PORT
      LAYER M5 ;
        RECT  49.296 0 49.32 0.084 ;
    END
  END n[232]
  PIN n[233]
    DIRECTION OUTPUT ;
    USE SIGNAL ;
    PORT
      LAYER M5 ;
        RECT  49.392 0 49.416 0.084 ;
    END
  END n[233]
  PIN n[234]
    DIRECTION OUTPUT ;
    USE SIGNAL ;
    PORT
      LAYER M5 ;
        RECT  49.488 0 49.512 0.084 ;
    END
  END n[234]
  PIN n[235]
    DIRECTION OUTPUT ;
    USE SIGNAL ;
    PORT
      LAYER M5 ;
        RECT  49.584 0 49.608 0.084 ;
    END
  END n[235]
  PIN n[236]
    DIRECTION OUTPUT ;
    USE SIGNAL ;
    PORT
      LAYER M5 ;
        RECT  49.68 0 49.704 0.084 ;
    END
  END n[236]
  PIN n[237]
    DIRECTION OUTPUT ;
    USE SIGNAL ;
    PORT
      LAYER M5 ;
        RECT  49.776 0 49.8 0.084 ;
    END
  END n[237]
  PIN n[238]
    DIRECTION OUTPUT ;
    USE SIGNAL ;
    PORT
      LAYER M5 ;
        RECT  49.872 0 49.896 0.084 ;
    END
  END n[238]
  PIN n[239]
    DIRECTION OUTPUT ;
    USE SIGNAL ;
    PORT
      LAYER M5 ;
        RECT  49.968 0 49.992 0.084 ;
    END
  END n[239]
  PIN n[23]
    DIRECTION OUTPUT ;
    USE SIGNAL ;
    PORT
      LAYER M5 ;
        RECT  44.592 0 44.616 0.084 ;
    END
  END n[23]
  PIN n[240]
    DIRECTION OUTPUT ;
    USE SIGNAL ;
    PORT
      LAYER M5 ;
        RECT  50.064 0 50.088 0.084 ;
    END
  END n[240]
  PIN n[241]
    DIRECTION OUTPUT ;
    USE SIGNAL ;
    PORT
      LAYER M5 ;
        RECT  50.16 0 50.184 0.084 ;
    END
  END n[241]
  PIN n[242]
    DIRECTION OUTPUT ;
    USE SIGNAL ;
    PORT
      LAYER M5 ;
        RECT  50.256 0 50.28 0.084 ;
    END
  END n[242]
  PIN n[243]
    DIRECTION OUTPUT ;
    USE SIGNAL ;
    PORT
      LAYER M5 ;
        RECT  50.352 0 50.376 0.084 ;
    END
  END n[243]
  PIN n[244]
    DIRECTION OUTPUT ;
    USE SIGNAL ;
    PORT
      LAYER M5 ;
        RECT  50.448 0 50.472 0.084 ;
    END
  END n[244]
  PIN n[245]
    DIRECTION OUTPUT ;
    USE SIGNAL ;
    PORT
      LAYER M5 ;
        RECT  50.544 0 50.568 0.084 ;
    END
  END n[245]
  PIN n[246]
    DIRECTION OUTPUT ;
    USE SIGNAL ;
    PORT
      LAYER M5 ;
        RECT  50.64 0 50.664 0.084 ;
    END
  END n[246]
  PIN n[247]
    DIRECTION OUTPUT ;
    USE SIGNAL ;
    PORT
      LAYER M5 ;
        RECT  50.736 0 50.76 0.084 ;
    END
  END n[247]
  PIN n[248]
    DIRECTION OUTPUT ;
    USE SIGNAL ;
    PORT
      LAYER M5 ;
        RECT  50.832 0 50.856 0.084 ;
    END
  END n[248]
  PIN n[249]
    DIRECTION OUTPUT ;
    USE SIGNAL ;
    PORT
      LAYER M5 ;
        RECT  50.928 0 50.952 0.084 ;
    END
  END n[249]
  PIN n[24]
    DIRECTION OUTPUT ;
    USE SIGNAL ;
    PORT
      LAYER M5 ;
        RECT  44.688 0 44.712 0.084 ;
    END
  END n[24]
  PIN n[250]
    DIRECTION OUTPUT ;
    USE SIGNAL ;
    PORT
      LAYER M5 ;
        RECT  51.024 0 51.048 0.084 ;
    END
  END n[250]
  PIN n[251]
    DIRECTION OUTPUT ;
    USE SIGNAL ;
    PORT
      LAYER M5 ;
        RECT  51.12 0 51.144 0.084 ;
    END
  END n[251]
  PIN n[252]
    DIRECTION OUTPUT ;
    USE SIGNAL ;
    PORT
      LAYER M5 ;
        RECT  51.216 0 51.24 0.084 ;
    END
  END n[252]
  PIN n[253]
    DIRECTION OUTPUT ;
    USE SIGNAL ;
    PORT
      LAYER M5 ;
        RECT  51.312 0 51.336 0.084 ;
    END
  END n[253]
  PIN n[254]
    DIRECTION OUTPUT ;
    USE SIGNAL ;
    PORT
      LAYER M5 ;
        RECT  51.408 0 51.432 0.084 ;
    END
  END n[254]
  PIN n[255]
    DIRECTION OUTPUT ;
    USE SIGNAL ;
    PORT
      LAYER M5 ;
        RECT  51.504 0 51.528 0.084 ;
    END
  END n[255]
  PIN n[256]
    DIRECTION OUTPUT ;
    USE SIGNAL ;
    PORT
      LAYER M5 ;
        RECT  51.6 0 51.624 0.084 ;
    END
  END n[256]
  PIN n[257]
    DIRECTION OUTPUT ;
    USE SIGNAL ;
    PORT
      LAYER M5 ;
        RECT  51.696 0 51.72 0.084 ;
    END
  END n[257]
  PIN n[258]
    DIRECTION OUTPUT ;
    USE SIGNAL ;
    PORT
      LAYER M5 ;
        RECT  51.792 0 51.816 0.084 ;
    END
  END n[258]
  PIN n[259]
    DIRECTION OUTPUT ;
    USE SIGNAL ;
    PORT
      LAYER M5 ;
        RECT  51.888 0 51.912 0.084 ;
    END
  END n[259]
  PIN n[25]
    DIRECTION OUTPUT ;
    USE SIGNAL ;
    PORT
      LAYER M5 ;
        RECT  44.784 0 44.808 0.084 ;
    END
  END n[25]
  PIN n[260]
    DIRECTION OUTPUT ;
    USE SIGNAL ;
    PORT
      LAYER M5 ;
        RECT  51.984 0 52.008 0.084 ;
    END
  END n[260]
  PIN n[261]
    DIRECTION OUTPUT ;
    USE SIGNAL ;
    PORT
      LAYER M5 ;
        RECT  52.08 0 52.104 0.084 ;
    END
  END n[261]
  PIN n[262]
    DIRECTION OUTPUT ;
    USE SIGNAL ;
    PORT
      LAYER M5 ;
        RECT  52.176 0 52.2 0.084 ;
    END
  END n[262]
  PIN n[263]
    DIRECTION OUTPUT ;
    USE SIGNAL ;
    PORT
      LAYER M5 ;
        RECT  52.272 0 52.296 0.084 ;
    END
  END n[263]
  PIN n[264]
    DIRECTION OUTPUT ;
    USE SIGNAL ;
    PORT
      LAYER M5 ;
        RECT  52.368 0 52.392 0.084 ;
    END
  END n[264]
  PIN n[265]
    DIRECTION OUTPUT ;
    USE SIGNAL ;
    PORT
      LAYER M5 ;
        RECT  52.464 0 52.488 0.084 ;
    END
  END n[265]
  PIN n[266]
    DIRECTION OUTPUT ;
    USE SIGNAL ;
    PORT
      LAYER M5 ;
        RECT  52.56 0 52.584 0.084 ;
    END
  END n[266]
  PIN n[267]
    DIRECTION OUTPUT ;
    USE SIGNAL ;
    PORT
      LAYER M5 ;
        RECT  52.656 0 52.68 0.084 ;
    END
  END n[267]
  PIN n[268]
    DIRECTION OUTPUT ;
    USE SIGNAL ;
    PORT
      LAYER M5 ;
        RECT  52.752 0 52.776 0.084 ;
    END
  END n[268]
  PIN n[269]
    DIRECTION OUTPUT ;
    USE SIGNAL ;
    PORT
      LAYER M5 ;
        RECT  52.848 0 52.872 0.084 ;
    END
  END n[269]
  PIN n[26]
    DIRECTION OUTPUT ;
    USE SIGNAL ;
    PORT
      LAYER M5 ;
        RECT  44.88 0 44.904 0.084 ;
    END
  END n[26]
  PIN n[270]
    DIRECTION OUTPUT ;
    USE SIGNAL ;
    PORT
      LAYER M5 ;
        RECT  52.944 0 52.968 0.084 ;
    END
  END n[270]
  PIN n[271]
    DIRECTION OUTPUT ;
    USE SIGNAL ;
    PORT
      LAYER M5 ;
        RECT  53.04 0 53.064 0.084 ;
    END
  END n[271]
  PIN n[272]
    DIRECTION OUTPUT ;
    USE SIGNAL ;
    PORT
      LAYER M5 ;
        RECT  53.136 0 53.16 0.084 ;
    END
  END n[272]
  PIN n[273]
    DIRECTION OUTPUT ;
    USE SIGNAL ;
    PORT
      LAYER M5 ;
        RECT  53.232 0 53.256 0.084 ;
    END
  END n[273]
  PIN n[274]
    DIRECTION OUTPUT ;
    USE SIGNAL ;
    PORT
      LAYER M5 ;
        RECT  53.328 0 53.352 0.084 ;
    END
  END n[274]
  PIN n[275]
    DIRECTION OUTPUT ;
    USE SIGNAL ;
    PORT
      LAYER M5 ;
        RECT  53.424 0 53.448 0.084 ;
    END
  END n[275]
  PIN n[276]
    DIRECTION OUTPUT ;
    USE SIGNAL ;
    PORT
      LAYER M5 ;
        RECT  53.52 0 53.544 0.084 ;
    END
  END n[276]
  PIN n[277]
    DIRECTION OUTPUT ;
    USE SIGNAL ;
    PORT
      LAYER M5 ;
        RECT  53.616 0 53.64 0.084 ;
    END
  END n[277]
  PIN n[278]
    DIRECTION OUTPUT ;
    USE SIGNAL ;
    PORT
      LAYER M5 ;
        RECT  53.712 0 53.736 0.084 ;
    END
  END n[278]
  PIN n[279]
    DIRECTION OUTPUT ;
    USE SIGNAL ;
    PORT
      LAYER M5 ;
        RECT  53.808 0 53.832 0.084 ;
    END
  END n[279]
  PIN n[27]
    DIRECTION OUTPUT ;
    USE SIGNAL ;
    PORT
      LAYER M5 ;
        RECT  44.976 0 45 0.084 ;
    END
  END n[27]
  PIN n[280]
    DIRECTION OUTPUT ;
    USE SIGNAL ;
    PORT
      LAYER M5 ;
        RECT  53.904 0 53.928 0.084 ;
    END
  END n[280]
  PIN n[281]
    DIRECTION OUTPUT ;
    USE SIGNAL ;
    PORT
      LAYER M5 ;
        RECT  54 0 54.024 0.084 ;
    END
  END n[281]
  PIN n[282]
    DIRECTION OUTPUT ;
    USE SIGNAL ;
    PORT
      LAYER M5 ;
        RECT  54.096 0 54.12 0.084 ;
    END
  END n[282]
  PIN n[283]
    DIRECTION OUTPUT ;
    USE SIGNAL ;
    PORT
      LAYER M5 ;
        RECT  54.192 0 54.216 0.084 ;
    END
  END n[283]
  PIN n[284]
    DIRECTION OUTPUT ;
    USE SIGNAL ;
    PORT
      LAYER M5 ;
        RECT  54.288 0 54.312 0.084 ;
    END
  END n[284]
  PIN n[285]
    DIRECTION OUTPUT ;
    USE SIGNAL ;
    PORT
      LAYER M5 ;
        RECT  54.384 0 54.408 0.084 ;
    END
  END n[285]
  PIN n[286]
    DIRECTION OUTPUT ;
    USE SIGNAL ;
    PORT
      LAYER M5 ;
        RECT  54.48 0 54.504 0.084 ;
    END
  END n[286]
  PIN n[287]
    DIRECTION OUTPUT ;
    USE SIGNAL ;
    PORT
      LAYER M5 ;
        RECT  54.576 0 54.6 0.084 ;
    END
  END n[287]
  PIN n[288]
    DIRECTION OUTPUT ;
    USE SIGNAL ;
    PORT
      LAYER M5 ;
        RECT  54.672 0 54.696 0.084 ;
    END
  END n[288]
  PIN n[289]
    DIRECTION OUTPUT ;
    USE SIGNAL ;
    PORT
      LAYER M5 ;
        RECT  54.768 0 54.792 0.084 ;
    END
  END n[289]
  PIN n[28]
    DIRECTION OUTPUT ;
    USE SIGNAL ;
    PORT
      LAYER M5 ;
        RECT  45.072 0 45.096 0.084 ;
    END
  END n[28]
  PIN n[290]
    DIRECTION OUTPUT ;
    USE SIGNAL ;
    PORT
      LAYER M5 ;
        RECT  54.864 0 54.888 0.084 ;
    END
  END n[290]
  PIN n[291]
    DIRECTION OUTPUT ;
    USE SIGNAL ;
    PORT
      LAYER M5 ;
        RECT  54.96 0 54.984 0.084 ;
    END
  END n[291]
  PIN n[292]
    DIRECTION OUTPUT ;
    USE SIGNAL ;
    PORT
      LAYER M5 ;
        RECT  55.056 0 55.08 0.084 ;
    END
  END n[292]
  PIN n[29]
    DIRECTION OUTPUT ;
    USE SIGNAL ;
    PORT
      LAYER M5 ;
        RECT  45.168 0 45.192 0.084 ;
    END
  END n[29]
  PIN n[2]
    DIRECTION OUTPUT ;
    USE SIGNAL ;
    PORT
      LAYER M5 ;
        RECT  42.576 0 42.6 0.084 ;
    END
  END n[2]
  PIN n[30]
    DIRECTION OUTPUT ;
    USE SIGNAL ;
    PORT
      LAYER M5 ;
        RECT  58.32 0 58.344 0.084 ;
    END
  END n[30]
  PIN n[31]
    DIRECTION OUTPUT ;
    USE SIGNAL ;
    PORT
      LAYER M5 ;
        RECT  58.416 0 58.44 0.084 ;
    END
  END n[31]
  PIN n[32]
    DIRECTION OUTPUT ;
    USE SIGNAL ;
    PORT
      LAYER M5 ;
        RECT  58.512 0 58.536 0.084 ;
    END
  END n[32]
  PIN n[33]
    DIRECTION OUTPUT ;
    USE SIGNAL ;
    PORT
      LAYER M5 ;
        RECT  58.608 0 58.632 0.084 ;
    END
  END n[33]
  PIN n[34]
    DIRECTION OUTPUT ;
    USE SIGNAL ;
    PORT
      LAYER M5 ;
        RECT  58.704 0 58.728 0.084 ;
    END
  END n[34]
  PIN n[35]
    DIRECTION OUTPUT ;
    USE SIGNAL ;
    PORT
      LAYER M5 ;
        RECT  58.8 0 58.824 0.084 ;
    END
  END n[35]
  PIN n[36]
    DIRECTION OUTPUT ;
    USE SIGNAL ;
    PORT
      LAYER M5 ;
        RECT  58.896 0 58.92 0.084 ;
    END
  END n[36]
  PIN n[37]
    DIRECTION OUTPUT ;
    USE SIGNAL ;
    PORT
      LAYER M5 ;
        RECT  58.992 0 59.016 0.084 ;
    END
  END n[37]
  PIN n[38]
    DIRECTION OUTPUT ;
    USE SIGNAL ;
    PORT
      LAYER M5 ;
        RECT  59.088 0 59.112 0.084 ;
    END
  END n[38]
  PIN n[39]
    DIRECTION OUTPUT ;
    USE SIGNAL ;
    PORT
      LAYER M5 ;
        RECT  59.184 0 59.208 0.084 ;
    END
  END n[39]
  PIN n[3]
    DIRECTION OUTPUT ;
    USE SIGNAL ;
    PORT
      LAYER M5 ;
        RECT  42.672 0 42.696 0.084 ;
    END
  END n[3]
  PIN n[40]
    DIRECTION OUTPUT ;
    USE SIGNAL ;
    PORT
      LAYER M5 ;
        RECT  59.28 0 59.304 0.084 ;
    END
  END n[40]
  PIN n[41]
    DIRECTION OUTPUT ;
    USE SIGNAL ;
    PORT
      LAYER M5 ;
        RECT  59.376 0 59.4 0.084 ;
    END
  END n[41]
  PIN n[42]
    DIRECTION OUTPUT ;
    USE SIGNAL ;
    PORT
      LAYER M5 ;
        RECT  59.472 0 59.496 0.084 ;
    END
  END n[42]
  PIN n[43]
    DIRECTION OUTPUT ;
    USE SIGNAL ;
    PORT
      LAYER M5 ;
        RECT  59.568 0 59.592 0.084 ;
    END
  END n[43]
  PIN n[44]
    DIRECTION OUTPUT ;
    USE SIGNAL ;
    PORT
      LAYER M5 ;
        RECT  59.664 0 59.688 0.084 ;
    END
  END n[44]
  PIN n[45]
    DIRECTION OUTPUT ;
    USE SIGNAL ;
    PORT
      LAYER M5 ;
        RECT  59.76 0 59.784 0.084 ;
    END
  END n[45]
  PIN n[46]
    DIRECTION OUTPUT ;
    USE SIGNAL ;
    PORT
      LAYER M5 ;
        RECT  59.856 0 59.88 0.084 ;
    END
  END n[46]
  PIN n[47]
    DIRECTION OUTPUT ;
    USE SIGNAL ;
    PORT
      LAYER M5 ;
        RECT  59.952 0 59.976 0.084 ;
    END
  END n[47]
  PIN n[48]
    DIRECTION OUTPUT ;
    USE SIGNAL ;
    PORT
      LAYER M5 ;
        RECT  60.048 0 60.072 0.084 ;
    END
  END n[48]
  PIN n[49]
    DIRECTION OUTPUT ;
    USE SIGNAL ;
    PORT
      LAYER M5 ;
        RECT  60.144 0 60.168 0.084 ;
    END
  END n[49]
  PIN n[4]
    DIRECTION OUTPUT ;
    USE SIGNAL ;
    PORT
      LAYER M5 ;
        RECT  42.768 0 42.792 0.084 ;
    END
  END n[4]
  PIN n[50]
    DIRECTION OUTPUT ;
    USE SIGNAL ;
    PORT
      LAYER M5 ;
        RECT  60.24 0 60.264 0.084 ;
    END
  END n[50]
  PIN n[51]
    DIRECTION OUTPUT ;
    USE SIGNAL ;
    PORT
      LAYER M5 ;
        RECT  60.336 0 60.36 0.084 ;
    END
  END n[51]
  PIN n[52]
    DIRECTION OUTPUT ;
    USE SIGNAL ;
    PORT
      LAYER M5 ;
        RECT  60.432 0 60.456 0.084 ;
    END
  END n[52]
  PIN n[53]
    DIRECTION OUTPUT ;
    USE SIGNAL ;
    PORT
      LAYER M5 ;
        RECT  60.528 0 60.552 0.084 ;
    END
  END n[53]
  PIN n[54]
    DIRECTION OUTPUT ;
    USE SIGNAL ;
    PORT
      LAYER M5 ;
        RECT  60.624 0 60.648 0.084 ;
    END
  END n[54]
  PIN n[55]
    DIRECTION OUTPUT ;
    USE SIGNAL ;
    PORT
      LAYER M5 ;
        RECT  60.72 0 60.744 0.084 ;
    END
  END n[55]
  PIN n[56]
    DIRECTION OUTPUT ;
    USE SIGNAL ;
    PORT
      LAYER M5 ;
        RECT  60.816 0 60.84 0.084 ;
    END
  END n[56]
  PIN n[57]
    DIRECTION OUTPUT ;
    USE SIGNAL ;
    PORT
      LAYER M5 ;
        RECT  60.912 0 60.936 0.084 ;
    END
  END n[57]
  PIN n[58]
    DIRECTION OUTPUT ;
    USE SIGNAL ;
    PORT
      LAYER M5 ;
        RECT  61.008 0 61.032 0.084 ;
    END
  END n[58]
  PIN n[59]
    DIRECTION OUTPUT ;
    USE SIGNAL ;
    PORT
      LAYER M5 ;
        RECT  61.104 0 61.128 0.084 ;
    END
  END n[59]
  PIN n[5]
    DIRECTION OUTPUT ;
    USE SIGNAL ;
    PORT
      LAYER M5 ;
        RECT  42.864 0 42.888 0.084 ;
    END
  END n[5]
  PIN n[60]
    DIRECTION OUTPUT ;
    USE SIGNAL ;
    PORT
      LAYER M5 ;
        RECT  61.2 0 61.224 0.084 ;
    END
  END n[60]
  PIN n[61]
    DIRECTION OUTPUT ;
    USE SIGNAL ;
    PORT
      LAYER M5 ;
        RECT  61.296 0 61.32 0.084 ;
    END
  END n[61]
  PIN n[62]
    DIRECTION OUTPUT ;
    USE SIGNAL ;
    PORT
      LAYER M5 ;
        RECT  64.464 0 64.488 0.084 ;
    END
  END n[62]
  PIN n[63]
    DIRECTION OUTPUT ;
    USE SIGNAL ;
    PORT
      LAYER M5 ;
        RECT  64.56 0 64.584 0.084 ;
    END
  END n[63]
  PIN n[64]
    DIRECTION OUTPUT ;
    USE SIGNAL ;
    PORT
      LAYER M5 ;
        RECT  64.656 0 64.68 0.084 ;
    END
  END n[64]
  PIN n[65]
    DIRECTION OUTPUT ;
    USE SIGNAL ;
    PORT
      LAYER M5 ;
        RECT  64.752 0 64.776 0.084 ;
    END
  END n[65]
  PIN n[66]
    DIRECTION OUTPUT ;
    USE SIGNAL ;
    PORT
      LAYER M5 ;
        RECT  64.848 0 64.872 0.084 ;
    END
  END n[66]
  PIN n[67]
    DIRECTION OUTPUT ;
    USE SIGNAL ;
    PORT
      LAYER M5 ;
        RECT  64.944 0 64.968 0.084 ;
    END
  END n[67]
  PIN n[68]
    DIRECTION OUTPUT ;
    USE SIGNAL ;
    PORT
      LAYER M5 ;
        RECT  65.04 0 65.064 0.084 ;
    END
  END n[68]
  PIN n[69]
    DIRECTION OUTPUT ;
    USE SIGNAL ;
    PORT
      LAYER M5 ;
        RECT  65.136 0 65.16 0.084 ;
    END
  END n[69]
  PIN n[6]
    DIRECTION OUTPUT ;
    USE SIGNAL ;
    PORT
      LAYER M5 ;
        RECT  42.96 0 42.984 0.084 ;
    END
  END n[6]
  PIN n[70]
    DIRECTION OUTPUT ;
    USE SIGNAL ;
    PORT
      LAYER M5 ;
        RECT  65.232 0 65.256 0.084 ;
    END
  END n[70]
  PIN n[71]
    DIRECTION OUTPUT ;
    USE SIGNAL ;
    PORT
      LAYER M5 ;
        RECT  65.328 0 65.352 0.084 ;
    END
  END n[71]
  PIN n[72]
    DIRECTION OUTPUT ;
    USE SIGNAL ;
    PORT
      LAYER M5 ;
        RECT  65.424 0 65.448 0.084 ;
    END
  END n[72]
  PIN n[73]
    DIRECTION OUTPUT ;
    USE SIGNAL ;
    PORT
      LAYER M5 ;
        RECT  65.52 0 65.544 0.084 ;
    END
  END n[73]
  PIN n[74]
    DIRECTION OUTPUT ;
    USE SIGNAL ;
    PORT
      LAYER M5 ;
        RECT  65.616 0 65.64 0.084 ;
    END
  END n[74]
  PIN n[75]
    DIRECTION OUTPUT ;
    USE SIGNAL ;
    PORT
      LAYER M5 ;
        RECT  65.712 0 65.736 0.084 ;
    END
  END n[75]
  PIN n[76]
    DIRECTION OUTPUT ;
    USE SIGNAL ;
    PORT
      LAYER M5 ;
        RECT  65.808 0 65.832 0.084 ;
    END
  END n[76]
  PIN n[77]
    DIRECTION OUTPUT ;
    USE SIGNAL ;
    PORT
      LAYER M5 ;
        RECT  65.904 0 65.928 0.084 ;
    END
  END n[77]
  PIN n[78]
    DIRECTION OUTPUT ;
    USE SIGNAL ;
    PORT
      LAYER M5 ;
        RECT  66 0 66.024 0.084 ;
    END
  END n[78]
  PIN n[79]
    DIRECTION OUTPUT ;
    USE SIGNAL ;
    PORT
      LAYER M5 ;
        RECT  66.096 0 66.12 0.084 ;
    END
  END n[79]
  PIN n[7]
    DIRECTION OUTPUT ;
    USE SIGNAL ;
    PORT
      LAYER M5 ;
        RECT  43.056 0 43.08 0.084 ;
    END
  END n[7]
  PIN n[80]
    DIRECTION OUTPUT ;
    USE SIGNAL ;
    PORT
      LAYER M5 ;
        RECT  66.192 0 66.216 0.084 ;
    END
  END n[80]
  PIN n[81]
    DIRECTION OUTPUT ;
    USE SIGNAL ;
    PORT
      LAYER M5 ;
        RECT  66.288 0 66.312 0.084 ;
    END
  END n[81]
  PIN n[82]
    DIRECTION OUTPUT ;
    USE SIGNAL ;
    PORT
      LAYER M5 ;
        RECT  66.384 0 66.408 0.084 ;
    END
  END n[82]
  PIN n[83]
    DIRECTION OUTPUT ;
    USE SIGNAL ;
    PORT
      LAYER M5 ;
        RECT  66.48 0 66.504 0.084 ;
    END
  END n[83]
  PIN n[84]
    DIRECTION OUTPUT ;
    USE SIGNAL ;
    PORT
      LAYER M5 ;
        RECT  66.576 0 66.6 0.084 ;
    END
  END n[84]
  PIN n[85]
    DIRECTION OUTPUT ;
    USE SIGNAL ;
    PORT
      LAYER M5 ;
        RECT  66.672 0 66.696 0.084 ;
    END
  END n[85]
  PIN n[86]
    DIRECTION OUTPUT ;
    USE SIGNAL ;
    PORT
      LAYER M5 ;
        RECT  66.768 0 66.792 0.084 ;
    END
  END n[86]
  PIN n[87]
    DIRECTION OUTPUT ;
    USE SIGNAL ;
    PORT
      LAYER M5 ;
        RECT  66.864 0 66.888 0.084 ;
    END
  END n[87]
  PIN n[88]
    DIRECTION OUTPUT ;
    USE SIGNAL ;
    PORT
      LAYER M5 ;
        RECT  66.96 0 66.984 0.084 ;
    END
  END n[88]
  PIN n[89]
    DIRECTION OUTPUT ;
    USE SIGNAL ;
    PORT
      LAYER M5 ;
        RECT  67.056 0 67.08 0.084 ;
    END
  END n[89]
  PIN n[8]
    DIRECTION OUTPUT ;
    USE SIGNAL ;
    PORT
      LAYER M5 ;
        RECT  43.152 0 43.176 0.084 ;
    END
  END n[8]
  PIN n[90]
    DIRECTION OUTPUT ;
    USE SIGNAL ;
    PORT
      LAYER M5 ;
        RECT  67.152 0 67.176 0.084 ;
    END
  END n[90]
  PIN n[91]
    DIRECTION OUTPUT ;
    USE SIGNAL ;
    PORT
      LAYER M5 ;
        RECT  67.248 0 67.272 0.084 ;
    END
  END n[91]
  PIN n[92]
    DIRECTION OUTPUT ;
    USE SIGNAL ;
    PORT
      LAYER M5 ;
        RECT  67.344 0 67.368 0.084 ;
    END
  END n[92]
  PIN n[93]
    DIRECTION OUTPUT ;
    USE SIGNAL ;
    PORT
      LAYER M5 ;
        RECT  67.44 0 67.464 0.084 ;
    END
  END n[93]
  PIN n[94]
    DIRECTION OUTPUT ;
    USE SIGNAL ;
    PORT
      LAYER M5 ;
        RECT  70.608 0 70.632 0.084 ;
    END
  END n[94]
  PIN n[95]
    DIRECTION OUTPUT ;
    USE SIGNAL ;
    PORT
      LAYER M5 ;
        RECT  70.704 0 70.728 0.084 ;
    END
  END n[95]
  PIN n[96]
    DIRECTION OUTPUT ;
    USE SIGNAL ;
    PORT
      LAYER M5 ;
        RECT  70.8 0 70.824 0.084 ;
    END
  END n[96]
  PIN n[97]
    DIRECTION OUTPUT ;
    USE SIGNAL ;
    PORT
      LAYER M5 ;
        RECT  70.896 0 70.92 0.084 ;
    END
  END n[97]
  PIN n[98]
    DIRECTION OUTPUT ;
    USE SIGNAL ;
    PORT
      LAYER M5 ;
        RECT  70.992 0 71.016 0.084 ;
    END
  END n[98]
  PIN n[99]
    DIRECTION OUTPUT ;
    USE SIGNAL ;
    PORT
      LAYER M5 ;
        RECT  71.088 0 71.112 0.084 ;
    END
  END n[99]
  PIN n[9]
    DIRECTION OUTPUT ;
    USE SIGNAL ;
    PORT
      LAYER M5 ;
        RECT  43.248 0 43.272 0.084 ;
    END
  END n[9]
  PIN rst_n
    DIRECTION INPUT ;
    USE SIGNAL ;
    PORT
      LAYER M4 ;
        RECT  129.516 97.008 129.6 97.032 ;
    END
  END rst_n
  PIN w[0]
    DIRECTION OUTPUT ;
    USE SIGNAL ;
    PORT
      LAYER M5 ;
        RECT  55.152 0 55.176 0.084 ;
    END
  END w[0]
  PIN w[100]
    DIRECTION OUTPUT ;
    USE SIGNAL ;
    PORT
      LAYER M5 ;
        RECT  87.792 0 87.816 0.084 ;
    END
  END w[100]
  PIN w[101]
    DIRECTION OUTPUT ;
    USE SIGNAL ;
    PORT
      LAYER M5 ;
        RECT  87.888 0 87.912 0.084 ;
    END
  END w[101]
  PIN w[102]
    DIRECTION OUTPUT ;
    USE SIGNAL ;
    PORT
      LAYER M5 ;
        RECT  87.984 0 88.008 0.084 ;
    END
  END w[102]
  PIN w[103]
    DIRECTION OUTPUT ;
    USE SIGNAL ;
    PORT
      LAYER M5 ;
        RECT  88.08 0 88.104 0.084 ;
    END
  END w[103]
  PIN w[104]
    DIRECTION OUTPUT ;
    USE SIGNAL ;
    PORT
      LAYER M5 ;
        RECT  88.176 0 88.2 0.084 ;
    END
  END w[104]
  PIN w[105]
    DIRECTION OUTPUT ;
    USE SIGNAL ;
    PORT
      LAYER M5 ;
        RECT  88.272 0 88.296 0.084 ;
    END
  END w[105]
  PIN w[106]
    DIRECTION OUTPUT ;
    USE SIGNAL ;
    PORT
      LAYER M5 ;
        RECT  88.368 0 88.392 0.084 ;
    END
  END w[106]
  PIN w[107]
    DIRECTION OUTPUT ;
    USE SIGNAL ;
    PORT
      LAYER M5 ;
        RECT  88.464 0 88.488 0.084 ;
    END
  END w[107]
  PIN w[108]
    DIRECTION OUTPUT ;
    USE SIGNAL ;
    PORT
      LAYER M5 ;
        RECT  88.56 0 88.584 0.084 ;
    END
  END w[108]
  PIN w[109]
    DIRECTION OUTPUT ;
    USE SIGNAL ;
    PORT
      LAYER M5 ;
        RECT  88.656 0 88.68 0.084 ;
    END
  END w[109]
  PIN w[10]
    DIRECTION OUTPUT ;
    USE SIGNAL ;
    PORT
      LAYER M5 ;
        RECT  56.112 0 56.136 0.084 ;
    END
  END w[10]
  PIN w[110]
    DIRECTION OUTPUT ;
    USE SIGNAL ;
    PORT
      LAYER M5 ;
        RECT  88.752 0 88.776 0.084 ;
    END
  END w[110]
  PIN w[111]
    DIRECTION OUTPUT ;
    USE SIGNAL ;
    PORT
      LAYER M5 ;
        RECT  88.848 0 88.872 0.084 ;
    END
  END w[111]
  PIN w[112]
    DIRECTION OUTPUT ;
    USE SIGNAL ;
    PORT
      LAYER M5 ;
        RECT  88.944 0 88.968 0.084 ;
    END
  END w[112]
  PIN w[113]
    DIRECTION OUTPUT ;
    USE SIGNAL ;
    PORT
      LAYER M5 ;
        RECT  89.04 0 89.064 0.084 ;
    END
  END w[113]
  PIN w[114]
    DIRECTION OUTPUT ;
    USE SIGNAL ;
    PORT
      LAYER M5 ;
        RECT  89.136 0 89.16 0.084 ;
    END
  END w[114]
  PIN w[115]
    DIRECTION OUTPUT ;
    USE SIGNAL ;
    PORT
      LAYER M5 ;
        RECT  89.232 0 89.256 0.084 ;
    END
  END w[115]
  PIN w[116]
    DIRECTION OUTPUT ;
    USE SIGNAL ;
    PORT
      LAYER M5 ;
        RECT  89.328 0 89.352 0.084 ;
    END
  END w[116]
  PIN w[117]
    DIRECTION OUTPUT ;
    USE SIGNAL ;
    PORT
      LAYER M5 ;
        RECT  89.424 0 89.448 0.084 ;
    END
  END w[117]
  PIN w[118]
    DIRECTION OUTPUT ;
    USE SIGNAL ;
    PORT
      LAYER M5 ;
        RECT  89.52 0 89.544 0.084 ;
    END
  END w[118]
  PIN w[119]
    DIRECTION OUTPUT ;
    USE SIGNAL ;
    PORT
      LAYER M5 ;
        RECT  89.616 0 89.64 0.084 ;
    END
  END w[119]
  PIN w[11]
    DIRECTION OUTPUT ;
    USE SIGNAL ;
    PORT
      LAYER M5 ;
        RECT  56.208 0 56.232 0.084 ;
    END
  END w[11]
  PIN w[120]
    DIRECTION OUTPUT ;
    USE SIGNAL ;
    PORT
      LAYER M5 ;
        RECT  89.712 0 89.736 0.084 ;
    END
  END w[120]
  PIN w[121]
    DIRECTION OUTPUT ;
    USE SIGNAL ;
    PORT
      LAYER M5 ;
        RECT  80.592 0 80.616 0.084 ;
    END
  END w[121]
  PIN w[122]
    DIRECTION OUTPUT ;
    USE SIGNAL ;
    PORT
      LAYER M5 ;
        RECT  80.688 0 80.712 0.084 ;
    END
  END w[122]
  PIN w[123]
    DIRECTION OUTPUT ;
    USE SIGNAL ;
    PORT
      LAYER M5 ;
        RECT  80.784 0 80.808 0.084 ;
    END
  END w[123]
  PIN w[124]
    DIRECTION OUTPUT ;
    USE SIGNAL ;
    PORT
      LAYER M5 ;
        RECT  80.88 0 80.904 0.084 ;
    END
  END w[124]
  PIN w[125]
    DIRECTION OUTPUT ;
    USE SIGNAL ;
    PORT
      LAYER M5 ;
        RECT  80.976 0 81 0.084 ;
    END
  END w[125]
  PIN w[126]
    DIRECTION OUTPUT ;
    USE SIGNAL ;
    PORT
      LAYER M5 ;
        RECT  81.072 0 81.096 0.084 ;
    END
  END w[126]
  PIN w[127]
    DIRECTION OUTPUT ;
    USE SIGNAL ;
    PORT
      LAYER M5 ;
        RECT  81.168 0 81.192 0.084 ;
    END
  END w[127]
  PIN w[128]
    DIRECTION OUTPUT ;
    USE SIGNAL ;
    PORT
      LAYER M5 ;
        RECT  81.264 0 81.288 0.084 ;
    END
  END w[128]
  PIN w[129]
    DIRECTION OUTPUT ;
    USE SIGNAL ;
    PORT
      LAYER M5 ;
        RECT  81.36 0 81.384 0.084 ;
    END
  END w[129]
  PIN w[12]
    DIRECTION OUTPUT ;
    USE SIGNAL ;
    PORT
      LAYER M5 ;
        RECT  56.304 0 56.328 0.084 ;
    END
  END w[12]
  PIN w[130]
    DIRECTION OUTPUT ;
    USE SIGNAL ;
    PORT
      LAYER M5 ;
        RECT  81.456 0 81.48 0.084 ;
    END
  END w[130]
  PIN w[131]
    DIRECTION OUTPUT ;
    USE SIGNAL ;
    PORT
      LAYER M5 ;
        RECT  81.552 0 81.576 0.084 ;
    END
  END w[131]
  PIN w[132]
    DIRECTION OUTPUT ;
    USE SIGNAL ;
    PORT
      LAYER M5 ;
        RECT  81.648 0 81.672 0.084 ;
    END
  END w[132]
  PIN w[133]
    DIRECTION OUTPUT ;
    USE SIGNAL ;
    PORT
      LAYER M5 ;
        RECT  81.744 0 81.768 0.084 ;
    END
  END w[133]
  PIN w[134]
    DIRECTION OUTPUT ;
    USE SIGNAL ;
    PORT
      LAYER M5 ;
        RECT  81.84 0 81.864 0.084 ;
    END
  END w[134]
  PIN w[135]
    DIRECTION OUTPUT ;
    USE SIGNAL ;
    PORT
      LAYER M5 ;
        RECT  81.936 0 81.96 0.084 ;
    END
  END w[135]
  PIN w[136]
    DIRECTION OUTPUT ;
    USE SIGNAL ;
    PORT
      LAYER M5 ;
        RECT  82.032 0 82.056 0.084 ;
    END
  END w[136]
  PIN w[137]
    DIRECTION OUTPUT ;
    USE SIGNAL ;
    PORT
      LAYER M5 ;
        RECT  82.128 0 82.152 0.084 ;
    END
  END w[137]
  PIN w[138]
    DIRECTION OUTPUT ;
    USE SIGNAL ;
    PORT
      LAYER M5 ;
        RECT  82.224 0 82.248 0.084 ;
    END
  END w[138]
  PIN w[139]
    DIRECTION OUTPUT ;
    USE SIGNAL ;
    PORT
      LAYER M5 ;
        RECT  82.32 0 82.344 0.084 ;
    END
  END w[139]
  PIN w[13]
    DIRECTION OUTPUT ;
    USE SIGNAL ;
    PORT
      LAYER M5 ;
        RECT  56.4 0 56.424 0.084 ;
    END
  END w[13]
  PIN w[140]
    DIRECTION OUTPUT ;
    USE SIGNAL ;
    PORT
      LAYER M5 ;
        RECT  82.416 0 82.44 0.084 ;
    END
  END w[140]
  PIN w[141]
    DIRECTION OUTPUT ;
    USE SIGNAL ;
    PORT
      LAYER M5 ;
        RECT  82.512 0 82.536 0.084 ;
    END
  END w[141]
  PIN w[142]
    DIRECTION OUTPUT ;
    USE SIGNAL ;
    PORT
      LAYER M5 ;
        RECT  82.608 0 82.632 0.084 ;
    END
  END w[142]
  PIN w[143]
    DIRECTION OUTPUT ;
    USE SIGNAL ;
    PORT
      LAYER M5 ;
        RECT  82.704 0 82.728 0.084 ;
    END
  END w[143]
  PIN w[144]
    DIRECTION OUTPUT ;
    USE SIGNAL ;
    PORT
      LAYER M5 ;
        RECT  82.8 0 82.824 0.084 ;
    END
  END w[144]
  PIN w[145]
    DIRECTION OUTPUT ;
    USE SIGNAL ;
    PORT
      LAYER M5 ;
        RECT  82.896 0 82.92 0.084 ;
    END
  END w[145]
  PIN w[146]
    DIRECTION OUTPUT ;
    USE SIGNAL ;
    PORT
      LAYER M5 ;
        RECT  82.992 0 83.016 0.084 ;
    END
  END w[146]
  PIN w[147]
    DIRECTION OUTPUT ;
    USE SIGNAL ;
    PORT
      LAYER M5 ;
        RECT  83.088 0 83.112 0.084 ;
    END
  END w[147]
  PIN w[148]
    DIRECTION OUTPUT ;
    USE SIGNAL ;
    PORT
      LAYER M5 ;
        RECT  83.184 0 83.208 0.084 ;
    END
  END w[148]
  PIN w[149]
    DIRECTION OUTPUT ;
    USE SIGNAL ;
    PORT
      LAYER M5 ;
        RECT  83.28 0 83.304 0.084 ;
    END
  END w[149]
  PIN w[14]
    DIRECTION OUTPUT ;
    USE SIGNAL ;
    PORT
      LAYER M5 ;
        RECT  56.496 0 56.52 0.084 ;
    END
  END w[14]
  PIN w[150]
    DIRECTION OUTPUT ;
    USE SIGNAL ;
    PORT
      LAYER M5 ;
        RECT  83.376 0 83.4 0.084 ;
    END
  END w[150]
  PIN w[151]
    DIRECTION OUTPUT ;
    USE SIGNAL ;
    PORT
      LAYER M5 ;
        RECT  83.472 0 83.496 0.084 ;
    END
  END w[151]
  PIN w[152]
    DIRECTION OUTPUT ;
    USE SIGNAL ;
    PORT
      LAYER M5 ;
        RECT  83.568 0 83.592 0.084 ;
    END
  END w[152]
  PIN w[153]
    DIRECTION OUTPUT ;
    USE SIGNAL ;
    PORT
      LAYER M5 ;
        RECT  89.808 0 89.832 0.084 ;
    END
  END w[153]
  PIN w[154]
    DIRECTION OUTPUT ;
    USE SIGNAL ;
    PORT
      LAYER M5 ;
        RECT  89.904 0 89.928 0.084 ;
    END
  END w[154]
  PIN w[155]
    DIRECTION OUTPUT ;
    USE SIGNAL ;
    PORT
      LAYER M5 ;
        RECT  90 0 90.024 0.084 ;
    END
  END w[155]
  PIN w[156]
    DIRECTION OUTPUT ;
    USE SIGNAL ;
    PORT
      LAYER M5 ;
        RECT  90.096 0 90.12 0.084 ;
    END
  END w[156]
  PIN w[157]
    DIRECTION OUTPUT ;
    USE SIGNAL ;
    PORT
      LAYER M5 ;
        RECT  90.192 0 90.216 0.084 ;
    END
  END w[157]
  PIN w[158]
    DIRECTION OUTPUT ;
    USE SIGNAL ;
    PORT
      LAYER M5 ;
        RECT  90.288 0 90.312 0.084 ;
    END
  END w[158]
  PIN w[159]
    DIRECTION OUTPUT ;
    USE SIGNAL ;
    PORT
      LAYER M5 ;
        RECT  90.384 0 90.408 0.084 ;
    END
  END w[159]
  PIN w[15]
    DIRECTION OUTPUT ;
    USE SIGNAL ;
    PORT
      LAYER M5 ;
        RECT  56.592 0 56.616 0.084 ;
    END
  END w[15]
  PIN w[160]
    DIRECTION OUTPUT ;
    USE SIGNAL ;
    PORT
      LAYER M5 ;
        RECT  90.48 0 90.504 0.084 ;
    END
  END w[160]
  PIN w[161]
    DIRECTION OUTPUT ;
    USE SIGNAL ;
    PORT
      LAYER M5 ;
        RECT  90.576 0 90.6 0.084 ;
    END
  END w[161]
  PIN w[162]
    DIRECTION OUTPUT ;
    USE SIGNAL ;
    PORT
      LAYER M5 ;
        RECT  90.672 0 90.696 0.084 ;
    END
  END w[162]
  PIN w[163]
    DIRECTION OUTPUT ;
    USE SIGNAL ;
    PORT
      LAYER M5 ;
        RECT  90.768 0 90.792 0.084 ;
    END
  END w[163]
  PIN w[164]
    DIRECTION OUTPUT ;
    USE SIGNAL ;
    PORT
      LAYER M5 ;
        RECT  90.864 0 90.888 0.084 ;
    END
  END w[164]
  PIN w[165]
    DIRECTION OUTPUT ;
    USE SIGNAL ;
    PORT
      LAYER M5 ;
        RECT  90.96 0 90.984 0.084 ;
    END
  END w[165]
  PIN w[166]
    DIRECTION OUTPUT ;
    USE SIGNAL ;
    PORT
      LAYER M5 ;
        RECT  91.056 0 91.08 0.084 ;
    END
  END w[166]
  PIN w[167]
    DIRECTION OUTPUT ;
    USE SIGNAL ;
    PORT
      LAYER M5 ;
        RECT  91.152 0 91.176 0.084 ;
    END
  END w[167]
  PIN w[168]
    DIRECTION OUTPUT ;
    USE SIGNAL ;
    PORT
      LAYER M5 ;
        RECT  91.248 0 91.272 0.084 ;
    END
  END w[168]
  PIN w[169]
    DIRECTION OUTPUT ;
    USE SIGNAL ;
    PORT
      LAYER M5 ;
        RECT  91.344 0 91.368 0.084 ;
    END
  END w[169]
  PIN w[16]
    DIRECTION OUTPUT ;
    USE SIGNAL ;
    PORT
      LAYER M5 ;
        RECT  56.688 0 56.712 0.084 ;
    END
  END w[16]
  PIN w[170]
    DIRECTION OUTPUT ;
    USE SIGNAL ;
    PORT
      LAYER M5 ;
        RECT  91.44 0 91.464 0.084 ;
    END
  END w[170]
  PIN w[171]
    DIRECTION OUTPUT ;
    USE SIGNAL ;
    PORT
      LAYER M5 ;
        RECT  91.536 0 91.56 0.084 ;
    END
  END w[171]
  PIN w[172]
    DIRECTION OUTPUT ;
    USE SIGNAL ;
    PORT
      LAYER M5 ;
        RECT  91.632 0 91.656 0.084 ;
    END
  END w[172]
  PIN w[173]
    DIRECTION OUTPUT ;
    USE SIGNAL ;
    PORT
      LAYER M5 ;
        RECT  91.728 0 91.752 0.084 ;
    END
  END w[173]
  PIN w[174]
    DIRECTION OUTPUT ;
    USE SIGNAL ;
    PORT
      LAYER M5 ;
        RECT  91.824 0 91.848 0.084 ;
    END
  END w[174]
  PIN w[175]
    DIRECTION OUTPUT ;
    USE SIGNAL ;
    PORT
      LAYER M5 ;
        RECT  91.92 0 91.944 0.084 ;
    END
  END w[175]
  PIN w[176]
    DIRECTION OUTPUT ;
    USE SIGNAL ;
    PORT
      LAYER M5 ;
        RECT  92.016 0 92.04 0.084 ;
    END
  END w[176]
  PIN w[177]
    DIRECTION OUTPUT ;
    USE SIGNAL ;
    PORT
      LAYER M5 ;
        RECT  92.112 0 92.136 0.084 ;
    END
  END w[177]
  PIN w[178]
    DIRECTION OUTPUT ;
    USE SIGNAL ;
    PORT
      LAYER M5 ;
        RECT  92.208 0 92.232 0.084 ;
    END
  END w[178]
  PIN w[179]
    DIRECTION OUTPUT ;
    USE SIGNAL ;
    PORT
      LAYER M5 ;
        RECT  92.304 0 92.328 0.084 ;
    END
  END w[179]
  PIN w[17]
    DIRECTION OUTPUT ;
    USE SIGNAL ;
    PORT
      LAYER M5 ;
        RECT  56.784 0 56.808 0.084 ;
    END
  END w[17]
  PIN w[180]
    DIRECTION OUTPUT ;
    USE SIGNAL ;
    PORT
      LAYER M5 ;
        RECT  92.4 0 92.424 0.084 ;
    END
  END w[180]
  PIN w[181]
    DIRECTION OUTPUT ;
    USE SIGNAL ;
    PORT
      LAYER M5 ;
        RECT  92.496 0 92.52 0.084 ;
    END
  END w[181]
  PIN w[182]
    DIRECTION OUTPUT ;
    USE SIGNAL ;
    PORT
      LAYER M5 ;
        RECT  92.592 0 92.616 0.084 ;
    END
  END w[182]
  PIN w[183]
    DIRECTION OUTPUT ;
    USE SIGNAL ;
    PORT
      LAYER M5 ;
        RECT  92.688 0 92.712 0.084 ;
    END
  END w[183]
  PIN w[184]
    DIRECTION OUTPUT ;
    USE SIGNAL ;
    PORT
      LAYER M5 ;
        RECT  92.784 0 92.808 0.084 ;
    END
  END w[184]
  PIN w[185]
    DIRECTION OUTPUT ;
    USE SIGNAL ;
    PORT
      LAYER M5 ;
        RECT  83.664 0 83.688 0.084 ;
    END
  END w[185]
  PIN w[186]
    DIRECTION OUTPUT ;
    USE SIGNAL ;
    PORT
      LAYER M5 ;
        RECT  83.76 0 83.784 0.084 ;
    END
  END w[186]
  PIN w[187]
    DIRECTION OUTPUT ;
    USE SIGNAL ;
    PORT
      LAYER M5 ;
        RECT  83.856 0 83.88 0.084 ;
    END
  END w[187]
  PIN w[188]
    DIRECTION OUTPUT ;
    USE SIGNAL ;
    PORT
      LAYER M5 ;
        RECT  83.952 0 83.976 0.084 ;
    END
  END w[188]
  PIN w[189]
    DIRECTION OUTPUT ;
    USE SIGNAL ;
    PORT
      LAYER M5 ;
        RECT  84.048 0 84.072 0.084 ;
    END
  END w[189]
  PIN w[18]
    DIRECTION OUTPUT ;
    USE SIGNAL ;
    PORT
      LAYER M5 ;
        RECT  56.88 0 56.904 0.084 ;
    END
  END w[18]
  PIN w[190]
    DIRECTION OUTPUT ;
    USE SIGNAL ;
    PORT
      LAYER M5 ;
        RECT  84.144 0 84.168 0.084 ;
    END
  END w[190]
  PIN w[191]
    DIRECTION OUTPUT ;
    USE SIGNAL ;
    PORT
      LAYER M5 ;
        RECT  84.24 0 84.264 0.084 ;
    END
  END w[191]
  PIN w[192]
    DIRECTION OUTPUT ;
    USE SIGNAL ;
    PORT
      LAYER M5 ;
        RECT  84.336 0 84.36 0.084 ;
    END
  END w[192]
  PIN w[193]
    DIRECTION OUTPUT ;
    USE SIGNAL ;
    PORT
      LAYER M5 ;
        RECT  84.432 0 84.456 0.084 ;
    END
  END w[193]
  PIN w[194]
    DIRECTION OUTPUT ;
    USE SIGNAL ;
    PORT
      LAYER M5 ;
        RECT  84.528 0 84.552 0.084 ;
    END
  END w[194]
  PIN w[195]
    DIRECTION OUTPUT ;
    USE SIGNAL ;
    PORT
      LAYER M5 ;
        RECT  84.624 0 84.648 0.084 ;
    END
  END w[195]
  PIN w[196]
    DIRECTION OUTPUT ;
    USE SIGNAL ;
    PORT
      LAYER M5 ;
        RECT  84.72 0 84.744 0.084 ;
    END
  END w[196]
  PIN w[197]
    DIRECTION OUTPUT ;
    USE SIGNAL ;
    PORT
      LAYER M5 ;
        RECT  84.816 0 84.84 0.084 ;
    END
  END w[197]
  PIN w[198]
    DIRECTION OUTPUT ;
    USE SIGNAL ;
    PORT
      LAYER M5 ;
        RECT  84.912 0 84.936 0.084 ;
    END
  END w[198]
  PIN w[199]
    DIRECTION OUTPUT ;
    USE SIGNAL ;
    PORT
      LAYER M5 ;
        RECT  85.008 0 85.032 0.084 ;
    END
  END w[199]
  PIN w[19]
    DIRECTION OUTPUT ;
    USE SIGNAL ;
    PORT
      LAYER M5 ;
        RECT  56.976 0 57 0.084 ;
    END
  END w[19]
  PIN w[1]
    DIRECTION OUTPUT ;
    USE SIGNAL ;
    PORT
      LAYER M5 ;
        RECT  55.248 0 55.272 0.084 ;
    END
  END w[1]
  PIN w[200]
    DIRECTION OUTPUT ;
    USE SIGNAL ;
    PORT
      LAYER M5 ;
        RECT  85.104 0 85.128 0.084 ;
    END
  END w[200]
  PIN w[201]
    DIRECTION OUTPUT ;
    USE SIGNAL ;
    PORT
      LAYER M5 ;
        RECT  85.2 0 85.224 0.084 ;
    END
  END w[201]
  PIN w[202]
    DIRECTION OUTPUT ;
    USE SIGNAL ;
    PORT
      LAYER M5 ;
        RECT  85.296 0 85.32 0.084 ;
    END
  END w[202]
  PIN w[203]
    DIRECTION OUTPUT ;
    USE SIGNAL ;
    PORT
      LAYER M5 ;
        RECT  85.392 0 85.416 0.084 ;
    END
  END w[203]
  PIN w[204]
    DIRECTION OUTPUT ;
    USE SIGNAL ;
    PORT
      LAYER M5 ;
        RECT  85.488 0 85.512 0.084 ;
    END
  END w[204]
  PIN w[205]
    DIRECTION OUTPUT ;
    USE SIGNAL ;
    PORT
      LAYER M5 ;
        RECT  85.584 0 85.608 0.084 ;
    END
  END w[205]
  PIN w[206]
    DIRECTION OUTPUT ;
    USE SIGNAL ;
    PORT
      LAYER M5 ;
        RECT  85.68 0 85.704 0.084 ;
    END
  END w[206]
  PIN w[207]
    DIRECTION OUTPUT ;
    USE SIGNAL ;
    PORT
      LAYER M5 ;
        RECT  85.776 0 85.8 0.084 ;
    END
  END w[207]
  PIN w[208]
    DIRECTION OUTPUT ;
    USE SIGNAL ;
    PORT
      LAYER M5 ;
        RECT  85.872 0 85.896 0.084 ;
    END
  END w[208]
  PIN w[209]
    DIRECTION OUTPUT ;
    USE SIGNAL ;
    PORT
      LAYER M5 ;
        RECT  85.968 0 85.992 0.084 ;
    END
  END w[209]
  PIN w[20]
    DIRECTION OUTPUT ;
    USE SIGNAL ;
    PORT
      LAYER M5 ;
        RECT  57.072 0 57.096 0.084 ;
    END
  END w[20]
  PIN w[210]
    DIRECTION OUTPUT ;
    USE SIGNAL ;
    PORT
      LAYER M5 ;
        RECT  86.064 0 86.088 0.084 ;
    END
  END w[210]
  PIN w[211]
    DIRECTION OUTPUT ;
    USE SIGNAL ;
    PORT
      LAYER M5 ;
        RECT  86.16 0 86.184 0.084 ;
    END
  END w[211]
  PIN w[212]
    DIRECTION OUTPUT ;
    USE SIGNAL ;
    PORT
      LAYER M5 ;
        RECT  86.256 0 86.28 0.084 ;
    END
  END w[212]
  PIN w[213]
    DIRECTION OUTPUT ;
    USE SIGNAL ;
    PORT
      LAYER M5 ;
        RECT  86.352 0 86.376 0.084 ;
    END
  END w[213]
  PIN w[214]
    DIRECTION OUTPUT ;
    USE SIGNAL ;
    PORT
      LAYER M5 ;
        RECT  86.448 0 86.472 0.084 ;
    END
  END w[214]
  PIN w[215]
    DIRECTION OUTPUT ;
    USE SIGNAL ;
    PORT
      LAYER M5 ;
        RECT  86.544 0 86.568 0.084 ;
    END
  END w[215]
  PIN w[216]
    DIRECTION OUTPUT ;
    USE SIGNAL ;
    PORT
      LAYER M5 ;
        RECT  86.64 0 86.664 0.084 ;
    END
  END w[216]
  PIN w[217]
    DIRECTION OUTPUT ;
    USE SIGNAL ;
    PORT
      LAYER M5 ;
        RECT  92.88 0 92.904 0.084 ;
    END
  END w[217]
  PIN w[218]
    DIRECTION OUTPUT ;
    USE SIGNAL ;
    PORT
      LAYER M5 ;
        RECT  92.976 0 93 0.084 ;
    END
  END w[218]
  PIN w[219]
    DIRECTION OUTPUT ;
    USE SIGNAL ;
    PORT
      LAYER M5 ;
        RECT  93.072 0 93.096 0.084 ;
    END
  END w[219]
  PIN w[21]
    DIRECTION OUTPUT ;
    USE SIGNAL ;
    PORT
      LAYER M5 ;
        RECT  57.168 0 57.192 0.084 ;
    END
  END w[21]
  PIN w[220]
    DIRECTION OUTPUT ;
    USE SIGNAL ;
    PORT
      LAYER M5 ;
        RECT  93.168 0 93.192 0.084 ;
    END
  END w[220]
  PIN w[221]
    DIRECTION OUTPUT ;
    USE SIGNAL ;
    PORT
      LAYER M5 ;
        RECT  93.264 0 93.288 0.084 ;
    END
  END w[221]
  PIN w[222]
    DIRECTION OUTPUT ;
    USE SIGNAL ;
    PORT
      LAYER M5 ;
        RECT  93.36 0 93.384 0.084 ;
    END
  END w[222]
  PIN w[223]
    DIRECTION OUTPUT ;
    USE SIGNAL ;
    PORT
      LAYER M5 ;
        RECT  93.456 0 93.48 0.084 ;
    END
  END w[223]
  PIN w[224]
    DIRECTION OUTPUT ;
    USE SIGNAL ;
    PORT
      LAYER M5 ;
        RECT  93.552 0 93.576 0.084 ;
    END
  END w[224]
  PIN w[225]
    DIRECTION OUTPUT ;
    USE SIGNAL ;
    PORT
      LAYER M5 ;
        RECT  93.648 0 93.672 0.084 ;
    END
  END w[225]
  PIN w[226]
    DIRECTION OUTPUT ;
    USE SIGNAL ;
    PORT
      LAYER M5 ;
        RECT  93.744 0 93.768 0.084 ;
    END
  END w[226]
  PIN w[227]
    DIRECTION OUTPUT ;
    USE SIGNAL ;
    PORT
      LAYER M5 ;
        RECT  93.84 0 93.864 0.084 ;
    END
  END w[227]
  PIN w[228]
    DIRECTION OUTPUT ;
    USE SIGNAL ;
    PORT
      LAYER M5 ;
        RECT  93.936 0 93.96 0.084 ;
    END
  END w[228]
  PIN w[229]
    DIRECTION OUTPUT ;
    USE SIGNAL ;
    PORT
      LAYER M5 ;
        RECT  94.032 0 94.056 0.084 ;
    END
  END w[229]
  PIN w[22]
    DIRECTION OUTPUT ;
    USE SIGNAL ;
    PORT
      LAYER M5 ;
        RECT  57.264 0 57.288 0.084 ;
    END
  END w[22]
  PIN w[230]
    DIRECTION OUTPUT ;
    USE SIGNAL ;
    PORT
      LAYER M5 ;
        RECT  94.128 0 94.152 0.084 ;
    END
  END w[230]
  PIN w[231]
    DIRECTION OUTPUT ;
    USE SIGNAL ;
    PORT
      LAYER M5 ;
        RECT  94.224 0 94.248 0.084 ;
    END
  END w[231]
  PIN w[232]
    DIRECTION OUTPUT ;
    USE SIGNAL ;
    PORT
      LAYER M5 ;
        RECT  94.32 0 94.344 0.084 ;
    END
  END w[232]
  PIN w[233]
    DIRECTION OUTPUT ;
    USE SIGNAL ;
    PORT
      LAYER M5 ;
        RECT  94.416 0 94.44 0.084 ;
    END
  END w[233]
  PIN w[234]
    DIRECTION OUTPUT ;
    USE SIGNAL ;
    PORT
      LAYER M5 ;
        RECT  94.512 0 94.536 0.084 ;
    END
  END w[234]
  PIN w[235]
    DIRECTION OUTPUT ;
    USE SIGNAL ;
    PORT
      LAYER M5 ;
        RECT  94.608 0 94.632 0.084 ;
    END
  END w[235]
  PIN w[236]
    DIRECTION OUTPUT ;
    USE SIGNAL ;
    PORT
      LAYER M5 ;
        RECT  94.704 0 94.728 0.084 ;
    END
  END w[236]
  PIN w[237]
    DIRECTION OUTPUT ;
    USE SIGNAL ;
    PORT
      LAYER M5 ;
        RECT  94.8 0 94.824 0.084 ;
    END
  END w[237]
  PIN w[238]
    DIRECTION OUTPUT ;
    USE SIGNAL ;
    PORT
      LAYER M5 ;
        RECT  94.896 0 94.92 0.084 ;
    END
  END w[238]
  PIN w[239]
    DIRECTION OUTPUT ;
    USE SIGNAL ;
    PORT
      LAYER M5 ;
        RECT  94.992 0 95.016 0.084 ;
    END
  END w[239]
  PIN w[23]
    DIRECTION OUTPUT ;
    USE SIGNAL ;
    PORT
      LAYER M5 ;
        RECT  57.36 0 57.384 0.084 ;
    END
  END w[23]
  PIN w[240]
    DIRECTION OUTPUT ;
    USE SIGNAL ;
    PORT
      LAYER M5 ;
        RECT  95.088 0 95.112 0.084 ;
    END
  END w[240]
  PIN w[241]
    DIRECTION OUTPUT ;
    USE SIGNAL ;
    PORT
      LAYER M5 ;
        RECT  95.184 0 95.208 0.084 ;
    END
  END w[241]
  PIN w[242]
    DIRECTION OUTPUT ;
    USE SIGNAL ;
    PORT
      LAYER M5 ;
        RECT  95.28 0 95.304 0.084 ;
    END
  END w[242]
  PIN w[243]
    DIRECTION OUTPUT ;
    USE SIGNAL ;
    PORT
      LAYER M5 ;
        RECT  95.376 0 95.4 0.084 ;
    END
  END w[243]
  PIN w[244]
    DIRECTION OUTPUT ;
    USE SIGNAL ;
    PORT
      LAYER M5 ;
        RECT  95.472 0 95.496 0.084 ;
    END
  END w[244]
  PIN w[245]
    DIRECTION OUTPUT ;
    USE SIGNAL ;
    PORT
      LAYER M5 ;
        RECT  95.568 0 95.592 0.084 ;
    END
  END w[245]
  PIN w[246]
    DIRECTION OUTPUT ;
    USE SIGNAL ;
    PORT
      LAYER M5 ;
        RECT  95.664 0 95.688 0.084 ;
    END
  END w[246]
  PIN w[247]
    DIRECTION OUTPUT ;
    USE SIGNAL ;
    PORT
      LAYER M5 ;
        RECT  95.76 0 95.784 0.084 ;
    END
  END w[247]
  PIN w[248]
    DIRECTION OUTPUT ;
    USE SIGNAL ;
    PORT
      LAYER M5 ;
        RECT  95.856 0 95.88 0.084 ;
    END
  END w[248]
  PIN w[249]
    DIRECTION OUTPUT ;
    USE SIGNAL ;
    PORT
      LAYER M5 ;
        RECT  77.52 0 77.544 0.084 ;
    END
  END w[249]
  PIN w[24]
    DIRECTION OUTPUT ;
    USE SIGNAL ;
    PORT
      LAYER M5 ;
        RECT  57.456 0 57.48 0.084 ;
    END
  END w[24]
  PIN w[250]
    DIRECTION OUTPUT ;
    USE SIGNAL ;
    PORT
      LAYER M5 ;
        RECT  77.616 0 77.64 0.084 ;
    END
  END w[250]
  PIN w[251]
    DIRECTION OUTPUT ;
    USE SIGNAL ;
    PORT
      LAYER M5 ;
        RECT  77.712 0 77.736 0.084 ;
    END
  END w[251]
  PIN w[252]
    DIRECTION OUTPUT ;
    USE SIGNAL ;
    PORT
      LAYER M5 ;
        RECT  77.808 0 77.832 0.084 ;
    END
  END w[252]
  PIN w[253]
    DIRECTION OUTPUT ;
    USE SIGNAL ;
    PORT
      LAYER M5 ;
        RECT  77.904 0 77.928 0.084 ;
    END
  END w[253]
  PIN w[254]
    DIRECTION OUTPUT ;
    USE SIGNAL ;
    PORT
      LAYER M5 ;
        RECT  78 0 78.024 0.084 ;
    END
  END w[254]
  PIN w[255]
    DIRECTION OUTPUT ;
    USE SIGNAL ;
    PORT
      LAYER M5 ;
        RECT  78.096 0 78.12 0.084 ;
    END
  END w[255]
  PIN w[256]
    DIRECTION OUTPUT ;
    USE SIGNAL ;
    PORT
      LAYER M5 ;
        RECT  78.192 0 78.216 0.084 ;
    END
  END w[256]
  PIN w[257]
    DIRECTION OUTPUT ;
    USE SIGNAL ;
    PORT
      LAYER M5 ;
        RECT  78.288 0 78.312 0.084 ;
    END
  END w[257]
  PIN w[258]
    DIRECTION OUTPUT ;
    USE SIGNAL ;
    PORT
      LAYER M5 ;
        RECT  78.384 0 78.408 0.084 ;
    END
  END w[258]
  PIN w[259]
    DIRECTION OUTPUT ;
    USE SIGNAL ;
    PORT
      LAYER M5 ;
        RECT  78.48 0 78.504 0.084 ;
    END
  END w[259]
  PIN w[25]
    DIRECTION OUTPUT ;
    USE SIGNAL ;
    PORT
      LAYER M5 ;
        RECT  45.264 0 45.288 0.084 ;
    END
  END w[25]
  PIN w[260]
    DIRECTION OUTPUT ;
    USE SIGNAL ;
    PORT
      LAYER M5 ;
        RECT  78.576 0 78.6 0.084 ;
    END
  END w[260]
  PIN w[261]
    DIRECTION OUTPUT ;
    USE SIGNAL ;
    PORT
      LAYER M5 ;
        RECT  78.672 0 78.696 0.084 ;
    END
  END w[261]
  PIN w[262]
    DIRECTION OUTPUT ;
    USE SIGNAL ;
    PORT
      LAYER M5 ;
        RECT  78.768 0 78.792 0.084 ;
    END
  END w[262]
  PIN w[263]
    DIRECTION OUTPUT ;
    USE SIGNAL ;
    PORT
      LAYER M5 ;
        RECT  78.864 0 78.888 0.084 ;
    END
  END w[263]
  PIN w[264]
    DIRECTION OUTPUT ;
    USE SIGNAL ;
    PORT
      LAYER M5 ;
        RECT  78.96 0 78.984 0.084 ;
    END
  END w[264]
  PIN w[265]
    DIRECTION OUTPUT ;
    USE SIGNAL ;
    PORT
      LAYER M5 ;
        RECT  79.056 0 79.08 0.084 ;
    END
  END w[265]
  PIN w[266]
    DIRECTION OUTPUT ;
    USE SIGNAL ;
    PORT
      LAYER M5 ;
        RECT  79.152 0 79.176 0.084 ;
    END
  END w[266]
  PIN w[267]
    DIRECTION OUTPUT ;
    USE SIGNAL ;
    PORT
      LAYER M5 ;
        RECT  79.248 0 79.272 0.084 ;
    END
  END w[267]
  PIN w[268]
    DIRECTION OUTPUT ;
    USE SIGNAL ;
    PORT
      LAYER M5 ;
        RECT  79.344 0 79.368 0.084 ;
    END
  END w[268]
  PIN w[269]
    DIRECTION OUTPUT ;
    USE SIGNAL ;
    PORT
      LAYER M5 ;
        RECT  79.44 0 79.464 0.084 ;
    END
  END w[269]
  PIN w[26]
    DIRECTION OUTPUT ;
    USE SIGNAL ;
    PORT
      LAYER M5 ;
        RECT  45.36 0 45.384 0.084 ;
    END
  END w[26]
  PIN w[270]
    DIRECTION OUTPUT ;
    USE SIGNAL ;
    PORT
      LAYER M5 ;
        RECT  79.536 0 79.56 0.084 ;
    END
  END w[270]
  PIN w[271]
    DIRECTION OUTPUT ;
    USE SIGNAL ;
    PORT
      LAYER M5 ;
        RECT  79.632 0 79.656 0.084 ;
    END
  END w[271]
  PIN w[272]
    DIRECTION OUTPUT ;
    USE SIGNAL ;
    PORT
      LAYER M5 ;
        RECT  79.728 0 79.752 0.084 ;
    END
  END w[272]
  PIN w[273]
    DIRECTION OUTPUT ;
    USE SIGNAL ;
    PORT
      LAYER M5 ;
        RECT  79.824 0 79.848 0.084 ;
    END
  END w[273]
  PIN w[274]
    DIRECTION OUTPUT ;
    USE SIGNAL ;
    PORT
      LAYER M5 ;
        RECT  79.92 0 79.944 0.084 ;
    END
  END w[274]
  PIN w[275]
    DIRECTION OUTPUT ;
    USE SIGNAL ;
    PORT
      LAYER M5 ;
        RECT  80.016 0 80.04 0.084 ;
    END
  END w[275]
  PIN w[276]
    DIRECTION OUTPUT ;
    USE SIGNAL ;
    PORT
      LAYER M5 ;
        RECT  80.112 0 80.136 0.084 ;
    END
  END w[276]
  PIN w[277]
    DIRECTION OUTPUT ;
    USE SIGNAL ;
    PORT
      LAYER M5 ;
        RECT  80.208 0 80.232 0.084 ;
    END
  END w[277]
  PIN w[278]
    DIRECTION OUTPUT ;
    USE SIGNAL ;
    PORT
      LAYER M5 ;
        RECT  80.304 0 80.328 0.084 ;
    END
  END w[278]
  PIN w[279]
    DIRECTION OUTPUT ;
    USE SIGNAL ;
    PORT
      LAYER M5 ;
        RECT  80.4 0 80.424 0.084 ;
    END
  END w[279]
  PIN w[27]
    DIRECTION OUTPUT ;
    USE SIGNAL ;
    PORT
      LAYER M5 ;
        RECT  45.456 0 45.48 0.084 ;
    END
  END w[27]
  PIN w[280]
    DIRECTION OUTPUT ;
    USE SIGNAL ;
    PORT
      LAYER M5 ;
        RECT  80.496 0 80.52 0.084 ;
    END
  END w[280]
  PIN w[281]
    DIRECTION OUTPUT ;
    USE SIGNAL ;
    PORT
      LAYER M5 ;
        RECT  37.2 0 37.224 0.084 ;
    END
  END w[281]
  PIN w[282]
    DIRECTION OUTPUT ;
    USE SIGNAL ;
    PORT
      LAYER M5 ;
        RECT  37.296 0 37.32 0.084 ;
    END
  END w[282]
  PIN w[283]
    DIRECTION OUTPUT ;
    USE SIGNAL ;
    PORT
      LAYER M5 ;
        RECT  37.392 0 37.416 0.084 ;
    END
  END w[283]
  PIN w[284]
    DIRECTION OUTPUT ;
    USE SIGNAL ;
    PORT
      LAYER M5 ;
        RECT  37.488 0 37.512 0.084 ;
    END
  END w[284]
  PIN w[285]
    DIRECTION OUTPUT ;
    USE SIGNAL ;
    PORT
      LAYER M5 ;
        RECT  37.584 0 37.608 0.084 ;
    END
  END w[285]
  PIN w[286]
    DIRECTION OUTPUT ;
    USE SIGNAL ;
    PORT
      LAYER M5 ;
        RECT  37.68 0 37.704 0.084 ;
    END
  END w[286]
  PIN w[287]
    DIRECTION OUTPUT ;
    USE SIGNAL ;
    PORT
      LAYER M5 ;
        RECT  37.776 0 37.8 0.084 ;
    END
  END w[287]
  PIN w[288]
    DIRECTION OUTPUT ;
    USE SIGNAL ;
    PORT
      LAYER M5 ;
        RECT  37.872 0 37.896 0.084 ;
    END
  END w[288]
  PIN w[289]
    DIRECTION OUTPUT ;
    USE SIGNAL ;
    PORT
      LAYER M5 ;
        RECT  37.968 0 37.992 0.084 ;
    END
  END w[289]
  PIN w[28]
    DIRECTION OUTPUT ;
    USE SIGNAL ;
    PORT
      LAYER M5 ;
        RECT  45.552 0 45.576 0.084 ;
    END
  END w[28]
  PIN w[29]
    DIRECTION OUTPUT ;
    USE SIGNAL ;
    PORT
      LAYER M5 ;
        RECT  45.648 0 45.672 0.084 ;
    END
  END w[29]
  PIN w[2]
    DIRECTION OUTPUT ;
    USE SIGNAL ;
    PORT
      LAYER M5 ;
        RECT  55.344 0 55.368 0.084 ;
    END
  END w[2]
  PIN w[30]
    DIRECTION OUTPUT ;
    USE SIGNAL ;
    PORT
      LAYER M5 ;
        RECT  45.744 0 45.768 0.084 ;
    END
  END w[30]
  PIN w[31]
    DIRECTION OUTPUT ;
    USE SIGNAL ;
    PORT
      LAYER M5 ;
        RECT  45.84 0 45.864 0.084 ;
    END
  END w[31]
  PIN w[32]
    DIRECTION OUTPUT ;
    USE SIGNAL ;
    PORT
      LAYER M5 ;
        RECT  45.936 0 45.96 0.084 ;
    END
  END w[32]
  PIN w[33]
    DIRECTION OUTPUT ;
    USE SIGNAL ;
    PORT
      LAYER M5 ;
        RECT  46.032 0 46.056 0.084 ;
    END
  END w[33]
  PIN w[34]
    DIRECTION OUTPUT ;
    USE SIGNAL ;
    PORT
      LAYER M5 ;
        RECT  46.128 0 46.152 0.084 ;
    END
  END w[34]
  PIN w[35]
    DIRECTION OUTPUT ;
    USE SIGNAL ;
    PORT
      LAYER M5 ;
        RECT  46.224 0 46.248 0.084 ;
    END
  END w[35]
  PIN w[36]
    DIRECTION OUTPUT ;
    USE SIGNAL ;
    PORT
      LAYER M5 ;
        RECT  46.32 0 46.344 0.084 ;
    END
  END w[36]
  PIN w[37]
    DIRECTION OUTPUT ;
    USE SIGNAL ;
    PORT
      LAYER M5 ;
        RECT  46.416 0 46.44 0.084 ;
    END
  END w[37]
  PIN w[38]
    DIRECTION OUTPUT ;
    USE SIGNAL ;
    PORT
      LAYER M5 ;
        RECT  46.512 0 46.536 0.084 ;
    END
  END w[38]
  PIN w[39]
    DIRECTION OUTPUT ;
    USE SIGNAL ;
    PORT
      LAYER M5 ;
        RECT  46.608 0 46.632 0.084 ;
    END
  END w[39]
  PIN w[3]
    DIRECTION OUTPUT ;
    USE SIGNAL ;
    PORT
      LAYER M5 ;
        RECT  55.44 0 55.464 0.084 ;
    END
  END w[3]
  PIN w[40]
    DIRECTION OUTPUT ;
    USE SIGNAL ;
    PORT
      LAYER M5 ;
        RECT  46.704 0 46.728 0.084 ;
    END
  END w[40]
  PIN w[41]
    DIRECTION OUTPUT ;
    USE SIGNAL ;
    PORT
      LAYER M5 ;
        RECT  46.8 0 46.824 0.084 ;
    END
  END w[41]
  PIN w[42]
    DIRECTION OUTPUT ;
    USE SIGNAL ;
    PORT
      LAYER M5 ;
        RECT  46.896 0 46.92 0.084 ;
    END
  END w[42]
  PIN w[43]
    DIRECTION OUTPUT ;
    USE SIGNAL ;
    PORT
      LAYER M5 ;
        RECT  46.992 0 47.016 0.084 ;
    END
  END w[43]
  PIN w[44]
    DIRECTION OUTPUT ;
    USE SIGNAL ;
    PORT
      LAYER M5 ;
        RECT  47.088 0 47.112 0.084 ;
    END
  END w[44]
  PIN w[45]
    DIRECTION OUTPUT ;
    USE SIGNAL ;
    PORT
      LAYER M5 ;
        RECT  47.184 0 47.208 0.084 ;
    END
  END w[45]
  PIN w[46]
    DIRECTION OUTPUT ;
    USE SIGNAL ;
    PORT
      LAYER M5 ;
        RECT  47.28 0 47.304 0.084 ;
    END
  END w[46]
  PIN w[47]
    DIRECTION OUTPUT ;
    USE SIGNAL ;
    PORT
      LAYER M5 ;
        RECT  47.376 0 47.4 0.084 ;
    END
  END w[47]
  PIN w[48]
    DIRECTION OUTPUT ;
    USE SIGNAL ;
    PORT
      LAYER M5 ;
        RECT  47.472 0 47.496 0.084 ;
    END
  END w[48]
  PIN w[49]
    DIRECTION OUTPUT ;
    USE SIGNAL ;
    PORT
      LAYER M5 ;
        RECT  47.568 0 47.592 0.084 ;
    END
  END w[49]
  PIN w[4]
    DIRECTION OUTPUT ;
    USE SIGNAL ;
    PORT
      LAYER M5 ;
        RECT  55.536 0 55.56 0.084 ;
    END
  END w[4]
  PIN w[50]
    DIRECTION OUTPUT ;
    USE SIGNAL ;
    PORT
      LAYER M5 ;
        RECT  47.664 0 47.688 0.084 ;
    END
  END w[50]
  PIN w[51]
    DIRECTION OUTPUT ;
    USE SIGNAL ;
    PORT
      LAYER M5 ;
        RECT  47.76 0 47.784 0.084 ;
    END
  END w[51]
  PIN w[52]
    DIRECTION OUTPUT ;
    USE SIGNAL ;
    PORT
      LAYER M5 ;
        RECT  47.856 0 47.88 0.084 ;
    END
  END w[52]
  PIN w[53]
    DIRECTION OUTPUT ;
    USE SIGNAL ;
    PORT
      LAYER M5 ;
        RECT  47.952 0 47.976 0.084 ;
    END
  END w[53]
  PIN w[54]
    DIRECTION OUTPUT ;
    USE SIGNAL ;
    PORT
      LAYER M5 ;
        RECT  48.048 0 48.072 0.084 ;
    END
  END w[54]
  PIN w[55]
    DIRECTION OUTPUT ;
    USE SIGNAL ;
    PORT
      LAYER M5 ;
        RECT  48.144 0 48.168 0.084 ;
    END
  END w[55]
  PIN w[56]
    DIRECTION OUTPUT ;
    USE SIGNAL ;
    PORT
      LAYER M5 ;
        RECT  48.24 0 48.264 0.084 ;
    END
  END w[56]
  PIN w[57]
    DIRECTION OUTPUT ;
    USE SIGNAL ;
    PORT
      LAYER M5 ;
        RECT  39.12 0 39.144 0.084 ;
    END
  END w[57]
  PIN w[58]
    DIRECTION OUTPUT ;
    USE SIGNAL ;
    PORT
      LAYER M5 ;
        RECT  39.216 0 39.24 0.084 ;
    END
  END w[58]
  PIN w[59]
    DIRECTION OUTPUT ;
    USE SIGNAL ;
    PORT
      LAYER M5 ;
        RECT  39.312 0 39.336 0.084 ;
    END
  END w[59]
  PIN w[5]
    DIRECTION OUTPUT ;
    USE SIGNAL ;
    PORT
      LAYER M5 ;
        RECT  55.632 0 55.656 0.084 ;
    END
  END w[5]
  PIN w[60]
    DIRECTION OUTPUT ;
    USE SIGNAL ;
    PORT
      LAYER M5 ;
        RECT  39.408 0 39.432 0.084 ;
    END
  END w[60]
  PIN w[61]
    DIRECTION OUTPUT ;
    USE SIGNAL ;
    PORT
      LAYER M5 ;
        RECT  39.504 0 39.528 0.084 ;
    END
  END w[61]
  PIN w[62]
    DIRECTION OUTPUT ;
    USE SIGNAL ;
    PORT
      LAYER M5 ;
        RECT  39.6 0 39.624 0.084 ;
    END
  END w[62]
  PIN w[63]
    DIRECTION OUTPUT ;
    USE SIGNAL ;
    PORT
      LAYER M5 ;
        RECT  39.696 0 39.72 0.084 ;
    END
  END w[63]
  PIN w[64]
    DIRECTION OUTPUT ;
    USE SIGNAL ;
    PORT
      LAYER M5 ;
        RECT  39.792 0 39.816 0.084 ;
    END
  END w[64]
  PIN w[65]
    DIRECTION OUTPUT ;
    USE SIGNAL ;
    PORT
      LAYER M5 ;
        RECT  39.888 0 39.912 0.084 ;
    END
  END w[65]
  PIN w[66]
    DIRECTION OUTPUT ;
    USE SIGNAL ;
    PORT
      LAYER M5 ;
        RECT  39.984 0 40.008 0.084 ;
    END
  END w[66]
  PIN w[67]
    DIRECTION OUTPUT ;
    USE SIGNAL ;
    PORT
      LAYER M5 ;
        RECT  40.08 0 40.104 0.084 ;
    END
  END w[67]
  PIN w[68]
    DIRECTION OUTPUT ;
    USE SIGNAL ;
    PORT
      LAYER M5 ;
        RECT  40.176 0 40.2 0.084 ;
    END
  END w[68]
  PIN w[69]
    DIRECTION OUTPUT ;
    USE SIGNAL ;
    PORT
      LAYER M5 ;
        RECT  40.272 0 40.296 0.084 ;
    END
  END w[69]
  PIN w[6]
    DIRECTION OUTPUT ;
    USE SIGNAL ;
    PORT
      LAYER M5 ;
        RECT  55.728 0 55.752 0.084 ;
    END
  END w[6]
  PIN w[70]
    DIRECTION OUTPUT ;
    USE SIGNAL ;
    PORT
      LAYER M5 ;
        RECT  40.368 0 40.392 0.084 ;
    END
  END w[70]
  PIN w[71]
    DIRECTION OUTPUT ;
    USE SIGNAL ;
    PORT
      LAYER M5 ;
        RECT  40.464 0 40.488 0.084 ;
    END
  END w[71]
  PIN w[72]
    DIRECTION OUTPUT ;
    USE SIGNAL ;
    PORT
      LAYER M5 ;
        RECT  40.56 0 40.584 0.084 ;
    END
  END w[72]
  PIN w[73]
    DIRECTION OUTPUT ;
    USE SIGNAL ;
    PORT
      LAYER M5 ;
        RECT  40.656 0 40.68 0.084 ;
    END
  END w[73]
  PIN w[74]
    DIRECTION OUTPUT ;
    USE SIGNAL ;
    PORT
      LAYER M5 ;
        RECT  40.752 0 40.776 0.084 ;
    END
  END w[74]
  PIN w[75]
    DIRECTION OUTPUT ;
    USE SIGNAL ;
    PORT
      LAYER M5 ;
        RECT  40.848 0 40.872 0.084 ;
    END
  END w[75]
  PIN w[76]
    DIRECTION OUTPUT ;
    USE SIGNAL ;
    PORT
      LAYER M5 ;
        RECT  40.944 0 40.968 0.084 ;
    END
  END w[76]
  PIN w[77]
    DIRECTION OUTPUT ;
    USE SIGNAL ;
    PORT
      LAYER M5 ;
        RECT  41.04 0 41.064 0.084 ;
    END
  END w[77]
  PIN w[78]
    DIRECTION OUTPUT ;
    USE SIGNAL ;
    PORT
      LAYER M5 ;
        RECT  41.136 0 41.16 0.084 ;
    END
  END w[78]
  PIN w[79]
    DIRECTION OUTPUT ;
    USE SIGNAL ;
    PORT
      LAYER M5 ;
        RECT  41.232 0 41.256 0.084 ;
    END
  END w[79]
  PIN w[7]
    DIRECTION OUTPUT ;
    USE SIGNAL ;
    PORT
      LAYER M5 ;
        RECT  55.824 0 55.848 0.084 ;
    END
  END w[7]
  PIN w[80]
    DIRECTION OUTPUT ;
    USE SIGNAL ;
    PORT
      LAYER M5 ;
        RECT  41.328 0 41.352 0.084 ;
    END
  END w[80]
  PIN w[81]
    DIRECTION OUTPUT ;
    USE SIGNAL ;
    PORT
      LAYER M5 ;
        RECT  41.424 0 41.448 0.084 ;
    END
  END w[81]
  PIN w[82]
    DIRECTION OUTPUT ;
    USE SIGNAL ;
    PORT
      LAYER M5 ;
        RECT  41.52 0 41.544 0.084 ;
    END
  END w[82]
  PIN w[83]
    DIRECTION OUTPUT ;
    USE SIGNAL ;
    PORT
      LAYER M5 ;
        RECT  41.616 0 41.64 0.084 ;
    END
  END w[83]
  PIN w[84]
    DIRECTION OUTPUT ;
    USE SIGNAL ;
    PORT
      LAYER M5 ;
        RECT  41.712 0 41.736 0.084 ;
    END
  END w[84]
  PIN w[85]
    DIRECTION OUTPUT ;
    USE SIGNAL ;
    PORT
      LAYER M5 ;
        RECT  41.808 0 41.832 0.084 ;
    END
  END w[85]
  PIN w[86]
    DIRECTION OUTPUT ;
    USE SIGNAL ;
    PORT
      LAYER M5 ;
        RECT  41.904 0 41.928 0.084 ;
    END
  END w[86]
  PIN w[87]
    DIRECTION OUTPUT ;
    USE SIGNAL ;
    PORT
      LAYER M5 ;
        RECT  42 0 42.024 0.084 ;
    END
  END w[87]
  PIN w[88]
    DIRECTION OUTPUT ;
    USE SIGNAL ;
    PORT
      LAYER M5 ;
        RECT  42.096 0 42.12 0.084 ;
    END
  END w[88]
  PIN w[89]
    DIRECTION OUTPUT ;
    USE SIGNAL ;
    PORT
      LAYER M5 ;
        RECT  86.736 0 86.76 0.084 ;
    END
  END w[89]
  PIN w[8]
    DIRECTION OUTPUT ;
    USE SIGNAL ;
    PORT
      LAYER M5 ;
        RECT  55.92 0 55.944 0.084 ;
    END
  END w[8]
  PIN w[90]
    DIRECTION OUTPUT ;
    USE SIGNAL ;
    PORT
      LAYER M5 ;
        RECT  86.832 0 86.856 0.084 ;
    END
  END w[90]
  PIN w[91]
    DIRECTION OUTPUT ;
    USE SIGNAL ;
    PORT
      LAYER M5 ;
        RECT  86.928 0 86.952 0.084 ;
    END
  END w[91]
  PIN w[92]
    DIRECTION OUTPUT ;
    USE SIGNAL ;
    PORT
      LAYER M5 ;
        RECT  87.024 0 87.048 0.084 ;
    END
  END w[92]
  PIN w[93]
    DIRECTION OUTPUT ;
    USE SIGNAL ;
    PORT
      LAYER M5 ;
        RECT  87.12 0 87.144 0.084 ;
    END
  END w[93]
  PIN w[94]
    DIRECTION OUTPUT ;
    USE SIGNAL ;
    PORT
      LAYER M5 ;
        RECT  87.216 0 87.24 0.084 ;
    END
  END w[94]
  PIN w[95]
    DIRECTION OUTPUT ;
    USE SIGNAL ;
    PORT
      LAYER M5 ;
        RECT  87.312 0 87.336 0.084 ;
    END
  END w[95]
  PIN w[96]
    DIRECTION OUTPUT ;
    USE SIGNAL ;
    PORT
      LAYER M5 ;
        RECT  87.408 0 87.432 0.084 ;
    END
  END w[96]
  PIN w[97]
    DIRECTION OUTPUT ;
    USE SIGNAL ;
    PORT
      LAYER M5 ;
        RECT  87.504 0 87.528 0.084 ;
    END
  END w[97]
  PIN w[98]
    DIRECTION OUTPUT ;
    USE SIGNAL ;
    PORT
      LAYER M5 ;
        RECT  87.6 0 87.624 0.084 ;
    END
  END w[98]
  PIN w[99]
    DIRECTION OUTPUT ;
    USE SIGNAL ;
    PORT
      LAYER M5 ;
        RECT  87.696 0 87.72 0.084 ;
    END
  END w[99]
  PIN w[9]
    DIRECTION OUTPUT ;
    USE SIGNAL ;
    PORT
      LAYER M5 ;
        RECT  56.016 0 56.04 0.084 ;
    END
  END w[9]
  PIN wr[0]
    DIRECTION INPUT ;
    USE SIGNAL ;
    PORT
      LAYER M5 ;
        RECT  38.064 0 38.088 0.084 ;
    END
  END wr[0]
  PIN wr[10]
    DIRECTION INPUT ;
    USE SIGNAL ;
    PORT
      LAYER M5 ;
        RECT  39.024 0 39.048 0.084 ;
    END
  END wr[10]
  PIN wr[1]
    DIRECTION INPUT ;
    USE SIGNAL ;
    PORT
      LAYER M5 ;
        RECT  38.16 0 38.184 0.084 ;
    END
  END wr[1]
  PIN wr[2]
    DIRECTION INPUT ;
    USE SIGNAL ;
    PORT
      LAYER M5 ;
        RECT  38.256 0 38.28 0.084 ;
    END
  END wr[2]
  PIN wr[3]
    DIRECTION INPUT ;
    USE SIGNAL ;
    PORT
      LAYER M5 ;
        RECT  38.352 0 38.376 0.084 ;
    END
  END wr[3]
  PIN wr[4]
    DIRECTION INPUT ;
    USE SIGNAL ;
    PORT
      LAYER M5 ;
        RECT  38.448 0 38.472 0.084 ;
    END
  END wr[4]
  PIN wr[5]
    DIRECTION INPUT ;
    USE SIGNAL ;
    PORT
      LAYER M5 ;
        RECT  38.544 0 38.568 0.084 ;
    END
  END wr[5]
  PIN wr[6]
    DIRECTION INPUT ;
    USE SIGNAL ;
    PORT
      LAYER M5 ;
        RECT  38.64 0 38.664 0.084 ;
    END
  END wr[6]
  PIN wr[7]
    DIRECTION INPUT ;
    USE SIGNAL ;
    PORT
      LAYER M5 ;
        RECT  38.736 0 38.76 0.084 ;
    END
  END wr[7]
  PIN wr[8]
    DIRECTION INPUT ;
    USE SIGNAL ;
    PORT
      LAYER M5 ;
        RECT  38.832 0 38.856 0.084 ;
    END
  END wr[8]
  PIN wr[9]
    DIRECTION INPUT ;
    USE SIGNAL ;
    PORT
      LAYER M5 ;
        RECT  38.928 0 38.952 0.084 ;
    END
  END wr[9]
  PIN VDD
    DIRECTION INOUT ;
    USE POWER ;
    PORT
      LAYER M5 ;
        RECT  126.792 2.151 126.912 181.449 ;
        RECT  121.392 2.151 121.512 181.449 ;
        RECT  115.992 2.151 116.112 181.449 ;
        RECT  110.592 2.151 110.712 181.449 ;
        RECT  105.192 2.151 105.312 181.449 ;
        RECT  99.792 2.151 99.912 181.449 ;
        RECT  94.392 2.151 94.512 181.449 ;
        RECT  88.992 2.151 89.112 181.449 ;
        RECT  83.592 2.151 83.712 181.449 ;
        RECT  78.192 2.151 78.312 181.449 ;
        RECT  72.792 2.151 72.912 181.449 ;
        RECT  67.392 2.151 67.512 181.449 ;
        RECT  61.992 2.151 62.112 181.449 ;
        RECT  56.592 2.151 56.712 181.449 ;
        RECT  51.192 2.151 51.312 181.449 ;
        RECT  45.792 2.151 45.912 181.449 ;
        RECT  40.392 2.151 40.512 181.449 ;
        RECT  34.992 2.151 35.112 181.449 ;
        RECT  29.592 2.151 29.712 181.449 ;
        RECT  24.192 2.151 24.312 181.449 ;
        RECT  18.792 2.151 18.912 181.449 ;
        RECT  13.392 2.151 13.512 181.449 ;
        RECT  7.992 2.151 8.112 181.449 ;
        RECT  2.592 2.151 2.712 181.449 ;
    END
  END VDD
  PIN VSS
    DIRECTION INOUT ;
    USE GROUND ;
    PORT
      LAYER M5 ;
        RECT  126.6 2.137 126.72 181.463 ;
        RECT  121.2 2.137 121.32 181.463 ;
        RECT  115.8 2.137 115.92 181.463 ;
        RECT  110.4 2.137 110.52 181.463 ;
        RECT  105 2.137 105.12 181.463 ;
        RECT  99.6 2.137 99.72 181.463 ;
        RECT  94.2 2.137 94.32 181.463 ;
        RECT  88.8 2.137 88.92 181.463 ;
        RECT  83.4 2.137 83.52 181.463 ;
        RECT  78 2.137 78.12 181.463 ;
        RECT  72.6 2.137 72.72 181.463 ;
        RECT  67.2 2.137 67.32 181.463 ;
        RECT  61.8 2.137 61.92 181.463 ;
        RECT  56.4 2.137 56.52 181.463 ;
        RECT  51 2.137 51.12 181.463 ;
        RECT  45.6 2.137 45.72 181.463 ;
        RECT  40.2 2.137 40.32 181.463 ;
        RECT  34.8 2.137 34.92 181.463 ;
        RECT  29.4 2.137 29.52 181.463 ;
        RECT  24 2.137 24.12 181.463 ;
        RECT  18.6 2.137 18.72 181.463 ;
        RECT  13.2 2.137 13.32 181.463 ;
        RECT  7.8 2.137 7.92 181.463 ;
        RECT  2.4 2.137 2.52 181.463 ;
    END
  END VSS
  # OT_OBS_CLOSED layer=M5 d_um=1.536 added=235
  OBS
    LAYER RVTN ;
     RECT  2.16 2.16 127.44 2.295 ;
     RECT  2.16 2.565 127.44 2.835 ;
     RECT  2.16 3.105 127.44 3.375 ;
     RECT  2.16 3.645 127.44 3.915 ;
     RECT  2.16 4.185 127.44 4.455 ;
     RECT  2.16 4.725 127.44 4.995 ;
     RECT  2.16 5.265 127.44 5.535 ;
     RECT  2.16 5.805 127.44 6.075 ;
     RECT  2.16 6.345 127.44 6.615 ;
     RECT  2.16 6.885 127.44 7.155 ;
     RECT  2.16 7.425 127.44 7.695 ;
     RECT  2.16 7.965 127.44 8.235 ;
     RECT  2.16 8.505 127.44 8.775 ;
     RECT  2.16 9.045 127.44 9.315 ;
     RECT  2.16 9.585 127.44 9.855 ;
     RECT  2.16 10.125 127.44 10.395 ;
     RECT  2.16 10.665 127.44 10.935 ;
     RECT  2.16 11.205 127.44 11.475 ;
     RECT  2.16 11.745 127.44 12.015 ;
     RECT  2.16 12.285 127.44 12.555 ;
     RECT  2.16 12.825 127.44 13.095 ;
     RECT  2.16 13.365 127.44 13.635 ;
     RECT  2.16 13.905 127.44 14.175 ;
     RECT  2.16 14.445 127.44 14.715 ;
     RECT  2.16 14.985 127.44 15.255 ;
     RECT  2.16 15.525 127.44 15.795 ;
     RECT  2.16 16.065 127.44 16.335 ;
     RECT  2.16 16.605 127.44 16.875 ;
     RECT  2.16 17.145 127.44 17.415 ;
     RECT  2.16 17.685 127.44 17.955 ;
     RECT  2.16 18.225 127.44 18.495 ;
     RECT  2.16 18.765 127.44 19.035 ;
     RECT  2.16 19.305 127.44 19.575 ;
     RECT  2.16 19.845 127.44 20.115 ;
     RECT  2.16 20.385 127.44 20.655 ;
     RECT  2.16 20.925 127.44 21.195 ;
     RECT  2.16 21.465 127.44 21.735 ;
     RECT  2.16 22.005 127.44 22.275 ;
     RECT  2.16 22.545 127.44 22.815 ;
     RECT  2.16 23.085 127.44 23.355 ;
     RECT  2.16 23.625 127.44 23.895 ;
     RECT  2.16 24.165 127.44 24.435 ;
     RECT  2.16 24.705 127.44 24.975 ;
     RECT  2.16 25.245 127.44 25.515 ;
     RECT  2.16 25.785 127.44 26.055 ;
     RECT  2.16 26.325 127.44 26.595 ;
     RECT  2.16 26.865 127.44 27.135 ;
     RECT  2.16 27.405 127.44 27.675 ;
     RECT  2.16 27.945 127.44 28.215 ;
     RECT  2.16 28.485 127.44 28.755 ;
     RECT  2.16 29.025 127.44 29.295 ;
     RECT  2.16 29.565 127.44 29.835 ;
     RECT  2.16 30.105 127.44 30.375 ;
     RECT  2.16 30.645 127.44 30.915 ;
     RECT  2.16 31.185 127.44 31.455 ;
     RECT  2.16 31.725 127.44 31.995 ;
     RECT  2.16 32.265 127.44 32.535 ;
     RECT  2.16 32.805 127.44 33.075 ;
     RECT  2.16 33.345 127.44 33.615 ;
     RECT  2.16 33.885 127.44 34.155 ;
     RECT  2.16 34.425 127.44 34.695 ;
     RECT  2.16 34.965 127.44 35.235 ;
     RECT  2.16 35.505 127.44 35.775 ;
     RECT  2.16 36.045 127.44 36.315 ;
     RECT  2.16 36.585 127.44 36.855 ;
     RECT  2.16 37.125 127.44 37.395 ;
     RECT  2.16 37.665 127.44 37.935 ;
     RECT  2.16 38.205 127.44 38.475 ;
     RECT  2.16 38.745 127.44 39.015 ;
     RECT  2.16 39.285 127.44 39.555 ;
     RECT  2.16 39.825 127.44 40.095 ;
     RECT  2.16 40.365 127.44 40.635 ;
     RECT  2.16 40.905 127.44 41.175 ;
     RECT  2.16 41.445 127.44 41.715 ;
     RECT  2.16 41.985 127.44 42.255 ;
     RECT  2.16 42.525 127.44 42.795 ;
     RECT  2.16 43.065 127.44 43.335 ;
     RECT  2.16 43.605 127.44 43.875 ;
     RECT  2.16 44.145 127.44 44.415 ;
     RECT  2.16 44.685 127.44 44.955 ;
     RECT  2.16 45.225 127.44 45.495 ;
     RECT  2.16 45.765 127.44 46.035 ;
     RECT  2.16 46.305 127.44 46.575 ;
     RECT  2.16 46.845 127.44 47.115 ;
     RECT  2.16 47.385 127.44 47.655 ;
     RECT  2.16 47.925 127.44 48.195 ;
     RECT  2.16 48.465 127.44 48.735 ;
     RECT  2.16 49.005 127.44 49.275 ;
     RECT  2.16 49.545 127.44 49.815 ;
     RECT  2.16 50.085 127.44 50.355 ;
     RECT  2.16 50.625 127.44 50.895 ;
     RECT  2.16 51.165 127.44 51.435 ;
     RECT  2.16 51.705 127.44 51.975 ;
     RECT  2.16 52.245 127.44 52.515 ;
     RECT  2.16 52.785 127.44 53.055 ;
     RECT  2.16 53.325 127.44 53.595 ;
     RECT  2.16 53.865 127.44 54.135 ;
     RECT  2.16 54.405 127.44 54.675 ;
     RECT  2.16 54.945 127.44 55.215 ;
     RECT  2.16 55.485 127.44 55.755 ;
     RECT  2.16 56.025 127.44 56.295 ;
     RECT  2.16 56.565 127.44 56.835 ;
     RECT  2.16 57.105 127.44 57.375 ;
     RECT  2.16 57.645 127.44 57.915 ;
     RECT  2.16 58.185 127.44 58.455 ;
     RECT  2.16 58.725 127.44 58.995 ;
     RECT  2.16 59.265 127.44 59.535 ;
     RECT  2.16 59.805 127.44 60.075 ;
     RECT  2.16 60.345 127.44 60.615 ;
     RECT  2.16 60.885 127.44 61.155 ;
     RECT  2.16 61.425 127.44 61.695 ;
     RECT  2.16 61.965 127.44 62.235 ;
     RECT  2.16 62.505 127.44 62.775 ;
     RECT  2.16 63.045 127.44 63.315 ;
     RECT  2.16 63.585 127.44 63.855 ;
     RECT  2.16 64.125 127.44 64.395 ;
     RECT  2.16 64.665 127.44 64.935 ;
     RECT  2.16 65.205 127.44 65.475 ;
     RECT  2.16 65.745 127.44 66.015 ;
     RECT  2.16 66.285 127.44 66.555 ;
     RECT  2.16 66.825 127.44 67.095 ;
     RECT  2.16 67.365 127.44 67.635 ;
     RECT  2.16 67.905 127.44 68.175 ;
     RECT  2.16 68.445 127.44 68.715 ;
     RECT  2.16 68.985 127.44 69.255 ;
     RECT  2.16 69.525 127.44 69.795 ;
     RECT  2.16 70.065 127.44 70.335 ;
     RECT  2.16 70.605 127.44 70.875 ;
     RECT  2.16 71.145 127.44 71.415 ;
     RECT  2.16 71.685 127.44 71.955 ;
     RECT  2.16 72.225 127.44 72.495 ;
     RECT  2.16 72.765 127.44 73.035 ;
     RECT  2.16 73.305 127.44 73.575 ;
     RECT  2.16 73.845 127.44 74.115 ;
     RECT  2.16 74.385 127.44 74.655 ;
     RECT  2.16 74.925 127.44 75.195 ;
     RECT  2.16 75.465 127.44 75.735 ;
     RECT  2.16 76.005 127.44 76.275 ;
     RECT  2.16 76.545 127.44 76.815 ;
     RECT  2.16 77.085 127.44 77.355 ;
     RECT  2.16 77.625 127.44 77.895 ;
     RECT  2.16 78.165 127.44 78.435 ;
     RECT  2.16 78.705 127.44 78.975 ;
     RECT  2.16 79.245 127.44 79.515 ;
     RECT  2.16 79.785 127.44 80.055 ;
     RECT  2.16 80.325 127.44 80.595 ;
     RECT  2.16 80.865 127.44 81.135 ;
     RECT  2.16 81.405 127.44 81.675 ;
     RECT  2.16 81.945 127.44 82.215 ;
     RECT  2.16 82.485 127.44 82.755 ;
     RECT  2.16 83.025 127.44 83.295 ;
     RECT  2.16 83.565 127.44 83.835 ;
     RECT  2.16 84.105 127.44 84.375 ;
     RECT  2.16 84.645 127.44 84.915 ;
     RECT  2.16 85.185 127.44 85.455 ;
     RECT  2.16 85.725 127.44 85.995 ;
     RECT  2.16 86.265 127.44 86.535 ;
     RECT  2.16 86.805 127.44 87.075 ;
     RECT  2.16 87.345 127.44 87.615 ;
     RECT  2.16 87.885 127.44 88.155 ;
     RECT  2.16 88.425 127.44 88.695 ;
     RECT  2.16 88.965 127.44 89.235 ;
     RECT  2.16 89.505 127.44 89.775 ;
     RECT  2.16 90.045 127.44 90.315 ;
     RECT  2.16 90.585 127.44 90.855 ;
     RECT  2.16 91.125 127.44 91.395 ;
     RECT  2.16 91.665 127.44 91.935 ;
     RECT  2.16 92.205 127.44 92.475 ;
     RECT  2.16 92.745 127.44 93.015 ;
     RECT  2.16 93.285 127.44 93.555 ;
     RECT  2.16 93.825 127.44 94.095 ;
     RECT  2.16 94.365 127.44 94.635 ;
     RECT  2.16 94.905 127.44 95.175 ;
     RECT  2.16 95.445 127.44 95.715 ;
     RECT  2.16 95.985 127.44 96.255 ;
     RECT  2.16 96.525 127.44 96.795 ;
     RECT  2.16 97.065 127.44 97.335 ;
     RECT  2.16 97.605 127.44 97.875 ;
     RECT  2.16 98.145 127.44 98.415 ;
     RECT  2.16 98.685 127.44 98.955 ;
     RECT  2.16 99.225 127.44 99.495 ;
     RECT  2.16 99.765 127.44 100.035 ;
     RECT  2.16 100.305 127.44 100.575 ;
     RECT  2.16 100.845 127.44 101.115 ;
     RECT  2.16 101.385 127.44 101.655 ;
     RECT  2.16 101.925 127.44 102.195 ;
     RECT  2.16 102.465 127.44 102.735 ;
     RECT  2.16 103.005 127.44 103.275 ;
     RECT  2.16 103.545 127.44 103.815 ;
     RECT  2.16 104.085 127.44 104.355 ;
     RECT  2.16 104.625 127.44 104.895 ;
     RECT  2.16 105.165 127.44 105.435 ;
     RECT  2.16 105.705 127.44 105.975 ;
     RECT  2.16 106.245 127.44 106.515 ;
     RECT  2.16 106.785 127.44 107.055 ;
     RECT  2.16 107.325 127.44 107.595 ;
     RECT  2.16 107.865 127.44 108.135 ;
     RECT  2.16 108.405 127.44 108.675 ;
     RECT  2.16 108.945 127.44 109.215 ;
     RECT  2.16 109.485 127.44 109.755 ;
     RECT  2.16 110.025 127.44 110.295 ;
     RECT  2.16 110.565 127.44 110.835 ;
     RECT  2.16 111.105 127.44 111.375 ;
     RECT  2.16 111.645 127.44 111.915 ;
     RECT  2.16 112.185 127.44 112.455 ;
     RECT  2.16 112.725 127.44 112.995 ;
     RECT  2.16 113.265 127.44 113.535 ;
     RECT  2.16 113.805 127.44 114.075 ;
     RECT  2.16 114.345 127.44 114.615 ;
     RECT  2.16 114.885 127.44 115.155 ;
     RECT  2.16 115.425 127.44 115.695 ;
     RECT  2.16 115.965 127.44 116.235 ;
     RECT  2.16 116.505 127.44 116.775 ;
     RECT  2.16 117.045 127.44 117.315 ;
     RECT  2.16 117.585 127.44 117.855 ;
     RECT  2.16 118.125 127.44 118.395 ;
     RECT  2.16 118.665 127.44 118.935 ;
     RECT  2.16 119.205 127.44 119.475 ;
     RECT  2.16 119.745 127.44 120.015 ;
     RECT  2.16 120.285 127.44 120.555 ;
     RECT  2.16 120.825 127.44 121.095 ;
     RECT  2.16 121.365 127.44 121.635 ;
     RECT  2.16 121.905 127.44 122.175 ;
     RECT  2.16 122.445 127.44 122.715 ;
     RECT  2.16 122.985 127.44 123.255 ;
     RECT  2.16 123.525 127.44 123.795 ;
     RECT  2.16 124.065 127.44 124.335 ;
     RECT  2.16 124.605 127.44 124.875 ;
     RECT  2.16 125.145 127.44 125.415 ;
     RECT  2.16 125.685 127.44 125.955 ;
     RECT  2.16 126.225 127.44 126.495 ;
     RECT  2.16 126.765 127.44 127.035 ;
     RECT  2.16 127.305 127.44 127.575 ;
     RECT  2.16 127.845 127.44 128.115 ;
     RECT  2.16 128.385 127.44 128.655 ;
     RECT  2.16 128.925 127.44 129.195 ;
     RECT  2.16 129.465 127.44 129.735 ;
     RECT  2.16 130.005 127.44 130.275 ;
     RECT  2.16 130.545 127.44 130.815 ;
     RECT  2.16 131.085 127.44 131.355 ;
     RECT  2.16 131.625 127.44 131.895 ;
     RECT  2.16 132.165 127.44 132.435 ;
     RECT  2.16 132.705 127.44 132.975 ;
     RECT  2.16 133.245 127.44 133.515 ;
     RECT  2.16 133.785 127.44 134.055 ;
     RECT  2.16 134.325 127.44 134.595 ;
     RECT  2.16 134.865 127.44 135.135 ;
     RECT  2.16 135.405 127.44 135.675 ;
     RECT  2.16 135.945 127.44 136.215 ;
     RECT  2.16 136.485 127.44 136.755 ;
     RECT  2.16 137.025 127.44 137.295 ;
     RECT  2.16 137.565 127.44 137.835 ;
     RECT  2.16 138.105 127.44 138.375 ;
     RECT  2.16 138.645 127.44 138.915 ;
     RECT  2.16 139.185 127.44 139.455 ;
     RECT  2.16 139.725 127.44 139.995 ;
     RECT  2.16 140.265 127.44 140.535 ;
     RECT  2.16 140.805 127.44 141.075 ;
     RECT  2.16 141.345 127.44 141.615 ;
     RECT  2.16 141.885 127.44 142.155 ;
     RECT  2.16 142.425 127.44 142.695 ;
     RECT  2.16 142.965 127.44 143.235 ;
     RECT  2.16 143.505 127.44 143.775 ;
     RECT  2.16 144.045 127.44 144.315 ;
     RECT  2.16 144.585 127.44 144.855 ;
     RECT  2.16 145.125 127.44 145.395 ;
     RECT  2.16 145.665 127.44 145.935 ;
     RECT  2.16 146.205 127.44 146.475 ;
     RECT  2.16 146.745 127.44 147.015 ;
     RECT  2.16 147.285 127.44 147.555 ;
     RECT  2.16 147.825 127.44 148.095 ;
     RECT  2.16 148.365 127.44 148.635 ;
     RECT  2.16 148.905 127.44 149.175 ;
     RECT  2.16 149.445 127.44 149.715 ;
     RECT  2.16 149.985 127.44 150.255 ;
     RECT  2.16 150.525 127.44 150.795 ;
     RECT  2.16 151.065 127.44 151.335 ;
     RECT  2.16 151.605 127.44 151.875 ;
     RECT  2.16 152.145 127.44 152.415 ;
     RECT  2.16 152.685 127.44 152.955 ;
     RECT  2.16 153.225 127.44 153.495 ;
     RECT  2.16 153.765 127.44 154.035 ;
     RECT  2.16 154.305 127.44 154.575 ;
     RECT  2.16 154.845 127.44 155.115 ;
     RECT  2.16 155.385 127.44 155.655 ;
     RECT  2.16 155.925 127.44 156.195 ;
     RECT  2.16 156.465 127.44 156.735 ;
     RECT  2.16 157.005 127.44 157.275 ;
     RECT  2.16 157.545 127.44 157.815 ;
     RECT  2.16 158.085 127.44 158.355 ;
     RECT  2.16 158.625 127.44 158.895 ;
     RECT  2.16 159.165 127.44 159.435 ;
     RECT  2.16 159.705 127.44 159.975 ;
     RECT  2.16 160.245 127.44 160.515 ;
     RECT  2.16 160.785 127.44 161.055 ;
     RECT  2.16 161.325 127.44 161.595 ;
     RECT  2.16 161.865 127.44 162.135 ;
     RECT  2.16 162.405 127.44 162.675 ;
     RECT  2.16 162.945 127.44 163.215 ;
     RECT  2.16 163.485 127.44 163.755 ;
     RECT  2.16 164.025 127.44 164.295 ;
     RECT  2.16 164.565 127.44 164.835 ;
     RECT  2.16 165.105 127.44 165.375 ;
     RECT  2.16 165.645 127.44 165.915 ;
     RECT  2.16 166.185 127.44 166.455 ;
     RECT  2.16 166.725 127.44 166.995 ;
     RECT  2.16 167.265 127.44 167.535 ;
     RECT  2.16 167.805 127.44 168.075 ;
     RECT  2.16 168.345 127.44 168.615 ;
     RECT  2.16 168.885 127.44 169.155 ;
     RECT  2.16 169.425 127.44 169.695 ;
     RECT  2.16 169.965 127.44 170.235 ;
     RECT  2.16 170.505 127.44 170.775 ;
     RECT  2.16 171.045 127.44 171.315 ;
     RECT  2.16 171.585 127.44 171.855 ;
     RECT  2.16 172.125 127.44 172.395 ;
     RECT  2.16 172.665 127.44 172.935 ;
     RECT  2.16 173.205 127.44 173.475 ;
     RECT  2.16 173.745 127.44 174.015 ;
     RECT  2.16 174.285 127.44 174.555 ;
     RECT  2.16 174.825 127.44 175.095 ;
     RECT  2.16 175.365 127.44 175.635 ;
     RECT  2.16 175.905 127.44 176.175 ;
     RECT  2.16 176.445 127.44 176.715 ;
     RECT  2.16 176.985 127.44 177.255 ;
     RECT  2.16 177.525 127.44 177.795 ;
     RECT  2.16 178.065 127.44 178.335 ;
     RECT  2.16 178.605 127.44 178.875 ;
     RECT  2.16 179.145 127.44 179.415 ;
     RECT  2.16 179.685 127.44 179.955 ;
     RECT  2.16 180.225 127.44 180.495 ;
     RECT  2.16 180.765 127.44 181.035 ;
     RECT  2.16 181.305 127.44 181.44 ;
    LAYER RVTP ;
     RECT  2.16 2.295 127.44 2.565 ;
     RECT  2.16 2.835 127.44 3.105 ;
     RECT  2.16 3.375 127.44 3.645 ;
     RECT  2.16 3.915 127.44 4.185 ;
     RECT  2.16 4.455 127.44 4.725 ;
     RECT  2.16 4.995 127.44 5.265 ;
     RECT  2.16 5.535 127.44 5.805 ;
     RECT  2.16 6.075 127.44 6.345 ;
     RECT  2.16 6.615 127.44 6.885 ;
     RECT  2.16 7.155 127.44 7.425 ;
     RECT  2.16 7.695 127.44 7.965 ;
     RECT  2.16 8.235 127.44 8.505 ;
     RECT  2.16 8.775 127.44 9.045 ;
     RECT  2.16 9.315 127.44 9.585 ;
     RECT  2.16 9.855 127.44 10.125 ;
     RECT  2.16 10.395 127.44 10.665 ;
     RECT  2.16 10.935 127.44 11.205 ;
     RECT  2.16 11.475 127.44 11.745 ;
     RECT  2.16 12.015 127.44 12.285 ;
     RECT  2.16 12.555 127.44 12.825 ;
     RECT  2.16 13.095 127.44 13.365 ;
     RECT  2.16 13.635 127.44 13.905 ;
     RECT  2.16 14.175 127.44 14.445 ;
     RECT  2.16 14.715 127.44 14.985 ;
     RECT  2.16 15.255 127.44 15.525 ;
     RECT  2.16 15.795 127.44 16.065 ;
     RECT  2.16 16.335 127.44 16.605 ;
     RECT  2.16 16.875 127.44 17.145 ;
     RECT  2.16 17.415 127.44 17.685 ;
     RECT  2.16 17.955 127.44 18.225 ;
     RECT  2.16 18.495 127.44 18.765 ;
     RECT  2.16 19.035 127.44 19.305 ;
     RECT  2.16 19.575 127.44 19.845 ;
     RECT  2.16 20.115 127.44 20.385 ;
     RECT  2.16 20.655 127.44 20.925 ;
     RECT  2.16 21.195 127.44 21.465 ;
     RECT  2.16 21.735 127.44 22.005 ;
     RECT  2.16 22.275 127.44 22.545 ;
     RECT  2.16 22.815 127.44 23.085 ;
     RECT  2.16 23.355 127.44 23.625 ;
     RECT  2.16 23.895 127.44 24.165 ;
     RECT  2.16 24.435 127.44 24.705 ;
     RECT  2.16 24.975 127.44 25.245 ;
     RECT  2.16 25.515 127.44 25.785 ;
     RECT  2.16 26.055 127.44 26.325 ;
     RECT  2.16 26.595 127.44 26.865 ;
     RECT  2.16 27.135 127.44 27.405 ;
     RECT  2.16 27.675 127.44 27.945 ;
     RECT  2.16 28.215 127.44 28.485 ;
     RECT  2.16 28.755 127.44 29.025 ;
     RECT  2.16 29.295 127.44 29.565 ;
     RECT  2.16 29.835 127.44 30.105 ;
     RECT  2.16 30.375 127.44 30.645 ;
     RECT  2.16 30.915 127.44 31.185 ;
     RECT  2.16 31.455 127.44 31.725 ;
     RECT  2.16 31.995 127.44 32.265 ;
     RECT  2.16 32.535 127.44 32.805 ;
     RECT  2.16 33.075 127.44 33.345 ;
     RECT  2.16 33.615 127.44 33.885 ;
     RECT  2.16 34.155 127.44 34.425 ;
     RECT  2.16 34.695 127.44 34.965 ;
     RECT  2.16 35.235 127.44 35.505 ;
     RECT  2.16 35.775 127.44 36.045 ;
     RECT  2.16 36.315 127.44 36.585 ;
     RECT  2.16 36.855 127.44 37.125 ;
     RECT  2.16 37.395 127.44 37.665 ;
     RECT  2.16 37.935 127.44 38.205 ;
     RECT  2.16 38.475 127.44 38.745 ;
     RECT  2.16 39.015 127.44 39.285 ;
     RECT  2.16 39.555 127.44 39.825 ;
     RECT  2.16 40.095 127.44 40.365 ;
     RECT  2.16 40.635 127.44 40.905 ;
     RECT  2.16 41.175 127.44 41.445 ;
     RECT  2.16 41.715 127.44 41.985 ;
     RECT  2.16 42.255 127.44 42.525 ;
     RECT  2.16 42.795 127.44 43.065 ;
     RECT  2.16 43.335 127.44 43.605 ;
     RECT  2.16 43.875 127.44 44.145 ;
     RECT  2.16 44.415 127.44 44.685 ;
     RECT  2.16 44.955 127.44 45.225 ;
     RECT  2.16 45.495 127.44 45.765 ;
     RECT  2.16 46.035 127.44 46.305 ;
     RECT  2.16 46.575 127.44 46.845 ;
     RECT  2.16 47.115 127.44 47.385 ;
     RECT  2.16 47.655 127.44 47.925 ;
     RECT  2.16 48.195 127.44 48.465 ;
     RECT  2.16 48.735 127.44 49.005 ;
     RECT  2.16 49.275 127.44 49.545 ;
     RECT  2.16 49.815 127.44 50.085 ;
     RECT  2.16 50.355 127.44 50.625 ;
     RECT  2.16 50.895 127.44 51.165 ;
     RECT  2.16 51.435 127.44 51.705 ;
     RECT  2.16 51.975 127.44 52.245 ;
     RECT  2.16 52.515 127.44 52.785 ;
     RECT  2.16 53.055 127.44 53.325 ;
     RECT  2.16 53.595 127.44 53.865 ;
     RECT  2.16 54.135 127.44 54.405 ;
     RECT  2.16 54.675 127.44 54.945 ;
     RECT  2.16 55.215 127.44 55.485 ;
     RECT  2.16 55.755 127.44 56.025 ;
     RECT  2.16 56.295 127.44 56.565 ;
     RECT  2.16 56.835 127.44 57.105 ;
     RECT  2.16 57.375 127.44 57.645 ;
     RECT  2.16 57.915 127.44 58.185 ;
     RECT  2.16 58.455 127.44 58.725 ;
     RECT  2.16 58.995 127.44 59.265 ;
     RECT  2.16 59.535 127.44 59.805 ;
     RECT  2.16 60.075 127.44 60.345 ;
     RECT  2.16 60.615 127.44 60.885 ;
     RECT  2.16 61.155 127.44 61.425 ;
     RECT  2.16 61.695 127.44 61.965 ;
     RECT  2.16 62.235 127.44 62.505 ;
     RECT  2.16 62.775 127.44 63.045 ;
     RECT  2.16 63.315 127.44 63.585 ;
     RECT  2.16 63.855 127.44 64.125 ;
     RECT  2.16 64.395 127.44 64.665 ;
     RECT  2.16 64.935 127.44 65.205 ;
     RECT  2.16 65.475 127.44 65.745 ;
     RECT  2.16 66.015 127.44 66.285 ;
     RECT  2.16 66.555 127.44 66.825 ;
     RECT  2.16 67.095 127.44 67.365 ;
     RECT  2.16 67.635 127.44 67.905 ;
     RECT  2.16 68.175 127.44 68.445 ;
     RECT  2.16 68.715 127.44 68.985 ;
     RECT  2.16 69.255 127.44 69.525 ;
     RECT  2.16 69.795 127.44 70.065 ;
     RECT  2.16 70.335 127.44 70.605 ;
     RECT  2.16 70.875 127.44 71.145 ;
     RECT  2.16 71.415 127.44 71.685 ;
     RECT  2.16 71.955 127.44 72.225 ;
     RECT  2.16 72.495 127.44 72.765 ;
     RECT  2.16 73.035 127.44 73.305 ;
     RECT  2.16 73.575 127.44 73.845 ;
     RECT  2.16 74.115 127.44 74.385 ;
     RECT  2.16 74.655 127.44 74.925 ;
     RECT  2.16 75.195 127.44 75.465 ;
     RECT  2.16 75.735 127.44 76.005 ;
     RECT  2.16 76.275 127.44 76.545 ;
     RECT  2.16 76.815 127.44 77.085 ;
     RECT  2.16 77.355 127.44 77.625 ;
     RECT  2.16 77.895 127.44 78.165 ;
     RECT  2.16 78.435 127.44 78.705 ;
     RECT  2.16 78.975 127.44 79.245 ;
     RECT  2.16 79.515 127.44 79.785 ;
     RECT  2.16 80.055 127.44 80.325 ;
     RECT  2.16 80.595 127.44 80.865 ;
     RECT  2.16 81.135 127.44 81.405 ;
     RECT  2.16 81.675 127.44 81.945 ;
     RECT  2.16 82.215 127.44 82.485 ;
     RECT  2.16 82.755 127.44 83.025 ;
     RECT  2.16 83.295 127.44 83.565 ;
     RECT  2.16 83.835 127.44 84.105 ;
     RECT  2.16 84.375 127.44 84.645 ;
     RECT  2.16 84.915 127.44 85.185 ;
     RECT  2.16 85.455 127.44 85.725 ;
     RECT  2.16 85.995 127.44 86.265 ;
     RECT  2.16 86.535 127.44 86.805 ;
     RECT  2.16 87.075 127.44 87.345 ;
     RECT  2.16 87.615 127.44 87.885 ;
     RECT  2.16 88.155 127.44 88.425 ;
     RECT  2.16 88.695 127.44 88.965 ;
     RECT  2.16 89.235 127.44 89.505 ;
     RECT  2.16 89.775 127.44 90.045 ;
     RECT  2.16 90.315 127.44 90.585 ;
     RECT  2.16 90.855 127.44 91.125 ;
     RECT  2.16 91.395 127.44 91.665 ;
     RECT  2.16 91.935 127.44 92.205 ;
     RECT  2.16 92.475 127.44 92.745 ;
     RECT  2.16 93.015 127.44 93.285 ;
     RECT  2.16 93.555 127.44 93.825 ;
     RECT  2.16 94.095 127.44 94.365 ;
     RECT  2.16 94.635 127.44 94.905 ;
     RECT  2.16 95.175 127.44 95.445 ;
     RECT  2.16 95.715 127.44 95.985 ;
     RECT  2.16 96.255 127.44 96.525 ;
     RECT  2.16 96.795 127.44 97.065 ;
     RECT  2.16 97.335 127.44 97.605 ;
     RECT  2.16 97.875 127.44 98.145 ;
     RECT  2.16 98.415 127.44 98.685 ;
     RECT  2.16 98.955 127.44 99.225 ;
     RECT  2.16 99.495 127.44 99.765 ;
     RECT  2.16 100.035 127.44 100.305 ;
     RECT  2.16 100.575 127.44 100.845 ;
     RECT  2.16 101.115 127.44 101.385 ;
     RECT  2.16 101.655 127.44 101.925 ;
     RECT  2.16 102.195 127.44 102.465 ;
     RECT  2.16 102.735 127.44 103.005 ;
     RECT  2.16 103.275 127.44 103.545 ;
     RECT  2.16 103.815 127.44 104.085 ;
     RECT  2.16 104.355 127.44 104.625 ;
     RECT  2.16 104.895 127.44 105.165 ;
     RECT  2.16 105.435 127.44 105.705 ;
     RECT  2.16 105.975 127.44 106.245 ;
     RECT  2.16 106.515 127.44 106.785 ;
     RECT  2.16 107.055 127.44 107.325 ;
     RECT  2.16 107.595 127.44 107.865 ;
     RECT  2.16 108.135 127.44 108.405 ;
     RECT  2.16 108.675 127.44 108.945 ;
     RECT  2.16 109.215 127.44 109.485 ;
     RECT  2.16 109.755 127.44 110.025 ;
     RECT  2.16 110.295 127.44 110.565 ;
     RECT  2.16 110.835 127.44 111.105 ;
     RECT  2.16 111.375 127.44 111.645 ;
     RECT  2.16 111.915 127.44 112.185 ;
     RECT  2.16 112.455 127.44 112.725 ;
     RECT  2.16 112.995 127.44 113.265 ;
     RECT  2.16 113.535 127.44 113.805 ;
     RECT  2.16 114.075 127.44 114.345 ;
     RECT  2.16 114.615 127.44 114.885 ;
     RECT  2.16 115.155 127.44 115.425 ;
     RECT  2.16 115.695 127.44 115.965 ;
     RECT  2.16 116.235 127.44 116.505 ;
     RECT  2.16 116.775 127.44 117.045 ;
     RECT  2.16 117.315 127.44 117.585 ;
     RECT  2.16 117.855 127.44 118.125 ;
     RECT  2.16 118.395 127.44 118.665 ;
     RECT  2.16 118.935 127.44 119.205 ;
     RECT  2.16 119.475 127.44 119.745 ;
     RECT  2.16 120.015 127.44 120.285 ;
     RECT  2.16 120.555 127.44 120.825 ;
     RECT  2.16 121.095 127.44 121.365 ;
     RECT  2.16 121.635 127.44 121.905 ;
     RECT  2.16 122.175 127.44 122.445 ;
     RECT  2.16 122.715 127.44 122.985 ;
     RECT  2.16 123.255 127.44 123.525 ;
     RECT  2.16 123.795 127.44 124.065 ;
     RECT  2.16 124.335 127.44 124.605 ;
     RECT  2.16 124.875 127.44 125.145 ;
     RECT  2.16 125.415 127.44 125.685 ;
     RECT  2.16 125.955 127.44 126.225 ;
     RECT  2.16 126.495 127.44 126.765 ;
     RECT  2.16 127.035 127.44 127.305 ;
     RECT  2.16 127.575 127.44 127.845 ;
     RECT  2.16 128.115 127.44 128.385 ;
     RECT  2.16 128.655 127.44 128.925 ;
     RECT  2.16 129.195 127.44 129.465 ;
     RECT  2.16 129.735 127.44 130.005 ;
     RECT  2.16 130.275 127.44 130.545 ;
     RECT  2.16 130.815 127.44 131.085 ;
     RECT  2.16 131.355 127.44 131.625 ;
     RECT  2.16 131.895 127.44 132.165 ;
     RECT  2.16 132.435 127.44 132.705 ;
     RECT  2.16 132.975 127.44 133.245 ;
     RECT  2.16 133.515 127.44 133.785 ;
     RECT  2.16 134.055 127.44 134.325 ;
     RECT  2.16 134.595 127.44 134.865 ;
     RECT  2.16 135.135 127.44 135.405 ;
     RECT  2.16 135.675 127.44 135.945 ;
     RECT  2.16 136.215 127.44 136.485 ;
     RECT  2.16 136.755 127.44 137.025 ;
     RECT  2.16 137.295 127.44 137.565 ;
     RECT  2.16 137.835 127.44 138.105 ;
     RECT  2.16 138.375 127.44 138.645 ;
     RECT  2.16 138.915 127.44 139.185 ;
     RECT  2.16 139.455 127.44 139.725 ;
     RECT  2.16 139.995 127.44 140.265 ;
     RECT  2.16 140.535 127.44 140.805 ;
     RECT  2.16 141.075 127.44 141.345 ;
     RECT  2.16 141.615 127.44 141.885 ;
     RECT  2.16 142.155 127.44 142.425 ;
     RECT  2.16 142.695 127.44 142.965 ;
     RECT  2.16 143.235 127.44 143.505 ;
     RECT  2.16 143.775 127.44 144.045 ;
     RECT  2.16 144.315 127.44 144.585 ;
     RECT  2.16 144.855 127.44 145.125 ;
     RECT  2.16 145.395 127.44 145.665 ;
     RECT  2.16 145.935 127.44 146.205 ;
     RECT  2.16 146.475 127.44 146.745 ;
     RECT  2.16 147.015 127.44 147.285 ;
     RECT  2.16 147.555 127.44 147.825 ;
     RECT  2.16 148.095 127.44 148.365 ;
     RECT  2.16 148.635 127.44 148.905 ;
     RECT  2.16 149.175 127.44 149.445 ;
     RECT  2.16 149.715 127.44 149.985 ;
     RECT  2.16 150.255 127.44 150.525 ;
     RECT  2.16 150.795 127.44 151.065 ;
     RECT  2.16 151.335 127.44 151.605 ;
     RECT  2.16 151.875 127.44 152.145 ;
     RECT  2.16 152.415 127.44 152.685 ;
     RECT  2.16 152.955 127.44 153.225 ;
     RECT  2.16 153.495 127.44 153.765 ;
     RECT  2.16 154.035 127.44 154.305 ;
     RECT  2.16 154.575 127.44 154.845 ;
     RECT  2.16 155.115 127.44 155.385 ;
     RECT  2.16 155.655 127.44 155.925 ;
     RECT  2.16 156.195 127.44 156.465 ;
     RECT  2.16 156.735 127.44 157.005 ;
     RECT  2.16 157.275 127.44 157.545 ;
     RECT  2.16 157.815 127.44 158.085 ;
     RECT  2.16 158.355 127.44 158.625 ;
     RECT  2.16 158.895 127.44 159.165 ;
     RECT  2.16 159.435 127.44 159.705 ;
     RECT  2.16 159.975 127.44 160.245 ;
     RECT  2.16 160.515 127.44 160.785 ;
     RECT  2.16 161.055 127.44 161.325 ;
     RECT  2.16 161.595 127.44 161.865 ;
     RECT  2.16 162.135 127.44 162.405 ;
     RECT  2.16 162.675 127.44 162.945 ;
     RECT  2.16 163.215 127.44 163.485 ;
     RECT  2.16 163.755 127.44 164.025 ;
     RECT  2.16 164.295 127.44 164.565 ;
     RECT  2.16 164.835 127.44 165.105 ;
     RECT  2.16 165.375 127.44 165.645 ;
     RECT  2.16 165.915 127.44 166.185 ;
     RECT  2.16 166.455 127.44 166.725 ;
     RECT  2.16 166.995 127.44 167.265 ;
     RECT  2.16 167.535 127.44 167.805 ;
     RECT  2.16 168.075 127.44 168.345 ;
     RECT  2.16 168.615 127.44 168.885 ;
     RECT  2.16 169.155 127.44 169.425 ;
     RECT  2.16 169.695 127.44 169.965 ;
     RECT  2.16 170.235 127.44 170.505 ;
     RECT  2.16 170.775 127.44 171.045 ;
     RECT  2.16 171.315 127.44 171.585 ;
     RECT  2.16 171.855 127.44 172.125 ;
     RECT  2.16 172.395 127.44 172.665 ;
     RECT  2.16 172.935 127.44 173.205 ;
     RECT  2.16 173.475 127.44 173.745 ;
     RECT  2.16 174.015 127.44 174.285 ;
     RECT  2.16 174.555 127.44 174.825 ;
     RECT  2.16 175.095 127.44 175.365 ;
     RECT  2.16 175.635 127.44 175.905 ;
     RECT  2.16 176.175 127.44 176.445 ;
     RECT  2.16 176.715 127.44 176.985 ;
     RECT  2.16 177.255 127.44 177.525 ;
     RECT  2.16 177.795 127.44 178.065 ;
     RECT  2.16 178.335 127.44 178.605 ;
     RECT  2.16 178.875 127.44 179.145 ;
     RECT  2.16 179.415 127.44 179.685 ;
     RECT  2.16 179.955 127.44 180.225 ;
     RECT  2.16 180.495 127.44 180.765 ;
     RECT  2.16 181.035 127.44 181.305 ;
    LAYER M1 ;
     RECT  2.16 2.151 127.44 181.449 ;
    LAYER M2 ;
     RECT  2.16 2.151 38.587 181.449 ;
     RECT  38.587 2.106 38.759 181.449 ;
     RECT  39.055 1.152 39.191 1.17 ;
     RECT  40.711 1.152 40.927 1.17 ;
     RECT  40.927 1.152 40.955 1.242 ;
     RECT  40.955 1.224 41.027 1.242 ;
     RECT  38.759 2.151 44.023 181.449 ;
     RECT  44.023 2.106 44.447 181.449 ;
     RECT  44.447 2.151 46.939 181.449 ;
     RECT  48.091 1.152 48.227 1.17 ;
     RECT  46.939 2.106 48.623 181.449 ;
     RECT  51.943 1.152 52.043 1.17 ;
     RECT  48.623 2.151 54.499 181.449 ;
     RECT  54.499 2.106 55.003 181.449 ;
     RECT  55.003 2.034 56.291 181.449 ;
     RECT  56.291 2.106 57.299 181.449 ;
     RECT  57.299 2.151 60.079 181.449 ;
     RECT  60.079 2.106 60.827 181.449 ;
     RECT  60.827 2.151 61.555 181.449 ;
     RECT  61.555 2.106 62.051 181.449 ;
     RECT  65.335 1.152 65.435 1.17 ;
     RECT  62.051 2.151 67.135 181.449 ;
     RECT  67.135 2.106 68.099 181.449 ;
     RECT  68.099 2.151 72.463 181.449 ;
     RECT  72.463 2.106 72.815 181.449 ;
     RECT  72.815 2.151 74.911 181.449 ;
     RECT  74.911 2.106 75.587 181.449 ;
     RECT  75.587 2.151 77.719 181.449 ;
     RECT  77.719 2.106 78.251 181.449 ;
     RECT  78.251 2.151 79.411 181.449 ;
     RECT  79.411 2.106 79.799 181.449 ;
     RECT  81.787 1.152 82.291 1.17 ;
     RECT  82.291 1.152 82.391 1.242 ;
     RECT  82.391 1.224 82.427 1.242 ;
     RECT  83.875 1.152 84.551 1.17 ;
     RECT  79.799 2.151 85.279 181.449 ;
     RECT  85.279 2.106 86.179 181.449 ;
     RECT  86.863 1.152 87.035 1.17 ;
     RECT  86.179 1.962 87.107 181.449 ;
     RECT  87.107 2.034 87.719 181.449 ;
     RECT  90.211 1.152 90.311 1.17 ;
     RECT  92.911 1.152 93.155 1.17 ;
     RECT  94.099 1.152 94.199 1.17 ;
     RECT  87.719 2.151 95.179 181.449 ;
     RECT  95.179 2.106 95.675 181.449 ;
     RECT  95.675 2.151 127.44 181.449 ;
     RECT  127.44 96.84 128.255 97.326 ;
     RECT  128.255 96.84 128.831 97.02 ;
     RECT  128.831 97.002 128.867 97.02 ;
    LAYER M3 ;
     RECT  65.268 0.091 65.286 0.139 ;
     RECT  72.252 0.091 74.538 0.139 ;
     RECT  86.076 0.091 86.094 0.139 ;
     RECT  86.832 0.091 86.85 0.139 ;
     RECT  68.04 0.091 68.058 0.187 ;
     RECT  84.564 0.091 84.582 0.187 ;
     RECT  88.668 0.091 88.686 0.187 ;
     RECT  83.232 0.091 83.25 0.235 ;
     RECT  94.788 0.091 94.806 0.269 ;
     RECT  88.668 0.187 89.262 0.331 ;
     RECT  50.976 0.091 52.758 0.461 ;
     RECT  81.576 0.091 81.594 0.475 ;
     RECT  82.44 0.091 82.458 0.475 ;
     RECT  41.328 0.091 41.346 0.523 ;
     RECT  44.892 0.091 44.91 0.523 ;
     RECT  50.148 0.091 50.166 0.523 ;
     RECT  50.976 0.461 50.994 0.523 ;
     RECT  72.252 0.139 74.646 0.523 ;
     RECT  77.364 0.091 77.634 0.523 ;
     RECT  78.588 0.091 79.47 0.523 ;
     RECT  83.232 0.235 83.358 0.523 ;
     RECT  84.564 0.187 84.618 0.523 ;
     RECT  87.588 0.091 87.606 0.523 ;
     RECT  44.496 0.523 44.91 0.571 ;
     RECT  47.556 0.091 49.266 0.571 ;
     RECT  51.948 0.461 52.758 0.571 ;
     RECT  55.224 0.091 55.242 0.571 ;
     RECT  64.26 0.091 64.278 0.571 ;
     RECT  65.268 0.139 65.358 0.571 ;
     RECT  71.496 0.091 71.514 0.571 ;
     RECT  72.252 0.523 74.79 0.571 ;
     RECT  81.576 0.475 82.458 0.571 ;
     RECT  86.076 0.139 86.85 0.571 ;
     RECT  87.588 0.523 87.858 0.571 ;
     RECT  37.296 0.091 37.314 1.051 ;
     RECT  37.224 1.051 37.314 1.099 ;
     RECT  38.952 0.091 38.97 1.099 ;
     RECT  58.68 0.571 58.698 1.099 ;
     RECT  70.704 0.523 70.722 1.099 ;
     RECT  71.496 0.571 75.51 1.099 ;
     RECT  77.364 0.523 79.47 1.099 ;
     RECT  90.216 0.091 90.234 1.099 ;
     RECT  93.132 0.091 93.762 1.099 ;
     RECT  94.932 0.571 94.95 1.099 ;
     RECT  95.76 0.571 95.778 1.099 ;
     RECT  40.932 0.523 41.346 1.147 ;
     RECT  56.052 0.091 56.25 1.147 ;
     RECT  57.024 0.091 57.042 1.147 ;
     RECT  64.08 0.571 65.358 1.147 ;
     RECT  66.6 0.091 67.194 1.147 ;
     RECT  70.308 1.099 75.51 1.147 ;
     RECT  86.076 0.571 87.858 1.147 ;
     RECT  88.668 0.331 89.298 1.147 ;
     RECT  90.216 1.099 90.27 1.147 ;
     RECT  93.132 1.099 94.122 1.147 ;
     RECT  91.188 1.147 91.206 1.195 ;
     RECT  91.188 1.195 91.53 1.675 ;
     RECT  37.08 1.099 37.314 1.723 ;
     RECT  38.952 1.099 39.798 1.723 ;
     RECT  40.716 1.147 41.346 1.723 ;
     RECT  43.128 0.091 43.146 1.723 ;
     RECT  44.136 0.571 44.91 1.723 ;
     RECT  46.044 0.523 46.062 1.723 ;
     RECT  47.088 0.571 49.374 1.723 ;
     RECT  50.148 0.523 50.994 1.723 ;
     RECT  51.948 0.571 52.866 1.723 ;
     RECT  53.712 0.091 54.018 1.723 ;
     RECT  54.756 0.571 55.242 1.723 ;
     RECT  56.052 1.147 57.042 1.723 ;
     RECT  58.68 1.099 59.346 1.723 ;
     RECT  60.732 0.091 60.75 1.723 ;
     RECT  61.668 0.523 61.686 1.723 ;
     RECT  64.08 1.147 65.43 1.723 ;
     RECT  66.312 1.147 67.194 1.723 ;
     RECT  68.004 0.187 68.058 1.723 ;
     RECT  69.156 0.571 69.174 1.723 ;
     RECT  70.308 1.147 75.654 1.723 ;
     RECT  77.364 1.099 79.65 1.723 ;
     RECT  80.82 0.571 82.458 1.723 ;
     RECT  83.232 0.523 84.618 1.723 ;
     RECT  86.076 1.147 90.306 1.723 ;
     RECT  91.188 1.675 91.602 1.723 ;
     RECT  92.916 1.147 94.194 1.723 ;
     RECT  94.932 1.099 95.778 1.723 ;
     RECT  62.964 1.723 75.654 1.771 ;
     RECT  77.364 1.723 84.906 1.771 ;
     RECT  62.964 1.771 75.69 1.819 ;
     RECT  76.5 1.723 76.518 1.819 ;
     RECT  37.08 1.723 39.87 1.915 ;
     RECT  40.716 1.723 57.366 1.915 ;
     RECT  77.256 1.771 84.906 2.101 ;
     RECT  85.68 1.723 96.426 2.101 ;
     RECT  37.08 1.915 57.366 2.191 ;
     RECT  62.964 1.819 76.518 2.191 ;
     RECT  77.256 2.101 96.426 2.191 ;
     RECT  58.572 1.723 62.082 2.227 ;
     RECT  62.964 2.191 96.426 2.227 ;
     RECT  37.08 2.191 57.582 2.251 ;
     RECT  58.572 2.227 96.426 2.251 ;
     RECT  2.415 2.143 2.505 2.413 ;
     RECT  7.815 2.143 7.905 2.413 ;
     RECT  13.215 2.143 13.305 2.413 ;
     RECT  18.615 2.143 18.705 2.413 ;
     RECT  24.015 2.143 24.105 2.413 ;
     RECT  29.415 2.143 29.505 2.413 ;
     RECT  34.815 2.143 34.905 2.413 ;
     RECT  99.615 2.143 99.705 2.413 ;
     RECT  105.015 2.143 105.105 2.413 ;
     RECT  110.415 2.143 110.505 2.413 ;
     RECT  115.815 2.143 115.905 2.413 ;
     RECT  121.215 2.143 121.305 2.413 ;
     RECT  126.615 2.143 126.705 2.413 ;
     RECT  37.08 2.251 96.426 2.605 ;
     RECT  97.164 2.461 97.182 2.605 ;
     RECT  36.936 2.605 97.182 2.641 ;
     RECT  36.468 2.641 97.254 4.559 ;
     RECT  37.404 4.559 97.254 5.341 ;
     RECT  36.468 4.559 36.486 5.369 ;
     RECT  37.404 5.341 97.758 5.459 ;
     RECT  37.404 5.459 97.074 6.151 ;
     RECT  36.936 6.151 97.074 6.269 ;
     RECT  37.08 6.269 97.074 7.231 ;
     RECT  37.08 7.231 97.65 7.421 ;
     RECT  37.08 7.421 97.074 7.619 ;
     RECT  37.08 7.619 97.038 7.889 ;
     RECT  37.08 7.889 96.93 8.969 ;
     RECT  96.912 8.969 96.93 9.239 ;
     RECT  96.984 9.661 97.002 9.923 ;
     RECT  37.08 8.969 96.174 10.165 ;
     RECT  37.08 10.165 96.21 10.435 ;
     RECT  36.648 10.435 96.21 10.471 ;
     RECT  36.648 10.471 96.282 10.697 ;
     RECT  36.648 10.697 96.246 10.829 ;
     RECT  36.864 10.829 96.246 11.129 ;
     RECT  36.864 11.129 96.21 11.939 ;
     RECT  36.864 11.939 96.174 11.998 ;
     RECT  37.188 11.998 96.174 12.749 ;
     RECT  37.188 12.749 37.206 12.785 ;
     RECT  37.98 12.749 96.174 12.901 ;
     RECT  37.98 12.901 96.57 13.631 ;
     RECT  37.98 13.631 96.246 13.675 ;
     RECT  37.512 13.675 96.246 13.771 ;
     RECT  37.044 13.771 96.246 14.099 ;
     RECT  37.368 14.099 96.246 14.285 ;
     RECT  37.728 14.285 96.246 14.639 ;
     RECT  37.728 14.639 96.102 14.675 ;
     RECT  37.728 14.675 95.598 14.711 ;
     RECT  38.196 14.711 95.598 15.179 ;
     RECT  38.196 15.179 40.497 15.215 ;
     RECT  38.844 15.215 40.497 15.485 ;
     RECT  41.256 15.179 95.598 15.601 ;
     RECT  41.256 15.601 95.886 15.989 ;
     RECT  95.868 15.989 95.886 16.133 ;
     RECT  39.132 15.485 40.497 16.141 ;
     RECT  41.256 15.989 95.094 16.141 ;
     RECT  39.132 16.141 95.094 16.601 ;
     RECT  39.6 16.601 95.094 16.709 ;
     RECT  40.215 16.709 95.094 17.221 ;
     RECT  40.215 17.221 95.526 17.693 ;
     RECT  40.215 17.693 79.65 17.879 ;
     RECT  80.46 17.693 95.526 17.915 ;
     RECT  80.46 17.915 94.59 18.023 ;
     RECT  80.46 18.023 94.497 18.059 ;
     RECT  95.4 17.915 95.526 18.149 ;
     RECT  95.4 18.149 95.418 18.185 ;
     RECT  41.364 17.879 79.65 18.689 ;
     RECT  90.072 18.059 94.497 18.689 ;
     RECT  41.4 18.689 79.65 18.697 ;
     RECT  80.46 18.059 89.097 18.697 ;
     RECT  90.432 18.689 94.497 18.797 ;
     RECT  41.4 18.697 89.097 19.031 ;
     RECT  90.648 18.797 94.497 19.067 ;
     RECT  41.4 19.031 42.498 19.229 ;
     RECT  43.308 19.031 89.097 19.229 ;
     RECT  41.4 19.229 42.462 19.265 ;
     RECT  77.94 19.229 89.097 19.301 ;
     RECT  41.472 19.265 42.462 19.337 ;
     RECT  91.224 19.067 94.497 19.373 ;
     RECT  42.12 19.337 42.462 19.499 ;
     RECT  42.12 19.499 42.138 19.535 ;
     RECT  43.308 19.229 60.678 19.571 ;
     RECT  91.224 19.373 93.222 19.607 ;
     RECT  77.976 19.301 89.097 19.769 ;
     RECT  91.548 19.607 93.222 19.805 ;
     RECT  77.976 19.769 86.238 19.877 ;
     RECT  87.48 19.769 89.097 19.913 ;
     RECT  92.088 19.805 93.222 19.913 ;
     RECT  87.696 19.913 89.097 19.949 ;
     RECT  86.22 19.877 86.238 20.039 ;
     RECT  92.412 19.913 93.222 20.039 ;
     RECT  77.976 19.877 85.446 20.059 ;
     RECT  92.412 20.039 92.43 20.075 ;
     RECT  77.94 20.059 85.446 20.111 ;
     RECT  61.668 19.229 76.986 20.191 ;
     RECT  77.94 20.111 85.05 20.191 ;
     RECT  61.668 20.191 85.05 20.309 ;
     RECT  88.02 19.949 89.097 20.381 ;
     RECT  79.704 20.309 85.05 20.39 ;
     RECT  79.704 20.39 85.014 20.417 ;
     RECT  93.204 20.039 93.222 20.417 ;
     RECT  79.704 20.417 84.258 20.453 ;
     RECT  88.02 20.381 88.038 20.453 ;
     RECT  79.704 20.453 83.697 20.489 ;
     RECT  84.996 20.417 85.014 20.489 ;
     RECT  43.308 19.571 60.606 20.525 ;
     RECT  61.668 20.309 78.966 20.579 ;
     RECT  83.304 20.489 83.697 20.579 ;
     RECT  61.668 20.579 78.786 20.669 ;
     RECT  79.704 20.489 82.35 21.029 ;
     RECT  80.64 21.029 82.35 21.119 ;
     RECT  79.704 21.029 79.866 21.155 ;
     RECT  81.504 21.119 82.35 21.155 ;
     RECT  79.704 21.155 79.722 21.191 ;
     RECT  82.224 21.155 82.35 21.425 ;
     RECT  61.668 20.669 78.297 21.629 ;
     RECT  44.46 20.525 60.606 21.695 ;
     RECT  83.415 20.579 83.697 21.883 ;
     RECT  83.196 21.883 83.697 22.081 ;
     RECT  82.584 22.081 83.697 22.157 ;
     RECT  83.196 22.157 83.697 22.199 ;
     RECT  61.668 21.629 76.698 23.117 ;
     RECT  61.668 23.117 76.554 24.331 ;
     RECT  44.712 21.695 60.606 24.539 ;
     RECT  88.815 20.381 89.097 27.931 ;
     RECT  88.815 27.931 89.37 28.111 ;
     RECT  45.504 24.539 60.606 28.139 ;
     RECT  88.38 28.111 89.37 28.139 ;
     RECT  88.38 28.139 89.097 28.157 ;
     RECT  61.524 24.331 76.554 30.811 ;
     RECT  45.504 28.139 60.462 31.261 ;
     RECT  61.236 30.811 76.554 31.261 ;
     RECT  45.504 31.261 76.554 32.099 ;
     RECT  43.308 20.525 43.398 55.291 ;
     RECT  42.624 55.291 43.398 55.409 ;
     RECT  42.3 55.561 42.318 55.613 ;
     RECT  43.308 55.409 43.398 57.307 ;
     RECT  43.308 57.307 43.902 57.343 ;
     RECT  44.712 24.539 44.73 57.343 ;
     RECT  43.308 57.343 44.73 57.371 ;
     RECT  44.136 57.371 44.73 57.389 ;
     RECT  44.208 57.389 44.73 57.569 ;
     RECT  78.015 21.629 78.297 60.427 ;
     RECT  78.015 60.427 78.39 60.809 ;
     RECT  43.308 57.371 43.398 72.185 ;
     RECT  43.38 72.185 43.398 84.749 ;
     RECT  45.504 32.099 45.897 92.443 ;
     RECT  47.016 32.099 76.554 92.443 ;
     RECT  81.72 92.371 81.738 92.477 ;
     RECT  45.504 92.443 76.554 92.48 ;
     RECT  46.656 92.48 76.554 92.621 ;
     RECT  81.396 92.515 81.414 92.765 ;
     RECT  126.615 2.413 126.897 96.331 ;
     RECT  125.064 96.295 125.082 96.449 ;
     RECT  126.216 96.331 126.897 96.449 ;
     RECT  126.615 96.449 126.897 96.565 ;
     RECT  122.616 96.529 122.634 96.601 ;
     RECT  118.584 96.601 118.602 96.719 ;
     RECT  126.615 96.565 127.134 96.749 ;
     RECT  128.232 96.811 128.25 96.835 ;
     RECT  124.668 96.565 125.046 96.859 ;
     RECT  122.544 96.601 122.634 96.893 ;
     RECT  122.544 96.893 122.562 96.899 ;
     RECT  128.232 96.835 128.826 96.997 ;
     RECT  128.232 96.997 128.862 97.037 ;
     RECT  124.2 96.859 125.046 97.277 ;
     RECT  128.232 97.037 128.25 97.331 ;
     RECT  124.704 97.277 125.046 97.529 ;
     RECT  124.704 97.529 124.722 97.565 ;
     RECT  47.016 92.621 76.554 106.709 ;
     RECT  44.712 57.569 44.73 108.869 ;
     RECT  45.504 92.48 45.897 109.319 ;
     RECT  47.016 106.709 76.302 109.417 ;
     RECT  46.98 109.417 76.302 109.949 ;
     RECT  46.98 109.949 47.034 110.219 ;
     RECT  47.772 109.949 76.302 140.203 ;
     RECT  47.772 140.203 76.446 140.729 ;
     RECT  46.98 110.219 46.998 143.581 ;
     RECT  47.772 140.729 76.302 143.581 ;
     RECT  46.98 143.581 76.302 143.645 ;
     RECT  46.98 143.645 46.998 146.437 ;
     RECT  47.772 143.645 76.302 146.437 ;
     RECT  46.98 146.437 76.302 146.477 ;
     RECT  44.496 150.379 44.514 150.421 ;
     RECT  44.208 150.421 44.514 150.449 ;
     RECT  44.208 150.449 44.226 150.461 ;
     RECT  46.98 146.477 46.998 151.483 ;
     RECT  45.615 109.319 45.897 151.573 ;
     RECT  46.764 151.483 46.998 151.573 ;
     RECT  45.324 151.573 46.998 151.613 ;
     RECT  46.98 151.613 46.998 172.975 ;
     RECT  47.772 146.477 76.302 172.975 ;
     RECT  46.98 172.975 76.302 175.981 ;
     RECT  46.8 175.981 76.302 176.377 ;
     RECT  46.764 176.377 76.302 176.647 ;
     RECT  46.692 176.647 76.302 176.909 ;
     RECT  45.615 151.613 45.897 177.025 ;
     RECT  46.692 176.909 75.438 177.025 ;
     RECT  76.284 176.909 76.302 178.799 ;
     RECT  45.615 177.025 75.438 178.951 ;
     RECT  45.615 178.951 75.546 180.149 ;
     RECT  45.615 180.149 75.51 180.491 ;
     RECT  2.415 2.413 2.697 181.187 ;
     RECT  7.815 2.413 8.097 181.187 ;
     RECT  13.215 2.413 13.497 181.187 ;
     RECT  18.615 2.413 18.897 181.187 ;
     RECT  24.015 2.413 24.297 181.187 ;
     RECT  29.415 2.413 29.697 181.187 ;
     RECT  34.815 2.413 35.097 181.187 ;
     RECT  40.215 17.879 40.497 181.187 ;
     RECT  78.015 60.809 78.297 181.187 ;
     RECT  83.415 22.199 83.697 181.187 ;
     RECT  88.815 28.157 89.097 181.187 ;
     RECT  94.215 19.373 94.497 181.187 ;
     RECT  99.615 2.413 99.897 181.187 ;
     RECT  105.015 2.413 105.297 181.187 ;
     RECT  110.415 2.413 110.697 181.187 ;
     RECT  115.815 2.413 116.097 181.187 ;
     RECT  121.215 2.413 121.497 181.187 ;
     RECT  126.615 96.749 126.897 181.187 ;
     RECT  45.615 180.491 75.438 181.229 ;
     RECT  45.615 181.229 75.042 181.265 ;
     RECT  74.34 181.265 75.042 181.277 ;
     RECT  45.615 181.265 73.602 181.373 ;
     RECT  45.615 181.373 70.686 181.421 ;
     RECT  74.34 181.277 74.934 181.421 ;
     RECT  2.415 181.187 2.505 181.457 ;
     RECT  7.815 181.187 7.905 181.457 ;
     RECT  13.215 181.187 13.305 181.457 ;
     RECT  18.615 181.187 18.705 181.457 ;
     RECT  24.015 181.187 24.105 181.457 ;
     RECT  29.415 181.187 29.505 181.457 ;
     RECT  34.815 181.187 34.905 181.457 ;
     RECT  40.215 181.187 40.305 181.457 ;
     RECT  45.615 181.421 60.678 181.457 ;
     RECT  78.015 181.187 78.105 181.457 ;
     RECT  83.415 181.187 83.505 181.457 ;
     RECT  88.815 181.187 88.905 181.457 ;
     RECT  94.215 181.187 94.305 181.457 ;
     RECT  99.615 181.187 99.705 181.457 ;
     RECT  105.015 181.187 105.105 181.457 ;
     RECT  110.415 181.187 110.505 181.457 ;
     RECT  115.815 181.187 115.905 181.457 ;
     RECT  121.215 181.187 121.305 181.457 ;
     RECT  126.615 181.187 126.705 181.457 ;
     RECT  45.756 181.457 60.678 181.469 ;
     RECT  45.756 181.469 56.97 181.565 ;
     RECT  71.46 181.373 73.602 181.661 ;
     RECT  71.46 181.661 72.306 181.757 ;
     RECT  46.044 181.565 56.97 181.805 ;
     RECT  57.816 181.469 60.678 181.805 ;
     RECT  61.416 181.421 70.47 181.805 ;
     RECT  71.46 181.757 72.198 181.805 ;
     RECT  73.044 181.661 73.602 181.805 ;
     RECT  74.34 181.421 74.358 181.805 ;
     RECT  49.5 181.805 50.238 181.853 ;
     RECT  58.068 181.805 59.85 181.853 ;
     RECT  66.636 181.805 67.662 181.853 ;
     RECT  69.948 181.805 70.47 181.901 ;
     RECT  49.5 181.853 49.518 182.381 ;
     RECT  58.14 181.853 59.85 182.381 ;
     RECT  51.552 181.805 52.794 182.429 ;
     RECT  54.108 181.805 54.63 182.429 ;
     RECT  56.34 181.805 56.358 182.429 ;
     RECT  58.68 182.381 59.85 182.429 ;
     RECT  61.416 181.805 61.434 182.429 ;
     RECT  71.46 181.805 71.478 182.429 ;
     RECT  58.68 182.429 58.698 182.957 ;
     RECT  62.676 181.805 62.694 182.957 ;
     RECT  70.452 181.901 70.47 182.957 ;
     RECT  51.552 182.429 51.858 183.005 ;
     RECT  67.176 181.853 67.662 183.005 ;
     RECT  51.552 183.005 51.57 183.485 ;
     RECT  52.668 182.429 52.686 183.485 ;
     RECT  67.644 183.005 67.662 183.485 ;
     RECT  74.34 183.259 74.358 183.485 ;
    LAYER M4 ;
     RECT  2.408 2.148 2.512 181.452 ;
     RECT  2.512 2.418 2.704 181.182 ;
     RECT  7.808 2.148 7.912 181.452 ;
     RECT  7.912 2.418 8.104 181.182 ;
     RECT  13.208 2.148 13.312 181.452 ;
     RECT  13.312 2.418 13.504 181.182 ;
     RECT  18.608 2.148 18.712 181.452 ;
     RECT  18.712 2.418 18.904 181.182 ;
     RECT  24.008 2.148 24.112 181.452 ;
     RECT  24.112 2.418 24.304 181.182 ;
     RECT  29.408 2.148 29.512 181.452 ;
     RECT  29.512 2.418 29.704 181.182 ;
     RECT  34.808 2.148 34.912 181.452 ;
     RECT  34.912 2.418 35.104 181.182 ;
     RECT  36.637 10.8 36.853 10.824 ;
     RECT  36.853 10.8 37.141 11.976 ;
     RECT  37.141 10.8 37.187 12.744 ;
     RECT  37.069 1.104 37.213 1.128 ;
     RECT  37.187 12.72 37.228 12.744 ;
     RECT  37.213 1.056 37.285 1.128 ;
     RECT  37.033 13.776 37.357 13.8 ;
     RECT  37.285 0.096 37.369 1.128 ;
     RECT  37.369 1.056 37.427 1.128 ;
     RECT  37.141 6.384 37.429 6.408 ;
     RECT  37.357 13.776 37.501 14.28 ;
     RECT  37.429 6.384 37.532 7.368 ;
     RECT  37.465 1.728 37.548 1.752 ;
     RECT  37.187 10.8 37.571 11.448 ;
     RECT  37.532 5.616 37.619 7.368 ;
     RECT  37.548 1.728 37.681 1.8 ;
     RECT  37.669 2.88 37.681 2.904 ;
     RECT  37.501 13.68 37.757 14.28 ;
     RECT  37.525 8.976 37.969 9 ;
     RECT  37.619 5.664 38.195 7.368 ;
     RECT  38.195 6.192 38.197 7.368 ;
     RECT  37.969 8.544 38.197 9 ;
     RECT  38.197 6.192 38.243 9 ;
     RECT  37.681 1.728 38.293 2.904 ;
     RECT  38.243 6.24 38.405 9 ;
     RECT  38.405 6.288 38.581 9 ;
     RECT  38.293 1.728 38.617 3.768 ;
     RECT  37.571 11.04 38.689 11.448 ;
     RECT  38.581 6.288 38.723 9.144 ;
     RECT  38.723 6.288 38.729 8.856 ;
     RECT  38.257 13.536 38.761 13.56 ;
     RECT  38.725 9.888 38.773 9.912 ;
     RECT  38.689 11.04 38.773 11.928 ;
     RECT  38.617 1.728 38.797 4.536 ;
     RECT  38.761 13.536 38.801 13.656 ;
     RECT  38.729 6.288 38.909 7.464 ;
     RECT  38.773 9.888 38.909 11.928 ;
     RECT  38.909 9.888 39.089 10.872 ;
     RECT  38.941 0.096 39.155 0.12 ;
     RECT  38.797 1.728 39.157 5.16 ;
     RECT  39.157 1.104 39.625 5.16 ;
     RECT  38.909 6.288 39.625 7.416 ;
     RECT  38.801 13.632 39.769 13.656 ;
     RECT  39.625 1.104 39.877 7.416 ;
     RECT  39.877 0.144 40.067 7.416 ;
     RECT  40.067 0.24 40.208 7.416 ;
     RECT  38.729 8.832 40.208 8.856 ;
     RECT  39.089 9.888 40.208 9.912 ;
     RECT  38.909 11.904 40.208 11.928 ;
     RECT  39.769 13.056 40.208 13.656 ;
     RECT  40.208 0.24 40.211 181.452 ;
     RECT  40.211 0.528 40.312 181.452 ;
     RECT  40.312 0.528 40.504 181.182 ;
     RECT  40.504 8.448 40.645 14.808 ;
     RECT  40.645 8.448 40.997 14.28 ;
     RECT  40.504 0.528 41.027 7.464 ;
     RECT  41.027 0.528 41.033 0.6 ;
     RECT  40.504 17.808 41.068 17.832 ;
     RECT  40.997 8.736 41.429 14.28 ;
     RECT  41.317 0.096 41.555 0.168 ;
     RECT  41.429 8.736 41.717 12.168 ;
     RECT  41.717 12 41.941 12.168 ;
     RECT  41.941 12 41.987 12.072 ;
     RECT  41.717 8.736 41.989 10.872 ;
     RECT  41.987 12 42.005 12.024 ;
     RECT  41.027 1.728 42.073 7.464 ;
     RECT  41.989 8.448 42.073 10.872 ;
     RECT  42.073 1.728 42.083 10.872 ;
     RECT  40.504 55.296 42.284 55.32 ;
     RECT  42.284 55.296 42.371 55.608 ;
     RECT  41.555 0.144 42.467 0.168 ;
     RECT  41.429 13.296 42.649 14.28 ;
     RECT  42.371 55.296 42.653 55.32 ;
     RECT  42.083 1.728 42.725 10.728 ;
     RECT  42.649 13.248 42.757 14.28 ;
     RECT  42.685 15.984 42.829 16.008 ;
     RECT  42.757 13.056 43.009 14.28 ;
     RECT  42.829 15.984 43.009 16.056 ;
     RECT  42.764 11.904 43.045 11.928 ;
     RECT  43.009 13.056 43.045 16.056 ;
     RECT  43.045 0.096 43.157 0.12 ;
     RECT  43.045 11.904 43.301 16.056 ;
     RECT  42.725 2.304 43.333 10.728 ;
     RECT  43.301 11.904 43.333 16.008 ;
     RECT  43.441 17.04 43.657 17.064 ;
     RECT  43.333 2.304 43.717 16.008 ;
     RECT  43.657 17.04 43.769 17.64 ;
     RECT  43.717 1.728 43.877 16.008 ;
     RECT  42.325 57.312 43.913 57.336 ;
     RECT  43.981 20.496 44.065 20.52 ;
     RECT  44.005 150.384 44.156 150.408 ;
     RECT  44.125 57.36 44.197 57.384 ;
     RECT  44.156 150.384 44.243 150.456 ;
     RECT  44.081 0.576 44.245 0.6 ;
     RECT  43.877 2.208 44.341 16.008 ;
     RECT  44.243 150.384 44.525 150.408 ;
     RECT  44.245 0.144 44.531 0.6 ;
     RECT  44.773 1.152 44.885 1.176 ;
     RECT  44.837 0.096 44.921 0.12 ;
     RECT  44.341 2.208 45.061 16.056 ;
     RECT  45.205 151.296 45.308 151.32 ;
     RECT  44.197 174 45.349 174.024 ;
     RECT  43.769 17.616 45.493 17.64 ;
     RECT  44.989 18.816 45.493 18.84 ;
     RECT  45.061 1.728 45.608 16.056 ;
     RECT  45.493 17.616 45.608 18.84 ;
     RECT  45.164 21.312 45.608 21.336 ;
     RECT  44.197 57.36 45.608 57.432 ;
     RECT  45.308 151.296 45.608 151.608 ;
     RECT  45.349 173.52 45.608 174.024 ;
     RECT  45.608 1.728 45.745 181.452 ;
     RECT  45.745 1.728 45.904 181.56 ;
     RECT  45.637 0.48 45.925 0.552 ;
     RECT  45.925 0.24 45.973 0.552 ;
     RECT  45.904 181.248 45.989 181.56 ;
     RECT  45.973 0.144 46.163 0.552 ;
     RECT  45.904 178.944 46.333 180.168 ;
     RECT  45.904 1.728 46.355 19.656 ;
     RECT  45.904 151.488 46.54 151.608 ;
     RECT  45.904 92.448 46.691 92.616 ;
     RECT  45.904 57.36 46.729 57.432 ;
     RECT  46.261 183.408 46.739 183.432 ;
     RECT  45.904 21.552 46.793 22.488 ;
     RECT  46.54 151.488 46.793 151.512 ;
     RECT  46.355 6.816 46.865 19.656 ;
     RECT  46.333 179.232 46.931 180.168 ;
     RECT  46.793 21.552 47.027 22.44 ;
     RECT  46.865 19.248 47.077 19.656 ;
     RECT  46.981 0.576 47.117 0.6 ;
     RECT  47.077 19.248 47.16 20.568 ;
     RECT  47.027 21.552 47.16 22.344 ;
     RECT  46.865 6.816 47.189 18.264 ;
     RECT  45.989 181.248 47.213 181.8 ;
     RECT  47.213 180.72 47.297 181.8 ;
     RECT  46.355 1.728 47.401 5.784 ;
     RECT  47.189 6.816 47.401 16.056 ;
     RECT  46.931 179.232 47.477 179.352 ;
     RECT  47.16 19.248 47.549 22.344 ;
     RECT  47.401 1.728 47.557 16.056 ;
     RECT  45.904 176.352 47.557 176.376 ;
     RECT  47.557 176.352 47.581 176.712 ;
     RECT  47.549 19.248 47.585 21.576 ;
     RECT  47.557 146.448 47.644 146.472 ;
     RECT  47.564 143.616 47.651 143.64 ;
     RECT  47.477 179.328 47.657 179.352 ;
     RECT  47.557 1.152 47.843 16.056 ;
     RECT  45.904 173.52 47.869 174.552 ;
     RECT  47.581 176.352 47.869 177.288 ;
     RECT  47.189 17.04 47.933 18.264 ;
     RECT  47.585 19.248 47.933 21.144 ;
     RECT  47.933 17.04 47.939 21.144 ;
     RECT  47.869 173.52 47.981 177.288 ;
     RECT  47.939 17.04 48.053 20.52 ;
     RECT  48.193 143.088 48.277 143.112 ;
     RECT  47.981 177.264 48.305 177.288 ;
     RECT  47.843 1.728 48.337 16.056 ;
     RECT  48.053 17.04 48.337 20.136 ;
     RECT  48.337 1.728 48.341 20.136 ;
     RECT  48.181 145.296 48.373 145.32 ;
     RECT  46.729 57.408 48.419 57.432 ;
     RECT  48.373 145.296 48.467 145.944 ;
     RECT  48.481 177.984 48.553 178.008 ;
     RECT  48.553 177.984 48.659 178.68 ;
     RECT  48.341 2.88 48.665 20.136 ;
     RECT  48.467 145.296 48.737 145.32 ;
     RECT  48.665 2.88 48.803 18.552 ;
     RECT  47.297 181.248 48.877 181.8 ;
     RECT  48.697 27.36 48.947 27.384 ;
     RECT  47.981 173.52 48.985 175.608 ;
     RECT  48.665 20.112 48.989 20.136 ;
     RECT  48.997 183.216 49.093 183.24 ;
     RECT  48.877 180.72 49.139 181.8 ;
     RECT  47.461 0.096 49.189 0.12 ;
     RECT  49.093 183.216 49.283 183.336 ;
     RECT  49.189 0.096 49.385 0.6 ;
     RECT  48.341 1.728 49.457 1.848 ;
     RECT  49.139 181.248 49.489 181.8 ;
     RECT  45.904 111.984 49.573 112.008 ;
     RECT  49.457 1.776 49.601 1.848 ;
     RECT  49.573 111.984 49.619 112.152 ;
     RECT  49.489 181.248 49.619 182.376 ;
     RECT  48.803 2.88 49.669 10.296 ;
     RECT  48.803 11.424 49.813 18.552 ;
     RECT  49.669 2.304 49.853 10.296 ;
     RECT  49.853 9.216 49.957 10.296 ;
     RECT  49.813 11.28 49.957 18.552 ;
     RECT  48.985 173.52 50.053 176.376 ;
     RECT  49.619 181.248 50.387 181.848 ;
     RECT  50.173 179.472 50.684 179.496 ;
     RECT  49.957 9.216 50.785 18.552 ;
     RECT  49.853 2.304 50.821 7.992 ;
     RECT  50.785 9.216 50.821 18.6 ;
     RECT  50.684 179.472 50.869 179.784 ;
     RECT  50.821 2.256 51.008 7.992 ;
     RECT  50.821 9.072 51.008 18.6 ;
     RECT  50.209 25.68 51.008 25.704 ;
     RECT  46.691 92.448 51.008 92.472 ;
     RECT  49.619 112.128 51.008 112.152 ;
     RECT  49.957 115.152 51.008 115.176 ;
     RECT  50.053 173.52 51.008 176.856 ;
     RECT  48.659 177.984 51.008 178.008 ;
     RECT  50.869 179.472 51.008 180.024 ;
     RECT  50.387 181.248 51.008 181.8 ;
     RECT  49.385 0.096 51.059 0.552 ;
     RECT  51.008 2.148 51.205 181.8 ;
     RECT  50.869 183.408 51.301 183.432 ;
     RECT  51.205 1.728 51.304 181.8 ;
     RECT  51.304 177.216 51.509 177.912 ;
     RECT  51.059 0.096 51.539 0.456 ;
     RECT  51.301 183.408 51.581 183.48 ;
     RECT  51.304 144.24 51.617 145.896 ;
     RECT  51.617 144.24 51.635 145.368 ;
     RECT  51.304 179.376 51.635 179.544 ;
     RECT  51.509 177.84 51.661 177.912 ;
     RECT  51.304 139.104 51.683 139.56 ;
     RECT  51.304 171.024 51.683 171.048 ;
     RECT  51.635 179.52 51.689 179.544 ;
     RECT  51.304 181.248 51.757 181.8 ;
     RECT  51.304 115.68 51.769 115.704 ;
     RECT  51.757 181.248 51.829 182.424 ;
     RECT  51.581 183.408 51.829 183.432 ;
     RECT  51.829 181.248 51.923 183.432 ;
     RECT  51.304 1.728 51.941 18.792 ;
     RECT  51.635 145.344 51.941 145.368 ;
     RECT  51.683 139.104 51.985 139.128 ;
     RECT  51.635 144.24 52.057 144.264 ;
     RECT  51.941 1.728 52.163 8.664 ;
     RECT  51.304 149.28 52.259 149.304 ;
     RECT  51.661 177.84 52.259 177.864 ;
     RECT  51.941 9.696 52.297 18.792 ;
     RECT  52.297 9.696 52.381 19.368 ;
     RECT  52.309 149.04 52.517 149.064 ;
     RECT  51.539 0.096 52.549 0.36 ;
     RECT  51.304 92.448 52.549 92.472 ;
     RECT  52.613 183.456 52.697 183.48 ;
     RECT  52.381 9.696 52.813 19.32 ;
     RECT  52.549 0.096 52.877 0.6 ;
     RECT  52.789 176.688 52.981 176.712 ;
     RECT  52.163 1.728 53.021 8.232 ;
     RECT  52.94 180.144 53.027 180.168 ;
     RECT  51.923 181.248 53.075 182.424 ;
     RECT  51.304 172.704 53.129 175.416 ;
     RECT  53.129 173.52 53.161 175.416 ;
     RECT  52.981 176.688 53.237 177.24 ;
     RECT  53.161 173.52 53.273 175.56 ;
     RECT  53.273 173.856 53.525 175.56 ;
     RECT  53.305 25.632 53.651 25.656 ;
     RECT  53.593 177.84 53.653 177.864 ;
     RECT  51.304 112.128 53.809 112.152 ;
     RECT  53.809 112.128 53.849 112.392 ;
     RECT  53.653 177.84 53.893 178.44 ;
     RECT  53.893 177.84 53.979 178.968 ;
     RECT  52.877 0.096 54.029 0.12 ;
     RECT  53.525 175.536 54.061 175.56 ;
     RECT  53.237 176.688 54.061 176.712 ;
     RECT  53.525 173.856 54.065 174.552 ;
     RECT  52.813 9.936 54.085 19.32 ;
     RECT  54.085 9.12 54.097 19.32 ;
     RECT  53.075 181.248 54.097 181.8 ;
     RECT  53.021 1.728 54.205 8.04 ;
     RECT  54.097 9.072 54.205 19.32 ;
     RECT  54.205 1.728 54.353 19.32 ;
     RECT  54.061 175.536 54.38 176.712 ;
     RECT  53.979 177.84 54.38 179.016 ;
     RECT  54.38 175.536 54.565 179.016 ;
     RECT  54.169 180 54.565 180.024 ;
     RECT  54.565 175.536 54.611 180.024 ;
     RECT  54.611 175.536 54.745 179.064 ;
     RECT  54.353 1.728 54.748 16.536 ;
     RECT  54.353 17.52 54.749 19.32 ;
     RECT  54.748 1.728 54.785 9.96 ;
     RECT  54.097 181.248 54.803 182.424 ;
     RECT  54.745 0.576 54.829 0.6 ;
     RECT  54.748 10.992 54.893 16.536 ;
     RECT  54.749 17.664 54.893 19.32 ;
     RECT  54.661 180.144 55.169 180.168 ;
     RECT  54.803 181.248 55.169 181.8 ;
     RECT  53.849 112.368 55.357 112.392 ;
     RECT  55.357 111.744 55.441 112.392 ;
     RECT  54.065 173.856 55.532 174.408 ;
     RECT  54.745 175.392 55.532 179.064 ;
     RECT  54.893 17.712 55.717 19.32 ;
     RECT  55.532 173.856 55.765 179.064 ;
     RECT  55.169 180.144 55.765 181.8 ;
     RECT  54.893 11.232 56.005 16.536 ;
     RECT  56.005 10.992 56.113 16.536 ;
     RECT  55.213 0.096 56.149 0.12 ;
     RECT  55.765 173.856 56.185 181.8 ;
     RECT  56.185 173.136 56.329 181.8 ;
     RECT  54.785 1.728 56.408 9.816 ;
     RECT  56.113 10.944 56.408 16.536 ;
     RECT  55.717 17.712 56.408 19.368 ;
     RECT  52.549 92.448 56.408 92.76 ;
     RECT  55.381 97.536 56.408 97.56 ;
     RECT  55.441 112.272 56.408 112.392 ;
     RECT  56.329 173.136 56.408 182.424 ;
     RECT  56.149 0.096 56.435 0.552 ;
     RECT  56.408 1.728 56.485 182.424 ;
     RECT  56.485 1.152 56.531 182.424 ;
     RECT  56.531 1.152 56.704 181.8 ;
     RECT  56.581 183.408 56.773 183.432 ;
     RECT  56.704 1.152 56.837 9.912 ;
     RECT  56.773 183.312 56.867 183.432 ;
     RECT  56.837 1.2 56.909 9.912 ;
     RECT  56.435 0.096 56.963 0.168 ;
     RECT  56.867 183.312 56.963 183.336 ;
     RECT  56.704 175.056 57.05 179.64 ;
     RECT  56.909 1.728 57.089 9.912 ;
     RECT  57.05 175.056 57.133 179.592 ;
     RECT  57.133 175.056 57.155 179.544 ;
     RECT  56.704 10.944 57.197 19.608 ;
     RECT  56.704 103.728 57.197 104.28 ;
     RECT  56.963 0.096 57.203 0.12 ;
     RECT  57.197 103.728 57.203 103.752 ;
     RECT  57.155 175.056 57.395 176.136 ;
     RECT  57.089 3.024 57.413 9.912 ;
     RECT  57.413 3.024 57.421 9.816 ;
     RECT  57.421 3.024 57.485 3.816 ;
     RECT  56.704 106.032 57.529 106.056 ;
     RECT  57.155 177.456 57.539 179.544 ;
     RECT  56.704 180.72 57.565 181.8 ;
     RECT  57.197 10.944 57.593 11.4 ;
     RECT  57.197 12.48 57.629 19.608 ;
     RECT  57.539 177.456 57.629 178.44 ;
     RECT  57.593 10.944 57.701 11.352 ;
     RECT  56.704 107.184 57.709 107.208 ;
     RECT  57.629 12.528 57.841 19.608 ;
     RECT  57.421 5.136 57.881 9.816 ;
     RECT  57.841 12.528 57.989 19.8 ;
     RECT  57.565 181.248 58.057 181.8 ;
     RECT  56.704 173.136 58.061 173.16 ;
     RECT  58.057 181.248 58.085 181.848 ;
     RECT  57.539 179.52 58.105 179.544 ;
     RECT  57.881 5.136 58.169 9.768 ;
     RECT  58.085 181.248 58.169 182.376 ;
     RECT  57.089 1.728 58.237 1.752 ;
     RECT  58.169 181.248 58.259 181.848 ;
     RECT  58.169 5.952 58.277 9.768 ;
     RECT  57.395 175.056 58.373 175.416 ;
     RECT  58.277 6.048 58.385 9.768 ;
     RECT  58.309 145.248 58.405 145.272 ;
     RECT  58.373 175.056 58.417 175.608 ;
     RECT  58.237 1.728 58.489 2.28 ;
     RECT  58.405 145.248 58.492 145.896 ;
     RECT  58.417 175.056 58.501 176.184 ;
     RECT  57.701 10.944 58.525 11.256 ;
     RECT  58.385 6.048 58.54 8.52 ;
     RECT  58.54 6.048 58.601 8.328 ;
     RECT  58.525 4.464 58.673 4.488 ;
     RECT  58.501 0.576 58.709 0.6 ;
     RECT  57.989 12.528 58.709 18.024 ;
     RECT  58.492 145.248 58.745 145.848 ;
     RECT  58.655 182.928 58.773 182.952 ;
     RECT  58.489 1.728 58.789 2.664 ;
     RECT  57.629 177.456 58.885 177.48 ;
     RECT  58.709 12.528 58.925 17.736 ;
     RECT  58.925 17.712 58.961 17.736 ;
     RECT  57.989 19.776 58.993 19.8 ;
     RECT  58.993 18.816 59.033 19.8 ;
     RECT  58.789 1.104 59.077 2.664 ;
     RECT  58.525 10.848 59.101 11.256 ;
     RECT  58.925 12.528 59.101 16.536 ;
     RECT  59.101 10.848 59.105 16.536 ;
     RECT  59.077 1.104 59.213 3 ;
     RECT  58.259 181.248 59.228 181.8 ;
     RECT  59.033 18.816 59.285 18.936 ;
     RECT  58.385 9.648 59.317 9.768 ;
     RECT  59.105 10.848 59.317 16.44 ;
     RECT  58.501 175.056 59.357 175.416 ;
     RECT  59.317 9.648 59.537 16.44 ;
     RECT  59.213 1.104 59.603 2.472 ;
     RECT  58.601 6.24 59.717 8.328 ;
     RECT  59.537 11.376 59.897 16.44 ;
     RECT  59.228 181.248 59.987 182.424 ;
     RECT  59.717 6.288 60.133 8.328 ;
     RECT  59.537 9.648 60.133 10.056 ;
     RECT  59.357 175.392 60.145 175.416 ;
     RECT  58.885 176.64 60.145 177.48 ;
     RECT  60.133 6.288 60.213 10.056 ;
     RECT  60.14 145.872 60.227 145.896 ;
     RECT  60.145 175.392 60.229 177.48 ;
     RECT  59.897 11.664 60.289 16.44 ;
     RECT  60.277 3.984 60.361 4.008 ;
     RECT  60.361 3.984 60.433 4.104 ;
     RECT  60.253 5.136 60.433 5.16 ;
     RECT  59.603 1.728 60.469 2.472 ;
     RECT  60.229 176.64 60.505 177.48 ;
     RECT  60.325 145.824 60.509 145.848 ;
     RECT  60.469 1.728 60.517 2.952 ;
     RECT  60.433 3.984 60.517 5.16 ;
     RECT  60.289 11.664 60.653 17.112 ;
     RECT  60.677 0.096 60.761 0.12 ;
     RECT  60.213 10.032 60.829 10.056 ;
     RECT  59.749 173.664 61.081 173.688 ;
     RECT  60.229 175.392 61.081 175.416 ;
     RECT  59.821 18.192 61.117 18.216 ;
     RECT  60.213 6.288 61.225 8.76 ;
     RECT  60.829 10.032 61.225 10.392 ;
     RECT  60.517 1.728 61.34 5.16 ;
     RECT  61.225 6.288 61.34 10.392 ;
     RECT  59.987 181.248 61.405 181.8 ;
     RECT  61.117 18.192 61.441 18.84 ;
     RECT  61.405 181.248 61.477 182.424 ;
     RECT  60.505 176.64 61.525 177.96 ;
     RECT  60.325 179.472 61.525 179.496 ;
     RECT  61.081 173.664 61.573 175.416 ;
     RECT  61.525 176.64 61.573 179.496 ;
     RECT  61.477 180.72 61.573 182.424 ;
     RECT  61.573 173.664 61.619 182.424 ;
     RECT  61.292 141.168 61.621 141.192 ;
     RECT  61.628 0.528 61.669 0.552 ;
     RECT  61.34 1.728 61.669 10.392 ;
     RECT  61.621 149.184 61.669 149.208 ;
     RECT  61.669 1.728 61.765 10.92 ;
     RECT  60.653 11.952 61.765 17.112 ;
     RECT  61.765 1.728 61.808 17.112 ;
     RECT  61.441 18.192 61.808 19.032 ;
     RECT  57.925 31.104 61.808 31.128 ;
     RECT  56.704 92.448 61.808 92.76 ;
     RECT  56.704 97.536 61.808 97.56 ;
     RECT  61.621 140.784 61.808 141.192 ;
     RECT  61.669 148.56 61.808 149.208 ;
     RECT  61.619 173.664 61.808 182.328 ;
     RECT  61.669 0.528 61.811 0.648 ;
     RECT  61.808 1.728 62.003 182.328 ;
     RECT  62.003 1.728 62.104 181.8 ;
     RECT  62.104 175.008 62.165 175.416 ;
     RECT  62.104 179.472 62.291 180.168 ;
     RECT  62.104 1.728 62.389 11.448 ;
     RECT  62.389 1.728 62.435 5.208 ;
     RECT  62.104 12.768 62.453 13.08 ;
     RECT  62.104 176.688 62.483 178.44 ;
     RECT  61.621 183.408 62.579 183.432 ;
     RECT  62.483 177.264 62.675 178.44 ;
     RECT  62.149 0.144 62.819 0.168 ;
     RECT  62.665 182.928 62.867 182.952 ;
     RECT  62.104 145.248 63.004 145.8 ;
     RECT  62.104 139.008 63.011 139.56 ;
     RECT  62.104 169.296 63.037 169.896 ;
     RECT  63.037 169.872 63.073 169.896 ;
     RECT  62.291 179.472 63.1 179.496 ;
     RECT  62.453 12.768 63.133 13.032 ;
     RECT  62.675 177.456 63.155 178.44 ;
     RECT  63.133 12.576 63.205 13.032 ;
     RECT  62.165 175.008 63.289 175.08 ;
     RECT  62.104 148.176 63.349 149.304 ;
     RECT  62.435 1.728 63.397 5.16 ;
     RECT  62.389 6.24 63.397 11.448 ;
     RECT  63.349 20.592 63.397 20.616 ;
     RECT  63.205 12.528 63.421 13.032 ;
     RECT  62.104 14.448 63.421 19.128 ;
     RECT  63.205 143.616 63.445 143.64 ;
     RECT  63.541 140.784 63.548 140.808 ;
     RECT  63.397 1.728 63.565 11.448 ;
     RECT  63.445 143.088 63.605 143.64 ;
     RECT  63.349 147.648 63.605 149.304 ;
     RECT  63.548 140.784 63.635 141.336 ;
     RECT  63.349 172.128 63.635 172.152 ;
     RECT  63.565 1.728 63.781 11.496 ;
     RECT  63.421 12.528 63.781 19.128 ;
     RECT  63.011 139.008 63.889 139.128 ;
     RECT  63.004 145.248 63.889 145.368 ;
     RECT  63.635 140.784 63.929 140.808 ;
     RECT  63.605 143.088 63.929 143.112 ;
     RECT  63.889 138.528 63.973 139.128 ;
     RECT  63.889 144.768 64.019 145.368 ;
     RECT  63.397 20.208 64.021 20.616 ;
     RECT  64.019 144.768 64.115 144.792 ;
     RECT  64.069 179.52 64.153 179.544 ;
     RECT  63.877 0.576 64.165 0.6 ;
     RECT  63.097 176.112 64.249 176.136 ;
     RECT  63.605 147.648 64.261 149.112 ;
     RECT  63.155 177.456 64.285 178.392 ;
     RECT  63.973 138.528 64.307 138.552 ;
     RECT  63.781 1.728 64.309 19.128 ;
     RECT  64.021 20.208 64.309 21.384 ;
     RECT  64.285 177.456 64.309 178.44 ;
     RECT  64.249 176.112 64.357 176.184 ;
     RECT  63.133 173.232 64.397 173.256 ;
     RECT  64.309 1.728 64.441 21.384 ;
     RECT  64.357 176.112 64.441 176.232 ;
     RECT  63.289 175.008 64.573 175.032 ;
     RECT  64.441 176.112 64.573 176.136 ;
     RECT  64.261 147.6 64.652 149.112 ;
     RECT  64.652 147.6 64.693 149.304 ;
     RECT  64.609 173.808 64.693 173.832 ;
     RECT  64.309 177.264 64.757 178.44 ;
     RECT  64.7 141.888 64.787 141.912 ;
     RECT  62.104 31.104 64.825 31.128 ;
     RECT  64.165 0.096 64.829 0.6 ;
     RECT  64.717 143.616 64.835 143.64 ;
     RECT  64.573 175.008 64.835 176.136 ;
     RECT  64.825 30.816 64.865 31.128 ;
     RECT  64.865 30.816 64.909 30.84 ;
     RECT  64.441 1.728 65.029 15.048 ;
     RECT  64.693 147.456 65.045 149.304 ;
     RECT  64.835 176.112 65.225 176.136 ;
     RECT  64.829 0.096 65.297 0.168 ;
     RECT  64.441 16.08 65.297 21.384 ;
     RECT  63.109 150.432 65.333 150.456 ;
     RECT  65.297 0.144 65.369 0.168 ;
     RECT  65.537 141.36 65.621 141.384 ;
     RECT  65.509 143.088 65.621 143.112 ;
     RECT  65.045 148.224 65.689 149.304 ;
     RECT  62.104 181.248 65.761 181.8 ;
     RECT  65.297 21.072 65.773 21.384 ;
     RECT  65.689 148.224 65.773 149.928 ;
     RECT  65.221 146.448 65.797 146.472 ;
     RECT  65.797 179.52 65.861 179.544 ;
     RECT  65.797 145.92 65.873 146.472 ;
     RECT  65.773 148.224 65.873 149.112 ;
     RECT  65.029 1.152 65.939 15.048 ;
     RECT  65.939 5.376 65.945 15.048 ;
     RECT  64.757 177.744 66.005 178.44 ;
     RECT  65.861 179.472 66.005 179.544 ;
     RECT  64.835 175.008 66.013 175.08 ;
     RECT  65.773 21.312 66.053 21.384 ;
     RECT  65.945 5.712 66.125 15.048 ;
     RECT  66.005 177.744 66.157 179.544 ;
     RECT  65.761 180.72 66.157 181.8 ;
     RECT  65.873 145.92 66.197 145.944 ;
     RECT  65.873 148.224 66.197 148.824 ;
     RECT  65.297 16.08 66.205 19.944 ;
     RECT  66.013 175.008 66.277 175.56 ;
     RECT  66.181 176.64 66.277 176.664 ;
     RECT  66.277 175.008 66.293 176.664 ;
     RECT  66.293 175.008 66.325 176.76 ;
     RECT  66.157 177.744 66.325 181.8 ;
     RECT  66.125 6 66.332 15.048 ;
     RECT  66.205 16.08 66.332 19.416 ;
     RECT  66.229 147.984 66.428 148.2 ;
     RECT  66.325 175.008 66.625 181.8 ;
     RECT  66.236 173.232 66.697 173.256 ;
     RECT  65.939 1.152 66.809 4.008 ;
     RECT  66.545 0.096 66.812 0.12 ;
     RECT  66.812 0.096 66.899 0.552 ;
     RECT  66.625 175.008 66.995 181.848 ;
     RECT  66.997 183.408 67.165 183.432 ;
     RECT  66.809 1.728 67.208 4.008 ;
     RECT  66.332 6 67.208 19.416 ;
     RECT  66.053 21.312 67.208 21.336 ;
     RECT  64.837 24.624 67.208 24.648 ;
     RECT  62.104 92.448 67.208 92.76 ;
     RECT  62.104 97.536 67.208 97.56 ;
     RECT  66.428 147.6 67.208 148.2 ;
     RECT  66.325 150.432 67.208 150.456 ;
     RECT  66.697 173.232 67.208 173.832 ;
     RECT  66.995 175.008 67.208 181.8 ;
     RECT  67.165 182.976 67.333 183.432 ;
     RECT  67.208 1.728 67.504 181.8 ;
     RECT  67.333 182.832 67.589 183.432 ;
     RECT  67.504 20.496 67.619 20.52 ;
     RECT  67.504 147.072 67.667 147.672 ;
     RECT  67.589 182.832 67.667 183.48 ;
     RECT  67.667 183.456 67.673 183.48 ;
     RECT  67.504 173.856 67.715 181.8 ;
     RECT  67.504 149.904 67.925 149.928 ;
     RECT  67.667 147.648 67.969 147.672 ;
     RECT  66.899 0.096 67.993 0.168 ;
     RECT  67.993 0.096 68.069 0.216 ;
     RECT  68.069 0.192 68.147 0.216 ;
     RECT  67.504 1.728 68.483 19.272 ;
     RECT  67.504 28.848 68.483 29.064 ;
     RECT  68.483 2.784 68.677 19.272 ;
     RECT  68.533 20.4 68.677 20.424 ;
     RECT  67.504 140.736 68.717 140.76 ;
     RECT  67.504 31.536 68.789 31.56 ;
     RECT  68.581 26.688 69.005 26.712 ;
     RECT  68.677 2.784 69.037 20.424 ;
     RECT  68.965 140.688 69.077 140.712 ;
     RECT  69.145 0.576 69.229 0.6 ;
     RECT  69.26 105.984 69.347 106.008 ;
     RECT  67.715 174.432 69.347 181.8 ;
     RECT  68.483 28.848 69.401 28.872 ;
     RECT  69.037 2.784 69.437 21.096 ;
     RECT  68.483 1.728 69.445 1.8 ;
     RECT  69.437 2.784 69.445 20.424 ;
     RECT  69.347 174.432 69.58 175.944 ;
     RECT  69.347 177.264 69.587 181.8 ;
     RECT  69.445 1.728 69.725 20.424 ;
     RECT  69.58 174.432 69.781 175.128 ;
     RECT  69.781 174.384 69.868 175.128 ;
     RECT  69.868 174.432 69.905 175.128 ;
     RECT  69.587 181.248 69.937 181.8 ;
     RECT  69.587 177.264 70.067 180.168 ;
     RECT  69.725 1.728 70.193 5.16 ;
     RECT  69.725 6.288 70.229 20.424 ;
     RECT  69.937 181.248 70.259 181.896 ;
     RECT  70.193 1.728 70.268 5.016 ;
     RECT  70.067 177.264 70.372 179.016 ;
     RECT  69.829 183.408 70.441 183.432 ;
     RECT  70.412 144.144 70.499 144.168 ;
     RECT  70.369 173.28 70.499 173.304 ;
     RECT  70.501 176.16 70.508 176.184 ;
     RECT  70.372 177.216 70.508 179.016 ;
     RECT  70.501 25.632 70.588 25.656 ;
     RECT  70.441 182.928 70.595 183.432 ;
     RECT  70.268 1.104 70.693 5.016 ;
     RECT  70.259 181.248 70.697 181.416 ;
     RECT  70.595 182.928 70.739 182.952 ;
     RECT  70.693 0.528 71.027 5.016 ;
     RECT  70.697 181.248 71.027 181.368 ;
     RECT  70.508 176.16 71.089 179.016 ;
     RECT  70.067 180.144 71.089 180.168 ;
     RECT  71.027 0.528 71.125 0.6 ;
     RECT  71.089 176.16 71.125 180.168 ;
     RECT  71.027 181.248 71.125 181.32 ;
     RECT  71.125 107.184 71.209 107.208 ;
     RECT  69.905 174.72 71.221 175.128 ;
     RECT  71.125 176.16 71.221 181.32 ;
     RECT  71.027 1.728 71.233 5.016 ;
     RECT  71.189 143.664 71.273 143.688 ;
     RECT  71.221 174.384 71.273 181.32 ;
     RECT  71.273 174.384 71.308 180.168 ;
     RECT  71.308 176.496 71.315 180.168 ;
     RECT  71.233 1.728 71.341 5.256 ;
     RECT  71.341 1.728 71.413 5.304 ;
     RECT  70.229 6.288 71.413 19.944 ;
     RECT  71.125 0.144 71.485 0.6 ;
     RECT  71.485 21.024 71.797 21.048 ;
     RECT  71.449 182.4 72.083 182.424 ;
     RECT  71.273 181.248 72.169 181.32 ;
     RECT  71.413 1.728 72.421 19.944 ;
     RECT  71.308 175.104 72.421 175.128 ;
     RECT  67.504 24.624 72.457 24.648 ;
     RECT  72.421 1.728 72.469 20.04 ;
     RECT  71.797 21.024 72.469 21.672 ;
     RECT  72.421 174.864 72.469 175.128 ;
     RECT  71.315 176.496 72.469 176.52 ;
     RECT  72.469 174.864 72.493 176.664 ;
     RECT  72.469 1.728 72.608 21.672 ;
     RECT  72.457 24.528 72.608 24.648 ;
     RECT  67.504 92.448 72.608 92.76 ;
     RECT  67.504 97.536 72.608 97.56 ;
     RECT  71.621 103.2 72.608 103.224 ;
     RECT  71.881 144.24 72.608 144.264 ;
     RECT  72.493 174.864 72.608 177.24 ;
     RECT  71.315 178.368 72.608 180.168 ;
     RECT  72.169 181.248 72.608 181.8 ;
     RECT  72.608 1.728 72.904 181.8 ;
     RECT  71.485 0.096 72.965 0.6 ;
     RECT  72.904 178.656 73.043 181.8 ;
     RECT  72.904 174.864 73.397 177.24 ;
     RECT  72.904 107.184 73.427 107.208 ;
     RECT  73.397 174.864 73.475 176.04 ;
     RECT  73.397 177.216 73.541 177.24 ;
     RECT  72.904 145.296 73.801 145.32 ;
     RECT  72.904 1.728 73.829 21.624 ;
     RECT  72.904 173.376 73.969 173.4 ;
     RECT  73.969 173.376 74.009 173.592 ;
     RECT  73.043 178.704 74.081 181.8 ;
     RECT  74.081 178.704 74.149 180.024 ;
     RECT  73.475 176.016 74.195 176.04 ;
     RECT  72.965 0.096 74.221 0.12 ;
     RECT  74.149 102.624 74.233 102.648 ;
     RECT  74.149 183.408 74.245 183.432 ;
     RECT  74.245 183.264 74.329 183.432 ;
     RECT  74.329 183.264 74.369 183.48 ;
     RECT  73.475 174.864 74.405 174.888 ;
     RECT  74.369 183.312 74.413 183.48 ;
     RECT  74.081 181.248 74.483 181.8 ;
     RECT  74.009 173.568 74.509 173.592 ;
     RECT  74.221 0.096 74.593 0.6 ;
     RECT  74.149 168.144 74.627 168.168 ;
     RECT  74.413 183.312 74.627 183.432 ;
     RECT  74.593 0.144 74.657 0.6 ;
     RECT  74.149 178.416 74.657 180.024 ;
     RECT  74.627 183.312 74.675 183.336 ;
     RECT  74.509 173.568 74.765 174.456 ;
     RECT  74.657 178.416 74.801 179.496 ;
     RECT  74.657 0.528 74.867 0.6 ;
     RECT  74.801 179.424 74.909 179.496 ;
     RECT  73.829 1.776 74.917 21.624 ;
     RECT  74.483 181.248 74.963 181.416 ;
     RECT  74.963 181.248 75.059 181.272 ;
     RECT  74.909 179.424 75.089 179.448 ;
     RECT  74.917 1.728 75.197 21.624 ;
     RECT  74.801 178.416 75.233 178.44 ;
     RECT  75.197 1.728 75.413 4.104 ;
     RECT  75.413 3.36 75.436 4.104 ;
     RECT  74.867 0.576 75.521 0.6 ;
     RECT  75.413 1.728 75.625 2.328 ;
     RECT  75.625 1.152 75.731 2.328 ;
     RECT  74.765 174.432 75.845 174.456 ;
     RECT  75.731 1.728 76.115 2.328 ;
     RECT  76.076 140.736 76.163 140.76 ;
     RECT  76.093 169.296 76.177 169.32 ;
     RECT  75.197 5.136 76.345 21.624 ;
     RECT  75.436 3.408 76.355 4.104 ;
     RECT  76.115 1.728 76.421 1.848 ;
     RECT  76.261 140.208 76.457 140.232 ;
     RECT  76.421 1.728 76.529 1.8 ;
     RECT  76.345 5.088 76.957 21.624 ;
     RECT  76.957 4.56 77.497 21.624 ;
     RECT  76.355 3.408 77.641 3.48 ;
     RECT  76.529 1.776 77.669 1.8 ;
     RECT  77.353 0.096 77.677 0.12 ;
     RECT  77.641 2.928 77.713 3.48 ;
     RECT  77.713 2.88 77.785 3.48 ;
     RECT  77.497 4.512 77.785 21.624 ;
     RECT  77.669 1.728 77.893 1.8 ;
     RECT  77.893 1.728 78.008 1.848 ;
     RECT  77.785 2.88 78.008 21.624 ;
     RECT  72.904 24.624 78.008 24.648 ;
     RECT  77.845 60.912 78.008 60.936 ;
     RECT  72.904 92.448 78.008 92.76 ;
     RECT  72.904 97.536 78.008 97.56 ;
     RECT  78.008 1.728 78.112 181.452 ;
     RECT  78.112 1.728 78.304 181.182 ;
     RECT  78.304 24.624 78.419 25.08 ;
     RECT  78.304 60.432 78.445 60.456 ;
     RECT  77.677 0.096 78.515 0.552 ;
     RECT  78.515 0.096 78.563 0.36 ;
     RECT  78.563 0.096 79.481 0.12 ;
     RECT  78.304 1.728 79.58 20.712 ;
     RECT  79.58 1.104 79.667 20.712 ;
     RECT  79.667 1.728 79.813 20.712 ;
     RECT  79.813 1.728 79.9 21.144 ;
     RECT  79.9 1.728 79.985 20.712 ;
     RECT  79.985 1.728 80.345 4.056 ;
     RECT  80.345 1.824 80.381 4.056 ;
     RECT  80.389 0.576 80.677 0.6 ;
     RECT  80.381 2.208 81.349 4.056 ;
     RECT  79.985 5.088 81.349 20.712 ;
     RECT  78.304 92.448 81.425 92.76 ;
     RECT  81.349 2.208 81.493 20.712 ;
     RECT  80.677 0.144 81.521 0.6 ;
     RECT  81.493 2.208 81.577 21.144 ;
     RECT  81.577 2.208 81.629 20.712 ;
     RECT  81.521 0.096 81.637 0.6 ;
     RECT  81.629 1.728 81.637 20.712 ;
     RECT  81.425 92.448 81.749 92.472 ;
     RECT  81.637 0.096 81.779 20.712 ;
     RECT  78.419 25.056 82.309 25.08 ;
     RECT  82.309 24.864 82.355 25.08 ;
     RECT  81.779 0.096 82.547 0.552 ;
     RECT  82.547 0.096 82.643 0.504 ;
     RECT  82.556 22.128 83.173 22.152 ;
     RECT  81.779 1.728 83.408 20.712 ;
     RECT  83.173 21.888 83.408 22.152 ;
     RECT  82.355 24.864 83.408 24.888 ;
     RECT  82.309 27.984 83.408 28.008 ;
     RECT  78.304 97.536 83.408 97.56 ;
     RECT  83.408 1.728 83.512 181.452 ;
     RECT  83.512 1.728 83.704 181.182 ;
     RECT  83.704 1.728 83.843 20.136 ;
     RECT  82.643 0.096 83.869 0.264 ;
     RECT  83.843 1.728 83.905 20.04 ;
     RECT  83.869 0.096 84.133 0.552 ;
     RECT  83.905 1.68 84.133 20.04 ;
     RECT  84.133 0.096 84.305 20.04 ;
     RECT  84.305 1.68 84.371 20.04 ;
     RECT  84.305 0.096 84.593 0.552 ;
     RECT  84.593 0.144 84.851 0.552 ;
     RECT  84.371 1.728 85.241 20.04 ;
     RECT  84.851 0.144 86.021 0.168 ;
     RECT  85.241 1.728 86.033 19.752 ;
     RECT  86.033 1.728 86.317 4.056 ;
     RECT  86.021 0.096 86.425 0.168 ;
     RECT  86.317 1.152 86.425 4.056 ;
     RECT  86.033 5.088 86.753 19.752 ;
     RECT  86.425 0.096 87.289 4.056 ;
     RECT  86.753 5.088 87.289 19.272 ;
     RECT  87.289 0.096 87.617 19.272 ;
     RECT  87.617 0.144 87.923 19.272 ;
     RECT  87.923 0.144 88.613 0.168 ;
     RECT  88.613 0.096 88.697 0.168 ;
     RECT  87.923 1.152 88.808 19.272 ;
     RECT  83.704 28.128 88.808 28.152 ;
     RECT  83.704 97.536 88.808 97.56 ;
     RECT  88.808 1.152 88.912 181.452 ;
     RECT  88.912 1.152 88.933 181.182 ;
     RECT  88.933 0.192 89.104 181.182 ;
     RECT  89.104 0.192 89.219 17.496 ;
     RECT  89.219 0.192 89.363 17.448 ;
     RECT  89.104 27.936 89.381 27.96 ;
     RECT  89.363 1.104 90.137 17.448 ;
     RECT  90.085 0.096 90.245 0.12 ;
     RECT  90.137 1.104 90.419 3.528 ;
     RECT  89.104 18.48 90.421 19.272 ;
     RECT  90.137 4.56 90.601 17.448 ;
     RECT  90.421 18.48 90.601 19.416 ;
     RECT  90.419 1.152 91.141 3.528 ;
     RECT  90.601 4.56 91.141 19.416 ;
     RECT  91.141 1.152 91.253 19.416 ;
     RECT  91.253 4.512 91.541 19.416 ;
     RECT  91.541 11.088 91.757 19.416 ;
     RECT  91.757 11.088 91.973 19.272 ;
     RECT  91.973 13.104 92.009 19.272 ;
     RECT  92.009 13.104 92.189 19.128 ;
     RECT  91.253 1.152 92.243 3.432 ;
     RECT  92.189 13.488 92.261 19.128 ;
     RECT  91.541 4.512 92.297 9.912 ;
     RECT  91.973 11.088 92.369 11.928 ;
     RECT  92.261 13.488 92.369 17.64 ;
     RECT  92.297 4.992 92.387 6.84 ;
     RECT  92.369 13.584 92.477 17.64 ;
     RECT  92.297 7.824 92.513 9.912 ;
     RECT  92.243 1.728 92.972 3.432 ;
     RECT  92.369 11.232 93.193 11.928 ;
     RECT  92.972 1.728 93.349 3.96 ;
     RECT  92.387 4.992 93.349 6.744 ;
     RECT  93.349 1.728 93.481 6.744 ;
     RECT  92.513 7.92 93.481 9.912 ;
     RECT  92.965 0.096 93.517 0.12 ;
     RECT  93.481 1.728 93.589 9.912 ;
     RECT  93.193 11.232 93.589 12.072 ;
     RECT  93.517 0.096 93.601 0.6 ;
     RECT  93.601 0.096 93.773 0.12 ;
     RECT  92.477 13.632 93.877 17.64 ;
     RECT  93.589 1.728 94.057 12.072 ;
     RECT  93.877 13.296 94.057 17.64 ;
     RECT  94.057 1.728 94.076 17.64 ;
     RECT  94.076 1.104 94.208 17.64 ;
     RECT  92.261 19.104 94.208 19.128 ;
     RECT  89.104 97.536 94.208 97.56 ;
     RECT  94.208 1.104 94.312 181.452 ;
     RECT  94.312 1.104 94.504 181.182 ;
     RECT  94.504 1.104 94.597 10.44 ;
     RECT  94.597 0.576 94.738 10.44 ;
     RECT  94.738 0.096 94.781 10.44 ;
     RECT  94.504 14.64 94.781 16.392 ;
     RECT  94.781 0.096 94.853 6.888 ;
     RECT  94.853 0.096 94.861 6.12 ;
     RECT  94.861 0.144 94.925 6.12 ;
     RECT  94.781 14.64 94.925 14.952 ;
     RECT  94.781 15.936 94.925 15.96 ;
     RECT  94.925 0.144 95.068 3.912 ;
     RECT  95.068 0.144 95.069 2.568 ;
     RECT  94.925 5.088 95.105 6.12 ;
     RECT  95.069 0.144 95.141 2.28 ;
     RECT  94.504 13.632 95.141 13.656 ;
     RECT  95.141 0.144 95.171 1.848 ;
     RECT  94.781 7.92 95.177 10.44 ;
     RECT  94.504 11.712 95.213 12.552 ;
     RECT  95.213 11.952 95.249 12.552 ;
     RECT  95.105 5.136 95.357 6.12 ;
     RECT  94.925 14.64 95.357 14.664 ;
     RECT  95.357 5.76 95.393 6.12 ;
     RECT  95.068 3.888 95.429 3.912 ;
     RECT  95.171 0.576 95.437 1.848 ;
     RECT  95.437 0.576 95.507 1.8 ;
     RECT  95.249 12.528 95.537 12.552 ;
     RECT  95.393 6.096 95.681 6.12 ;
     RECT  95.507 0.576 95.833 0.6 ;
     RECT  95.177 7.92 95.861 9.912 ;
     RECT  95.861 7.92 96.005 9.192 ;
     RECT  95.507 1.728 96.041 1.8 ;
     RECT  96.005 7.92 96.077 9.144 ;
     RECT  96.077 7.92 96.185 8.472 ;
     RECT  96.185 7.92 96.329 8.184 ;
     RECT  96.041 1.728 96.437 1.752 ;
     RECT  96.329 7.92 96.437 7.944 ;
     RECT  95.821 6.672 96.668 6.696 ;
     RECT  96.668 6.672 96.755 7.08 ;
     RECT  96.709 5.664 96.833 5.688 ;
     RECT  94.504 97.536 99.608 97.56 ;
     RECT  99.608 2.148 99.712 181.452 ;
     RECT  99.712 2.418 99.904 181.182 ;
     RECT  99.904 97.536 105.008 97.56 ;
     RECT  105.008 2.148 105.112 181.452 ;
     RECT  105.112 2.418 105.304 181.182 ;
     RECT  105.304 97.536 110.408 97.56 ;
     RECT  110.408 2.148 110.512 181.452 ;
     RECT  110.512 2.418 110.704 181.182 ;
     RECT  110.704 97.536 115.808 97.56 ;
     RECT  115.808 2.148 115.912 181.452 ;
     RECT  115.912 2.418 116.104 181.182 ;
     RECT  116.104 97.536 121.208 97.56 ;
     RECT  121.208 2.148 121.312 181.452 ;
     RECT  121.312 2.418 121.504 181.182 ;
     RECT  121.504 97.536 122.605 97.56 ;
     RECT  122.605 96.864 124.229 97.56 ;
     RECT  124.229 97.248 124.733 97.56 ;
     RECT  124.733 97.248 125.057 97.272 ;
     RECT  126.608 2.148 126.712 181.452 ;
     RECT  126.712 2.418 126.904 181.182 ;
     RECT  126.904 96.72 128.221 96.744 ;
     RECT  128.221 96.72 128.797 96.84 ;
     RECT  128.797 96.72 128.833 96.936 ;
     RECT  128.833 96.72 129.564 97.032 ;
    LAYER M5 ;
     RECT  37.2 0.016 95.88 0.131 ;
     RECT  37.2 0.131 76.68 1.139 ;
     RECT  37.488 1.139 76.68 1.763 ;
     RECT  77.712 0.131 95.88 1.763 ;
     RECT  37.584 1.763 76.68 1.811 ;
     RECT  77.904 1.763 95.88 1.811 ;
     RECT  77.904 1.811 95.4 1.859 ;
     RECT  2.4 2.137 2.52 2.151 ;
     RECT  7.8 2.137 7.92 2.151 ;
     RECT  13.2 2.137 13.32 2.151 ;
     RECT  18.6 2.137 18.72 2.151 ;
     RECT  24 2.137 24.12 2.151 ;
     RECT  29.4 2.137 29.52 2.151 ;
     RECT  34.8 2.137 34.92 2.151 ;
     RECT  99.6 2.137 99.72 2.151 ;
     RECT  105 2.137 105.12 2.151 ;
     RECT  110.4 2.137 110.52 2.151 ;
     RECT  115.8 2.137 115.92 2.151 ;
     RECT  121.2 2.137 121.32 2.151 ;
     RECT  126.6 2.137 126.72 2.151 ;
     RECT  37.68 1.811 76.68 2.291 ;
     RECT  77.904 1.859 95.112 2.291 ;
     RECT  58.896 2.291 76.68 2.339 ;
     RECT  58.992 2.339 76.68 2.387 ;
     RECT  60.144 2.387 76.68 2.435 ;
     RECT  60.336 2.435 76.68 2.483 ;
     RECT  37.68 2.291 57.384 2.915 ;
     RECT  77.904 2.291 95.016 2.917 ;
     RECT  58.992 2.387 59.112 3.011 ;
     RECT  77.808 2.917 95.016 3.205 ;
     RECT  77.712 3.205 95.016 3.395 ;
     RECT  60.48 2.483 76.68 3.445 ;
     RECT  77.712 3.395 94.632 3.445 ;
     RECT  60.48 3.445 94.632 3.973 ;
     RECT  38.304 2.915 57.384 4.595 ;
     RECT  60.288 3.973 94.632 5.123 ;
     RECT  60.288 5.123 94.512 5.171 ;
     RECT  38.304 4.595 57.096 5.605 ;
     RECT  60.432 5.171 94.512 5.843 ;
     RECT  60.432 5.843 63.672 6.323 ;
     RECT  37.584 5.605 57.096 6.371 ;
     RECT  37.584 6.371 57 6.515 ;
     RECT  39.984 6.515 57 6.659 ;
     RECT  64.704 5.843 94.512 6.707 ;
     RECT  75.36 6.707 94.512 6.709 ;
     RECT  58.992 3.011 59.016 6.805 ;
     RECT  40.08 6.659 57 6.899 ;
     RECT  58.416 6.805 59.016 6.899 ;
     RECT  64.704 6.707 74.328 6.899 ;
     RECT  75.36 6.709 94.632 6.899 ;
     RECT  96.72 5.653 96.744 7.091 ;
     RECT  75.504 6.899 94.632 7.235 ;
     RECT  76.512 7.235 94.632 7.379 ;
     RECT  60.672 6.323 63.624 7.429 ;
     RECT  64.704 6.899 69.528 7.429 ;
     RECT  70.56 6.899 74.328 7.475 ;
     RECT  60.672 7.429 69.528 7.907 ;
     RECT  58.416 6.899 58.44 7.909 ;
     RECT  70.656 7.475 74.328 7.957 ;
     RECT  75.504 7.235 75.528 7.957 ;
     RECT  47.904 6.899 57 8.003 ;
     RECT  60.672 7.907 65.016 8.003 ;
     RECT  48.624 8.003 49.368 8.195 ;
     RECT  70.656 7.957 75.528 8.195 ;
     RECT  51 8.003 57 8.341 ;
     RECT  58.128 7.909 58.44 8.341 ;
     RECT  76.512 7.379 94.512 8.389 ;
     RECT  60.672 8.003 63.144 8.437 ;
     RECT  49.152 8.195 49.368 8.483 ;
     RECT  51 8.341 58.44 8.485 ;
     RECT  66.144 7.907 69.528 8.531 ;
     RECT  76.512 8.389 94.632 8.531 ;
     RECT  37.584 6.515 38.952 8.579 ;
     RECT  60.144 8.437 63.144 8.579 ;
     RECT  64.512 8.003 65.016 8.579 ;
     RECT  76.512 8.531 94.512 8.579 ;
     RECT  40.2 6.899 46.872 8.627 ;
     RECT  66.624 8.531 69.528 8.675 ;
     RECT  64.512 8.579 64.728 8.723 ;
     RECT  37.584 8.579 37.608 8.965 ;
     RECT  43.728 8.627 46.872 8.965 ;
     RECT  51 8.485 58.488 9.061 ;
     RECT  79.776 8.579 94.512 9.107 ;
     RECT  38.688 8.579 38.952 9.155 ;
     RECT  50.832 9.061 58.488 9.155 ;
     RECT  66.624 8.675 69.192 9.155 ;
     RECT  70.656 8.195 74.616 9.155 ;
     RECT  79.776 9.107 91.752 9.155 ;
     RECT  50.832 9.155 54.408 9.301 ;
     RECT  50.736 9.301 54.408 9.347 ;
     RECT  82.848 9.155 91.752 9.347 ;
     RECT  50.736 9.347 53.544 9.397 ;
     RECT  93.312 9.107 94.512 9.539 ;
     RECT  76.512 8.579 78.792 9.637 ;
     RECT  60.144 8.579 60.168 9.683 ;
     RECT  82.896 9.347 91.752 9.683 ;
     RECT  50.64 9.397 53.544 9.731 ;
     RECT  75.696 9.637 78.792 9.731 ;
     RECT  82.896 9.683 90.888 9.731 ;
     RECT  55.488 9.155 58.488 9.779 ;
     RECT  49.152 8.483 49.176 9.781 ;
     RECT  75.696 9.731 78.408 9.875 ;
     RECT  83.088 9.731 90.888 9.875 ;
     RECT  38.736 9.155 38.952 9.923 ;
     RECT  64.704 8.723 64.728 9.925 ;
     RECT  76.272 9.875 78.408 9.971 ;
     RECT  49.152 9.781 49.608 10.165 ;
     RECT  50.64 9.731 52.44 10.165 ;
     RECT  70.656 9.155 74.52 10.165 ;
     RECT  76.272 9.971 78.312 10.211 ;
     RECT  40.2 8.627 42.552 10.213 ;
     RECT  43.728 8.965 47.352 10.213 ;
     RECT  70.656 10.165 74.616 10.213 ;
     RECT  38.784 9.923 38.952 10.307 ;
     RECT  53.424 9.731 53.544 10.307 ;
     RECT  79.776 9.155 81.816 10.307 ;
     RECT  83.088 9.875 85.848 10.307 ;
     RECT  66.624 9.155 69.048 10.355 ;
     RECT  55.488 9.779 57.672 10.453 ;
     RECT  76.272 10.211 77.016 10.499 ;
     RECT  94.08 9.539 94.512 10.549 ;
     RECT  76.272 10.499 76.92 10.691 ;
     RECT  37.536 8.965 37.608 10.835 ;
     RECT  38.784 10.307 38.808 10.883 ;
     RECT  64.272 9.925 64.728 10.883 ;
     RECT  66.624 10.355 67.992 10.883 ;
     RECT  61.68 8.579 63.144 10.931 ;
     RECT  93.888 10.549 94.512 10.931 ;
     RECT  86.832 9.875 90.888 11.027 ;
     RECT  78 10.211 78.312 11.029 ;
     RECT  79.488 10.549 79.512 11.029 ;
     RECT  40.2 10.213 47.352 11.123 ;
     RECT  49.152 10.165 52.44 11.125 ;
     RECT  88.608 11.027 90.888 11.219 ;
     RECT  61.8 10.931 63.144 11.365 ;
     RECT  64.272 10.883 64.296 11.365 ;
     RECT  66.624 10.883 67.704 11.365 ;
     RECT  69.024 10.355 69.048 11.365 ;
     RECT  70.656 10.213 75.096 11.365 ;
     RECT  76.272 10.691 76.536 11.365 ;
     RECT  44.928 11.123 47.352 11.413 ;
     RECT  48.768 11.125 52.44 11.413 ;
     RECT  61.8 11.365 64.296 11.459 ;
     RECT  78 11.029 79.512 11.507 ;
     RECT  70.656 11.365 76.536 11.749 ;
     RECT  78 11.507 79.032 11.749 ;
     RECT  81.072 10.307 81.816 11.797 ;
     RECT  83.088 10.307 84.936 11.797 ;
     RECT  81.072 11.797 84.936 11.893 ;
     RECT  40.2 11.123 43.752 11.939 ;
     RECT  37.584 10.835 37.608 11.941 ;
     RECT  44.928 11.413 52.44 12.035 ;
     RECT  54.672 10.453 57.672 12.035 ;
     RECT  40.2 11.939 42.552 12.179 ;
     RECT  40.2 12.179 41.16 12.227 ;
     RECT  68.976 11.365 69.048 12.277 ;
     RECT  53.52 10.307 53.544 12.517 ;
     RECT  61.8 11.459 62.112 12.517 ;
     RECT  86.832 11.027 86.856 12.517 ;
     RECT  81.072 11.893 85.08 12.563 ;
     RECT  88.8 11.219 90.888 12.563 ;
     RECT  68.88 12.277 69.048 12.659 ;
     RECT  68.976 12.659 69.048 12.901 ;
     RECT  70.656 11.749 79.032 12.901 ;
     RECT  48.768 12.035 52.44 12.997 ;
     RECT  53.52 12.517 54.6 12.997 ;
     RECT  66.24 11.365 67.704 12.997 ;
     RECT  42.528 12.179 42.552 13.045 ;
     RECT  43.728 11.939 43.752 13.045 ;
     RECT  58.656 12.517 58.68 13.045 ;
     RECT  48.768 12.997 54.6 13.139 ;
     RECT  40.2 12.227 40.68 13.237 ;
     RECT  40.2 13.237 41.208 13.333 ;
     RECT  42.528 13.045 43.752 13.333 ;
     RECT  68.976 12.901 79.032 13.379 ;
     RECT  44.928 12.035 47.352 13.427 ;
     RECT  48.768 13.139 54.36 13.427 ;
     RECT  71.136 13.379 79.032 13.571 ;
     RECT  88.8 12.563 89.544 13.573 ;
     RECT  48.768 13.427 53.784 13.621 ;
     RECT  63.552 11.459 64.296 13.621 ;
     RECT  37.152 11.941 37.608 13.715 ;
     RECT  40.2 13.333 43.752 13.715 ;
     RECT  48.384 13.621 53.784 13.715 ;
     RECT  58.656 13.045 59.304 13.715 ;
     RECT  81.072 12.563 84.936 13.715 ;
     RECT  37.152 13.715 37.176 13.811 ;
     RECT  48.384 13.715 53.304 13.811 ;
     RECT  71.136 13.571 76.968 13.859 ;
     RECT  68.976 13.379 69.96 13.907 ;
     RECT  83.04 13.715 84.936 13.907 ;
     RECT  44.976 13.427 47.352 13.909 ;
     RECT  48.384 13.811 53.064 13.909 ;
     RECT  56.304 12.035 57.672 13.957 ;
     RECT  63.456 13.621 64.296 13.957 ;
     RECT  65.568 12.997 67.704 14.003 ;
     RECT  44.976 13.909 53.064 14.195 ;
     RECT  65.568 14.003 67.512 14.197 ;
     RECT  65.52 14.197 67.512 14.243 ;
     RECT  40.2 13.715 41.592 14.291 ;
     RECT  42.768 13.715 42.792 14.291 ;
     RECT  44.976 14.195 52.44 14.339 ;
     RECT  60.96 12.517 62.112 14.339 ;
     RECT  88.8 13.573 89.592 14.339 ;
     RECT  81.072 13.715 81.816 14.437 ;
     RECT  80.928 14.437 81.816 14.579 ;
     RECT  71.136 13.859 76.296 14.627 ;
     RECT  67.104 14.243 67.512 14.675 ;
     RECT  94.08 10.931 94.512 14.675 ;
     RECT  86.448 12.517 86.856 14.773 ;
     RECT  88.8 14.339 89.496 14.773 ;
     RECT  58.656 13.715 58.68 14.821 ;
     RECT  59.808 14.197 59.832 14.821 ;
     RECT  86.448 14.773 87 14.821 ;
     RECT  88.56 14.773 89.496 14.821 ;
     RECT  83.088 13.907 84.936 14.867 ;
     RECT  78 13.571 79.032 14.915 ;
     RECT  81.648 14.579 81.816 14.915 ;
     RECT  56.256 13.957 57.672 15.061 ;
     RECT  58.656 14.821 59.832 15.061 ;
     RECT  86.448 14.821 89.496 15.301 ;
     RECT  54.72 14.533 54.744 15.395 ;
     RECT  56.256 15.061 59.832 15.395 ;
     RECT  63.456 13.957 64.392 15.443 ;
     RECT  56.4 15.395 59.208 15.491 ;
     RECT  90.864 12.563 90.888 15.731 ;
     RECT  81.648 14.915 81.672 15.923 ;
     RECT  65.52 14.243 65.592 15.925 ;
     RECT  67.2 14.675 67.512 15.925 ;
     RECT  78 14.915 78.408 16.019 ;
     RECT  86.064 15.301 89.496 16.019 ;
     RECT  68.976 13.907 69.048 16.069 ;
     RECT  75.84 14.627 76.296 16.213 ;
     RECT  56.4 15.491 58.776 16.259 ;
     RECT  75.744 16.213 76.296 16.261 ;
     RECT  48.24 14.339 52.44 16.309 ;
     RECT  53.664 14.773 53.688 16.309 ;
     RECT  68.88 16.069 69.048 16.403 ;
     RECT  48.24 16.309 53.688 16.499 ;
     RECT  56.4 16.259 58.584 16.501 ;
     RECT  61.632 14.339 62.112 16.501 ;
     RECT  90.672 15.829 90.696 16.501 ;
     RECT  75.744 16.261 76.968 16.595 ;
     RECT  71.136 14.627 74.616 16.597 ;
     RECT  50.16 16.499 53.688 16.645 ;
     RECT  83.088 14.867 84.36 16.645 ;
     RECT  71.136 16.597 74.712 16.741 ;
     RECT  75.744 16.595 76.344 16.741 ;
     RECT  50.16 16.645 53.736 16.787 ;
     RECT  83.088 16.645 84.936 16.787 ;
     RECT  88.8 16.019 89.496 16.787 ;
     RECT  90.624 16.501 90.696 16.835 ;
     RECT  65.52 15.925 67.512 17.027 ;
     RECT  71.136 16.741 76.344 17.075 ;
     RECT  67.104 17.027 67.512 17.077 ;
     RECT  61.632 16.501 62.376 17.123 ;
     RECT  92.88 16.981 92.904 17.123 ;
     RECT  50.304 16.787 53.736 17.171 ;
     RECT  86.064 16.019 87.432 17.171 ;
     RECT  86.352 17.171 87.432 17.267 ;
     RECT  63.456 15.443 64.296 17.461 ;
     RECT  65.52 17.027 65.832 17.461 ;
     RECT  76.128 17.075 76.344 17.555 ;
     RECT  76.128 17.555 76.296 17.651 ;
     RECT  45.6 14.339 47.16 17.699 ;
     RECT  87.408 17.267 87.432 17.699 ;
     RECT  90.624 16.835 90.648 17.699 ;
     RECT  48.24 16.499 48.936 17.989 ;
     RECT  50.304 17.171 53.688 17.989 ;
     RECT  78 16.019 78.312 17.989 ;
     RECT  86.352 17.267 86.376 18.035 ;
     RECT  63.456 17.461 65.832 18.133 ;
     RECT  67.104 17.077 67.656 18.133 ;
     RECT  46.896 17.699 47.16 18.179 ;
     RECT  47.088 18.179 47.16 18.229 ;
     RECT  48.24 17.989 53.688 18.229 ;
     RECT  61.632 17.123 62.232 18.275 ;
     RECT  47.088 18.229 53.688 18.563 ;
     RECT  83.088 16.787 84.36 18.659 ;
     RECT  71.136 17.075 74.616 18.709 ;
     RECT  68.976 16.403 69.048 18.803 ;
     RECT  76.272 17.651 76.296 18.997 ;
     RECT  50.304 18.563 53.688 19.235 ;
     RECT  63.456 18.133 67.656 19.237 ;
     RECT  83.088 18.659 84.312 19.285 ;
     RECT  71.136 18.709 75.192 19.333 ;
     RECT  55.968 16.501 58.584 19.379 ;
     RECT  82.608 19.285 84.312 19.427 ;
     RECT  90.432 18.757 90.456 19.427 ;
     RECT  78 17.989 78.408 19.573 ;
     RECT  85.392 19.141 85.416 19.763 ;
     RECT  83.184 19.427 84.312 20.003 ;
     RECT  76.272 18.997 77.016 20.101 ;
     RECT  78 19.573 79.224 20.101 ;
     RECT  83.184 20.003 83.832 20.147 ;
     RECT  63.456 19.237 67.944 20.197 ;
     RECT  76.272 20.101 79.224 20.293 ;
     RECT  47.088 18.563 48.936 20.579 ;
     RECT  76.272 20.293 79.848 20.579 ;
     RECT  63.408 20.197 67.944 20.581 ;
     RECT  71.136 19.333 75.24 21.059 ;
     RECT  77.904 20.579 78.312 21.155 ;
     RECT  79.824 20.579 79.848 21.155 ;
     RECT  81.504 19.861 81.528 21.155 ;
     RECT  45.6 17.699 45.912 21.301 ;
     RECT  47.136 20.579 48.936 21.541 ;
     RECT  83.184 20.147 83.712 22.117 ;
     RECT  45.216 21.301 45.912 22.165 ;
     RECT  46.992 21.541 48.936 22.259 ;
     RECT  46.992 22.259 47.16 22.307 ;
     RECT  46.992 22.307 47.016 22.451 ;
     RECT  78 21.155 78.312 24.613 ;
     RECT  82.608 22.117 83.712 24.853 ;
     RECT  82.32 24.853 83.712 24.899 ;
     RECT  53.664 19.235 53.688 25.621 ;
     RECT  71.136 21.059 74.616 25.621 ;
     RECT  50.304 19.235 52.344 25.715 ;
     RECT  63.36 20.581 67.944 26.677 ;
     RECT  68.976 18.803 69 26.677 ;
     RECT  48.24 22.259 48.936 27.395 ;
     RECT  88.8 16.787 89.208 27.971 ;
     RECT  82.32 24.899 82.344 28.019 ;
     RECT  40.2 14.291 41.016 55.331 ;
     RECT  42.336 55.573 42.36 57.347 ;
     RECT  45.216 22.165 46.008 57.349 ;
     RECT  78 24.613 78.408 60.467 ;
     RECT  78 60.467 78.312 60.901 ;
     RECT  77.856 60.901 78.312 92.483 ;
     RECT  51 25.715 52.344 92.725 ;
     RECT  63.36 26.677 69 105.973 ;
     RECT  56.4 19.379 58.584 107.219 ;
     RECT  55.392 97.525 55.416 111.779 ;
     RECT  48.24 27.395 48.696 111.973 ;
     RECT  45.216 57.349 46.68 112.019 ;
     RECT  48.24 111.973 49.608 112.117 ;
     RECT  48.24 112.117 49.992 112.163 ;
     RECT  56.4 107.219 56.808 112.261 ;
     RECT  49.968 112.163 49.992 115.187 ;
     RECT  61.632 18.275 62.112 138.997 ;
     RECT  63.36 105.973 69.336 138.997 ;
     RECT  76.272 20.579 76.296 140.243 ;
     RECT  61.632 138.997 69.336 141.157 ;
     RECT  48.24 112.163 48.696 143.605 ;
     RECT  70.512 25.621 74.616 143.699 ;
     RECT  70.512 143.699 70.536 144.133 ;
     RECT  71.904 143.699 74.616 144.275 ;
     RECT  58.32 107.219 58.584 145.283 ;
     RECT  47.616 143.605 48.696 145.331 ;
     RECT  72.6 144.275 74.616 145.331 ;
     RECT  58.416 145.283 58.584 145.859 ;
     RECT  60.336 15.637 60.36 145.859 ;
     RECT  47.616 145.331 48.456 145.955 ;
     RECT  47.616 145.955 48.216 146.437 ;
     RECT  61.344 141.157 69.336 149.939 ;
     RECT  44.016 20.485 44.04 150.419 ;
     RECT  45.216 112.019 46.008 151.331 ;
     RECT  45.36 151.331 46.008 151.573 ;
     RECT  74.592 145.331 74.616 168.179 ;
     RECT  76.128 140.725 76.152 169.331 ;
     RECT  61.344 149.939 65.256 172.163 ;
     RECT  66.336 149.939 69.336 173.221 ;
     RECT  70.464 144.133 70.536 173.315 ;
     RECT  45.36 151.573 46.488 173.555 ;
     RECT  44.208 150.421 44.232 174.035 ;
     RECT  51 92.725 52.584 174.325 ;
     RECT  53.616 25.621 53.688 174.325 ;
     RECT  66.288 173.221 69.336 174.373 ;
     RECT  70.512 173.315 70.536 174.373 ;
     RECT  61.344 172.163 63.24 174.467 ;
     RECT  45.6 173.555 46.488 174.563 ;
     RECT  72.6 145.331 73.464 175.045 ;
     RECT  61.632 174.467 63.24 175.091 ;
     RECT  64.272 172.163 65.256 175.091 ;
     RECT  66.288 174.373 71.256 175.139 ;
     RECT  55.44 112.261 56.808 175.525 ;
     RECT  66.288 175.139 69.528 175.525 ;
     RECT  58.416 145.859 58.488 175.619 ;
     RECT  64.272 175.091 64.824 175.619 ;
     RECT  55.392 175.525 56.808 176.005 ;
     RECT  72.48 175.045 73.464 176.005 ;
     RECT  55.2 176.005 57.336 176.053 ;
     RECT  54.672 176.053 57.336 176.101 ;
     RECT  61.632 175.091 63.144 176.101 ;
     RECT  58.464 175.619 58.488 176.195 ;
     RECT  60.192 145.861 60.216 176.195 ;
     RECT  64.272 175.619 64.728 176.195 ;
     RECT  70.512 175.139 71.256 176.195 ;
     RECT  70.56 176.195 71.256 176.485 ;
     RECT  61.584 176.101 63.144 176.629 ;
     RECT  72.48 176.005 74.184 176.675 ;
     RECT  51 174.325 53.688 176.677 ;
     RECT  54.672 176.101 57.384 176.677 ;
     RECT  47.568 146.437 48.216 176.723 ;
     RECT  50.064 176.677 57.384 176.867 ;
     RECT  66.048 175.525 69.528 177.205 ;
     RECT  70.56 176.485 71.304 177.205 ;
     RECT  47.616 176.723 48.216 177.299 ;
     RECT  66.048 177.205 71.304 177.299 ;
     RECT  64.32 176.195 64.728 177.781 ;
     RECT  61.536 176.629 63.144 177.875 ;
     RECT  51 176.867 57.384 177.923 ;
     RECT  63.12 177.875 63.144 178.213 ;
     RECT  64.32 177.781 64.776 178.213 ;
     RECT  63.12 178.213 64.776 178.403 ;
     RECT  63.12 178.403 63.144 178.451 ;
     RECT  64.752 178.403 64.776 178.451 ;
     RECT  72.6 176.675 74.184 178.451 ;
     RECT  52.56 177.923 57.384 178.645 ;
     RECT  66.048 177.299 68.952 178.645 ;
     RECT  70.032 177.299 71.304 178.645 ;
     RECT  66.048 178.645 71.304 178.837 ;
     RECT  72.6 178.451 74.088 178.837 ;
     RECT  45.6 174.563 45.912 178.933 ;
     RECT  45.6 178.933 46.296 179.317 ;
     RECT  47.28 179.221 47.304 179.317 ;
     RECT  51 177.923 51.312 179.365 ;
     RECT  52.56 178.645 57.528 179.365 ;
     RECT  51 179.365 57.528 179.461 ;
     RECT  61.536 177.875 62.112 179.461 ;
     RECT  66.048 178.837 74.088 179.461 ;
     RECT  50.256 179.461 57.528 179.509 ;
     RECT  65.904 179.461 74.088 179.509 ;
     RECT  50.256 179.509 58.056 180.179 ;
     RECT  65.808 179.509 74.616 180.179 ;
     RECT  48.624 178.645 48.648 180.709 ;
     RECT  45.6 179.317 47.304 181.237 ;
     RECT  48.624 180.709 49.128 181.237 ;
     RECT  50.256 180.179 52.584 181.237 ;
     RECT  53.904 180.179 58.056 181.237 ;
     RECT  60.72 179.461 63.048 181.237 ;
     RECT  64.08 179.509 64.104 181.237 ;
     RECT  65.808 180.179 71.16 181.237 ;
     RECT  72.432 180.179 74.616 181.237 ;
     RECT  45.6 181.237 71.16 181.285 ;
     RECT  72.144 181.237 75.048 181.285 ;
     RECT  2.4 2.151 2.712 181.449 ;
     RECT  7.8 2.151 8.112 181.449 ;
     RECT  13.2 2.151 13.512 181.449 ;
     RECT  18.6 2.151 18.912 181.449 ;
     RECT  24 2.151 24.312 181.449 ;
     RECT  29.4 2.151 29.712 181.449 ;
     RECT  34.8 2.151 35.112 181.449 ;
     RECT  40.2 55.331 40.512 181.449 ;
     RECT  78 92.483 78.312 181.449 ;
     RECT  83.4 24.899 83.712 181.449 ;
     RECT  88.8 27.971 89.112 181.449 ;
     RECT  94.2 14.675 94.512 181.449 ;
     RECT  99.6 2.151 99.912 181.449 ;
     RECT  105 2.151 105.312 181.449 ;
     RECT  110.4 2.151 110.712 181.449 ;
     RECT  115.8 2.151 116.112 181.449 ;
     RECT  121.2 2.151 121.512 181.449 ;
     RECT  126.6 2.151 126.912 181.449 ;
     RECT  2.4 181.449 2.52 181.463 ;
     RECT  7.8 181.449 7.92 181.463 ;
     RECT  13.2 181.449 13.32 181.463 ;
     RECT  18.6 181.449 18.72 181.463 ;
     RECT  24 181.449 24.12 181.463 ;
     RECT  29.4 181.449 29.52 181.463 ;
     RECT  34.8 181.449 34.92 181.463 ;
     RECT  40.2 181.449 40.32 181.463 ;
     RECT  45.6 181.285 75.048 181.463 ;
     RECT  78 181.449 78.12 181.463 ;
     RECT  83.4 181.449 83.52 181.463 ;
     RECT  88.8 181.449 88.92 181.463 ;
     RECT  94.2 181.449 94.32 181.463 ;
     RECT  99.6 181.449 99.72 181.463 ;
     RECT  105 181.449 105.12 181.463 ;
     RECT  110.4 181.449 110.52 181.463 ;
     RECT  115.8 181.449 115.92 181.463 ;
     RECT  121.2 181.449 121.32 181.463 ;
     RECT  126.6 181.449 126.72 181.463 ;
     RECT  45.936 181.463 75.048 183.568 ;
     RECT  76.728 0.131 77.472 0.132 ;
     RECT  76.68 0.132 77.712 1.763 ;
     RECT  76.68 1.763 77.904 2.917 ;
     RECT  57.384 2.291 58.896 2.339 ;
     RECT  59.112 2.387 60.144 2.435 ;
     RECT  59.112 2.435 60.336 2.483 ;
     RECT  59.112 2.483 60.48 3.011 ;
     RECT  76.68 2.917 77.808 3.205 ;
     RECT  59.016 3.011 60.48 3.973 ;
     RECT  76.68 3.205 77.712 3.445 ;
     RECT  59.016 3.973 60.288 5.171 ;
     RECT  59.016 5.171 60.432 6.323 ;
     RECT  63.672 5.843 64.704 6.323 ;
     RECT  63.624 6.323 64.704 7.429 ;
     RECT  57 6.371 57.096 6.805 ;
     RECT  38.952 6.515 39.984 6.659 ;
     RECT  38.952 6.659 40.08 6.899 ;
     RECT  74.328 6.707 75.36 6.899 ;
     RECT  57 6.805 58.416 7.909 ;
     RECT  38.952 6.899 40.2 10.307 ;
     RECT  46.872 6.899 47.904 8.003 ;
     RECT  69.528 6.899 70.56 7.475 ;
     RECT  74.328 6.899 75.504 7.957 ;
     RECT  75.528 7.235 76.512 8.195 ;
     RECT  94.512 7.379 94.632 8.389 ;
     RECT  69.528 7.475 70.656 8.675 ;
     RECT  65.016 7.907 66.144 8.531 ;
     RECT  57 7.909 58.128 8.341 ;
     RECT  46.872 8.003 48.624 8.195 ;
     RECT  49.368 8.003 51 8.483 ;
     RECT  63.144 8.003 64.512 8.723 ;
     RECT  46.872 8.195 47.352 8.965 ;
     RECT  74.616 8.195 76.512 9.155 ;
     RECT  49.176 8.483 51 9.061 ;
     RECT  37.608 8.579 38.688 9.155 ;
     RECT  60.168 8.579 61.68 9.683 ;
     RECT  78.792 8.579 79.776 9.731 ;
     RECT  42.552 8.627 43.728 10.213 ;
     RECT  69.192 8.675 70.656 9.155 ;
     RECT  63.144 8.723 64.704 9.925 ;
     RECT  49.176 9.061 50.832 9.301 ;
     RECT  37.608 9.155 38.736 9.923 ;
     RECT  54.408 9.155 55.488 9.347 ;
     RECT  74.52 9.155 76.512 9.637 ;
     RECT  81.816 9.155 82.848 9.347 ;
     RECT  49.176 9.301 50.736 9.397 ;
     RECT  53.544 9.347 55.488 10.453 ;
     RECT  81.816 9.347 82.896 9.731 ;
     RECT  49.176 9.397 50.64 9.781 ;
     RECT  93.888 9.539 94.08 10.549 ;
     RECT  74.52 9.637 75.696 9.875 ;
     RECT  52.44 9.731 53.424 10.307 ;
     RECT  78.408 9.731 79.776 9.971 ;
     RECT  81.816 9.731 83.088 11.797 ;
     RECT  49.608 9.781 50.64 10.165 ;
     RECT  74.52 9.875 76.272 10.165 ;
     RECT  85.848 9.875 86.832 10.307 ;
     RECT  37.608 9.923 38.784 10.883 ;
     RECT  63.144 9.925 64.272 11.365 ;
     RECT  78.312 9.971 79.776 10.307 ;
     RECT  74.616 10.165 76.272 10.213 ;
     RECT  77.016 10.211 78 10.499 ;
     RECT  75.096 10.213 76.272 11.365 ;
     RECT  38.808 10.307 40.2 10.883 ;
     RECT  52.44 10.307 53.52 12.997 ;
     RECT  78.312 10.307 79.512 10.549 ;
     RECT  67.992 10.355 69.024 10.883 ;
     RECT  53.544 10.453 54.672 12.035 ;
     RECT  76.92 10.499 78 10.691 ;
     RECT  78.312 10.549 79.488 11.029 ;
     RECT  76.536 10.691 78 11.749 ;
     RECT  37.536 10.835 37.584 11.941 ;
     RECT  67.704 10.883 69.024 11.365 ;
     RECT  43.752 11.123 44.928 13.427 ;
     RECT  47.352 11.125 48.768 11.413 ;
     RECT  67.704 11.365 68.976 12.277 ;
     RECT  62.112 11.459 63.552 13.621 ;
     RECT  42.552 11.939 43.728 13.045 ;
     RECT  47.352 12.035 48.768 13.621 ;
     RECT  53.544 12.035 54.6 12.517 ;
     RECT  41.16 12.179 42.528 12.227 ;
     RECT  40.68 12.227 42.528 13.237 ;
     RECT  67.704 12.277 68.88 12.659 ;
     RECT  57.672 12.517 58.656 15.061 ;
     RECT  85.08 12.517 86.448 12.563 ;
     RECT  84.936 12.563 86.448 14.867 ;
     RECT  89.544 12.563 90.864 13.573 ;
     RECT  67.704 12.659 68.976 14.003 ;
     RECT  64.296 12.997 65.568 13.957 ;
     RECT  54.36 13.139 54.6 13.427 ;
     RECT  41.208 13.237 42.528 13.333 ;
     RECT  69.96 13.379 71.136 13.907 ;
     RECT  43.752 13.427 44.976 13.715 ;
     RECT  53.784 13.427 54.6 13.715 ;
     RECT  76.968 13.571 78 13.859 ;
     RECT  89.592 13.573 90.864 14.339 ;
     RECT  47.352 13.621 48.384 13.909 ;
     RECT  62.112 13.621 63.456 16.501 ;
     RECT  41.592 13.715 42.768 14.291 ;
     RECT  53.304 13.715 54.6 13.811 ;
     RECT  58.68 13.715 59.304 14.197 ;
     RECT  81.816 13.715 83.04 13.907 ;
     RECT  53.064 13.811 54.6 14.195 ;
     RECT  81.816 13.907 83.088 14.915 ;
     RECT  64.392 13.957 65.568 14.197 ;
     RECT  67.512 14.003 68.976 16.069 ;
     RECT  52.44 14.195 54.6 14.533 ;
     RECT  58.68 14.197 59.808 14.821 ;
     RECT  59.832 14.197 60.96 14.339 ;
     RECT  64.392 14.197 65.52 15.443 ;
     RECT  65.592 14.243 67.104 14.675 ;
     RECT  47.16 14.339 48.24 18.229 ;
     RECT  59.832 14.339 61.632 15.395 ;
     RECT  89.496 14.339 90.864 15.731 ;
     RECT  52.44 14.533 54.72 14.773 ;
     RECT  54.744 14.533 56.256 15.395 ;
     RECT  74.616 14.627 75.84 16.213 ;
     RECT  65.592 14.675 67.2 15.925 ;
     RECT  52.44 14.773 53.664 16.309 ;
     RECT  53.688 14.773 54.72 15.395 ;
     RECT  86.064 14.867 86.448 15.301 ;
     RECT  81.672 14.915 83.088 15.923 ;
     RECT  53.688 15.395 53.736 16.645 ;
     RECT  55.968 15.395 56.4 16.501 ;
     RECT  59.208 15.395 61.632 15.491 ;
     RECT  64.296 15.443 65.52 17.461 ;
     RECT  60.336 15.491 61.632 15.637 ;
     RECT  60.36 15.637 61.632 141.157 ;
     RECT  89.496 15.731 90.696 15.829 ;
     RECT  89.496 15.829 90.672 16.501 ;
     RECT  87.432 16.019 88.8 17.699 ;
     RECT  67.512 16.069 68.88 16.403 ;
     RECT  74.616 16.213 75.744 16.597 ;
     RECT  76.968 16.261 78 16.595 ;
     RECT  67.512 16.403 68.976 17.077 ;
     RECT  48.936 16.499 50.16 16.787 ;
     RECT  62.376 16.501 63.456 17.123 ;
     RECT  89.496 16.501 90.624 16.787 ;
     RECT  74.712 16.597 75.744 16.741 ;
     RECT  84.936 16.645 86.064 16.787 ;
     RECT  48.936 16.787 50.304 17.989 ;
     RECT  89.208 16.787 90.624 17.699 ;
     RECT  92.904 16.981 94.2 17.123 ;
     RECT  65.832 17.027 67.104 18.133 ;
     RECT  74.616 17.075 76.128 17.651 ;
     RECT  67.656 17.077 68.976 19.237 ;
     RECT  62.232 17.123 63.456 18.275 ;
     RECT  86.376 17.267 87.408 17.699 ;
     RECT  76.296 17.555 76.344 18.997 ;
     RECT  74.616 17.651 76.272 18.709 ;
     RECT  45.912 17.699 46.896 18.179 ;
     RECT  89.208 17.699 90.456 18.757 ;
     RECT  45.912 18.179 47.088 20.579 ;
     RECT  62.112 18.275 63.456 20.197 ;
     RECT  48.936 18.563 50.304 25.715 ;
     RECT  84.312 18.659 84.36 19.141 ;
     RECT  75.192 18.709 76.272 19.333 ;
     RECT  89.208 18.757 90.432 19.427 ;
     RECT  77.016 18.997 78 20.101 ;
     RECT  84.312 19.141 85.392 19.763 ;
     RECT  52.344 19.235 53.664 25.621 ;
     RECT  67.944 19.237 68.976 26.677 ;
     RECT  75.24 19.333 76.272 21.059 ;
     RECT  62.112 20.197 63.408 20.581 ;
     RECT  45.912 20.579 47.136 21.541 ;
     RECT  78.312 20.579 79.824 21.155 ;
     RECT  62.112 20.581 63.36 138.997 ;
     RECT  44.04 21.301 45.216 150.419 ;
     RECT  45.912 21.541 46.992 22.165 ;
     RECT  46.008 22.165 46.992 22.451 ;
     RECT  47.16 22.259 48.24 22.307 ;
     RECT  47.016 22.307 48.24 22.451 ;
     RECT  82.344 24.899 83.4 28.019 ;
     RECT  52.344 25.621 53.616 92.725 ;
     RECT  69 25.621 70.512 105.973 ;
     RECT  52.584 92.725 53.616 174.325 ;
     RECT  55.416 97.525 56.4 111.779 ;
     RECT  69.336 105.973 70.512 144.133 ;
     RECT  56.808 107.219 58.32 145.283 ;
     RECT  55.44 111.779 56.4 112.261 ;
     RECT  49.608 111.973 51 112.117 ;
     RECT  49.992 112.117 51 115.187 ;
     RECT  48.696 112.163 49.968 115.187 ;
     RECT  74.616 140.725 76.128 168.179 ;
     RECT  60.36 141.157 61.344 145.859 ;
     RECT  70.536 143.699 71.904 144.275 ;
     RECT  69.336 144.133 70.464 173.315 ;
     RECT  73.464 145.331 74.592 168.179 ;
     RECT  60.336 145.859 61.344 145.861 ;
     RECT  60.216 145.861 61.344 174.467 ;
     RECT  65.256 149.939 66.336 173.221 ;
     RECT  44.208 150.419 45.216 150.421 ;
     RECT  44.232 150.421 45.216 151.331 ;
     RECT  44.232 151.331 45.36 173.555 ;
     RECT  46.488 151.573 47.568 174.563 ;
     RECT  63.24 172.163 64.272 175.091 ;
     RECT  65.256 173.221 66.288 175.091 ;
     RECT  69.336 173.315 70.512 174.373 ;
     RECT  44.232 173.555 45.6 174.035 ;
     RECT  71.256 174.373 72.6 175.045 ;
     RECT  60.216 174.467 61.632 176.101 ;
     RECT  71.256 175.045 72.48 176.485 ;
     RECT  63.144 175.091 64.272 176.195 ;
     RECT  64.824 175.091 66.288 175.525 ;
     RECT  69.528 175.139 70.512 176.195 ;
     RECT  64.824 175.525 66.048 175.619 ;
     RECT  58.416 175.619 58.464 176.005 ;
     RECT  64.728 175.619 66.048 177.781 ;
     RECT  53.688 176.005 55.2 176.053 ;
     RECT  57.336 176.005 58.464 176.101 ;
     RECT  53.688 176.053 54.672 176.677 ;
     RECT  57.384 176.101 58.464 176.195 ;
     RECT  60.216 176.101 61.584 176.195 ;
     RECT  61.536 176.195 61.584 176.629 ;
     RECT  63.144 176.195 64.32 178.213 ;
     RECT  69.528 176.195 70.56 177.205 ;
     RECT  71.304 176.485 72.48 176.675 ;
     RECT  71.304 176.675 72.6 178.837 ;
     RECT  68.952 177.299 70.032 178.645 ;
     RECT  64.776 177.781 66.048 178.451 ;
     RECT  62.112 177.875 63.12 178.451 ;
     RECT  51.312 177.923 52.56 179.365 ;
     RECT  63.144 178.403 64.752 178.451 ;
     RECT  62.112 178.451 64.104 179.461 ;
     RECT  65.808 178.451 66.048 179.461 ;
     RECT  74.088 178.451 74.184 179.509 ;
     RECT  46.296 179.221 47.28 179.317 ;
     RECT  47.304 179.221 48.624 181.237 ;
     RECT  63.048 179.461 64.104 179.509 ;
     RECT  65.808 179.461 65.904 179.509 ;
     RECT  63.048 179.509 64.08 181.237 ;
     RECT  52.584 180.179 53.904 181.237 ;
     RECT  71.16 180.179 72.432 181.237 ;
     RECT  49.128 180.709 50.256 181.237 ;
     RECT  71.16 181.237 72.144 181.285 ;
  END
END qkd_kvwq_leaf_s_w129_m
END LIBRARY
